<?xml version="1.0" encoding="utf-8" standalone="no"?>
<device schemaVersion="1.1" xmlns:xs="http://www.w3.org/2001/XMLSchema-instance" noNamespaceSchemaLocation="CMSIS-SVD.xsd">
  <vendor>PUYA Co.Ltd</vendor>
  <vendorID>PUYA</vendorID>
  <name>PY32F410xx</name>
  <series>ARMCM4</series>
  <version>1.2</version>
  <cpu>
    <name>CM4</name>
    <revision>r0p1</revision>
    <endian>little</endian>
    <mpuPresent>true</mpuPresent>
    <fpuPresent>true</fpuPresent>
    <nvicPrioBits>4</nvicPrioBits>
    <vendorSystickConfig>false</vendorSystickConfig>
  </cpu>
  <addressUnitBits>8</addressUnitBits>
  <width>32</width>
  <size>32</size>
  <access>read-write</access>
  <resetValue>0x0</resetValue>
  <resetMask>0xFFFFFFFF</resetMask>
  <peripherals>
    <peripheral>
      <name>ADC</name>
      <baseAddress>0x40012400</baseAddress>
      <addressBlock>
        <offset>0x0</offset>
        <size>0x310</size>
        <usage>registers</usage>
      </addressBlock>
      <registers>
        <register>
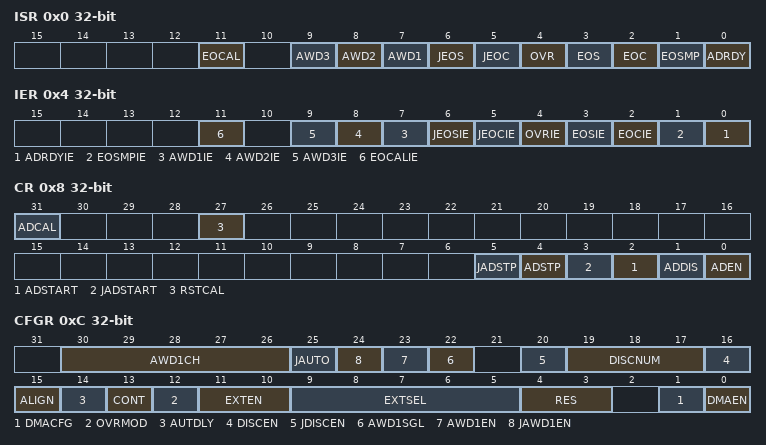
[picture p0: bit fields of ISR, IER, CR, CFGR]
          <name>ISR</name>
          <addressOffset>0x0</addressOffset>
          <fields>
            <field>
              <name>ADRDY</name>
              <bitRange>[0:0]</bitRange>
            </field>
            <field>
              <name>EOSMP</name>
              <bitRange>[1:1]</bitRange>
            </field>
            <field>
              <name>EOC</name>
              <bitRange>[2:2]</bitRange>
            </field>
            <field>
              <name>EOS</name>
              <bitRange>[3:3]</bitRange>
            </field>
            <field>
              <name>OVR</name>
              <bitRange>[4:4]</bitRange>
            </field>
            <field>
              <name>JEOC</name>
              <bitRange>[5:5]</bitRange>
            </field>
            <field>
              <name>JEOS</name>
              <bitRange>[6:6]</bitRange>
            </field>
            <field>
              <name>AWD1</name>
              <bitRange>[7:7]</bitRange>
            </field>
            <field>
              <name>AWD2</name>
              <bitRange>[8:8]</bitRange>
            </field>
            <field>
              <name>AWD3</name>
              <bitRange>[9:9]</bitRange>
            </field>
            <field>
              <name>EOCAL</name>
              <bitRange>[11:11]</bitRange>
            </field>
          </fields>
        </register>
        <register>
          <name>IER</name>
          <addressOffset>0x4</addressOffset>
          <fields>
            <field>
              <name>ADRDYIE</name>
              <bitRange>[0:0]</bitRange>
            </field>
            <field>
              <name>EOSMPIE</name>
              <bitRange>[1:1]</bitRange>
            </field>
            <field>
              <name>EOCIE</name>
              <bitRange>[2:2]</bitRange>
            </field>
            <field>
              <name>EOSIE</name>
              <bitRange>[3:3]</bitRange>
            </field>
            <field>
              <name>OVRIE</name>
              <bitRange>[4:4]</bitRange>
            </field>
            <field>
              <name>JEOCIE</name>
              <bitRange>[5:5]</bitRange>
            </field>
            <field>
              <name>JEOSIE</name>
              <bitRange>[6:6]</bitRange>
            </field>
            <field>
              <name>AWD1IE</name>
              <bitRange>[7:7]</bitRange>
            </field>
            <field>
              <name>AWD2IE</name>
              <bitRange>[8:8]</bitRange>
            </field>
            <field>
              <name>AWD3IE</name>
              <bitRange>[9:9]</bitRange>
            </field>
            <field>
              <name>EOCALIE</name>
              <bitRange>[11:11]</bitRange>
            </field>
          </fields>
        </register>
        <register>
          <name>CR</name>
          <addressOffset>0x8</addressOffset>
          <fields>
            <field>
              <name>ADEN</name>
              <bitRange>[0:0]</bitRange>
            </field>
            <field>
              <name>ADDIS</name>
              <bitRange>[1:1]</bitRange>
            </field>
            <field>
              <name>ADSTART</name>
              <bitRange>[2:2]</bitRange>
            </field>
            <field>
              <name>JADSTART</name>
              <bitRange>[3:3]</bitRange>
            </field>
            <field>
              <name>ADSTP</name>
              <bitRange>[4:4]</bitRange>
            </field>
            <field>
              <name>JADSTP</name>
              <bitRange>[5:5]</bitRange>
            </field>
            <field>
              <name>RSTCAL</name>
              <bitRange>[27:27]</bitRange>
            </field>
            <field>
              <name>ADCAL</name>
              <bitRange>[31:31]</bitRange>
            </field>
          </fields>
        </register>
        <register>
          <name>CFGR</name>
          <addressOffset>0xC</addressOffset>
          <fields>
            <field>
              <name>DMAEN</name>
              <bitRange>[0:0]</bitRange>
            </field>
            <field>
              <name>DMACFG</name>
              <bitRange>[1:1]</bitRange>
            </field>
            <field>
              <name>RES</name>
              <bitRange>[4:3]</bitRange>
            </field>
            <field>
              <name>EXTSEL</name>
              <bitRange>[9:5]</bitRange>
            </field>
            <field>
              <name>EXTEN</name>
              <bitRange>[11:10]</bitRange>
            </field>
            <field>
              <name>OVRMOD</name>
              <bitRange>[12:12]</bitRange>
            </field>
            <field>
              <name>CONT</name>
              <bitRange>[13:13]</bitRange>
            </field>
            <field>
              <name>AUTDLY</name>
              <bitRange>[14:14]</bitRange>
            </field>
            <field>
              <name>ALIGN</name>
              <bitRange>[15:15]</bitRange>
            </field>
            <field>
              <name>DISCEN</name>
              <bitRange>[16:16]</bitRange>
            </field>
            <field>
              <name>DISCNUM</name>
              <bitRange>[19:17]</bitRange>
            </field>
            <field>
              <name>JDISCEN</name>
              <bitRange>[20:20]</bitRange>
            </field>
            <field>
              <name>AWD1SGL</name>
              <bitRange>[22:22]</bitRange>
            </field>
            <field>
              <name>AWD1EN</name>
              <bitRange>[23:23]</bitRange>
            </field>
            <field>
              <name>JAWD1EN</name>
              <bitRange>[24:24]</bitRange>
            </field>
            <field>
              <name>JAUTO</name>
              <bitRange>[25:25]</bitRange>
            </field>
            <field>
              <name>AWD1CH</name>
              <bitRange>[30:26]</bitRange>
            </field>
          </fields>
        </register>
        <register>
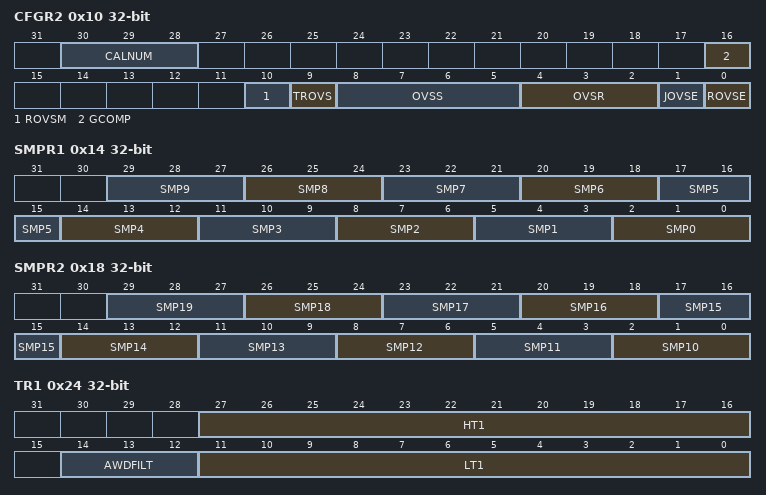
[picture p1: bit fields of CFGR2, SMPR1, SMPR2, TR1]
          <name>CFGR2</name>
          <addressOffset>0x10</addressOffset>
          <fields>
            <field>
              <name>ROVSE</name>
              <bitRange>[0:0]</bitRange>
            </field>
            <field>
              <name>JOVSE</name>
              <bitRange>[1:1]</bitRange>
            </field>
            <field>
              <name>OVSR</name>
              <bitRange>[4:2]</bitRange>
            </field>
            <field>
              <name>OVSS</name>
              <bitRange>[8:5]</bitRange>
            </field>
            <field>
              <name>TROVS</name>
              <bitRange>[9:9]</bitRange>
            </field>
            <field>
              <name>ROVSM</name>
              <bitRange>[10:10]</bitRange>
            </field>
            <field>
              <name>GCOMP</name>
              <bitRange>[16:16]</bitRange>
            </field>
            <field>
              <name>CALNUM</name>
              <bitRange>[30:28]</bitRange>
            </field>
          </fields>
        </register>
        <register>
          <name>SMPR1</name>
          <addressOffset>0x14</addressOffset>
          <fields>
            <field>
              <name>SMP0</name>
              <bitRange>[2:0]</bitRange>
            </field>
            <field>
              <name>SMP1</name>
              <bitRange>[5:3]</bitRange>
            </field>
            <field>
              <name>SMP2</name>
              <bitRange>[8:6]</bitRange>
            </field>
            <field>
              <name>SMP3</name>
              <bitRange>[11:9]</bitRange>
            </field>
            <field>
              <name>SMP4</name>
              <bitRange>[14:12]</bitRange>
            </field>
            <field>
              <name>SMP5</name>
              <bitRange>[17:15]</bitRange>
            </field>
            <field>
              <name>SMP6</name>
              <bitRange>[20:18]</bitRange>
            </field>
            <field>
              <name>SMP7</name>
              <bitRange>[23:21]</bitRange>
            </field>
            <field>
              <name>SMP8</name>
              <bitRange>[26:24]</bitRange>
            </field>
            <field>
              <name>SMP9</name>
              <bitRange>[29:27]</bitRange>
            </field>
          </fields>
        </register>
        <register>
          <name>SMPR2</name>
          <addressOffset>0x18</addressOffset>
          <fields>
            <field>
              <name>SMP10</name>
              <bitRange>[2:0]</bitRange>
            </field>
            <field>
              <name>SMP11</name>
              <bitRange>[5:3]</bitRange>
            </field>
            <field>
              <name>SMP12</name>
              <bitRange>[8:6]</bitRange>
            </field>
            <field>
              <name>SMP13</name>
              <bitRange>[11:9]</bitRange>
            </field>
            <field>
              <name>SMP14</name>
              <bitRange>[14:12]</bitRange>
            </field>
            <field>
              <name>SMP15</name>
              <bitRange>[17:15]</bitRange>
            </field>
            <field>
              <name>SMP16</name>
              <bitRange>[20:18]</bitRange>
            </field>
            <field>
              <name>SMP17</name>
              <bitRange>[23:21]</bitRange>
            </field>
            <field>
              <name>SMP18</name>
              <bitRange>[26:24]</bitRange>
            </field>
            <field>
              <name>SMP19</name>
              <bitRange>[29:27]</bitRange>
            </field>
          </fields>
        </register>
        <register>
          <name>SMPR3</name>
          <addressOffset>0x20</addressOffset>
          <fields>
            <field>
              <name>SMP20</name>
              <bitRange>[2:0]</bitRange>
            </field>
          </fields>
        </register>
        <register>
          <name>TR1</name>
          <addressOffset>0x24</addressOffset>
          <fields>
            <field>
              <name>LT1</name>
              <bitRange>[11:0]</bitRange>
            </field>
            <field>
              <name>AWDFILT</name>
              <bitRange>[14:12]</bitRange>
            </field>
            <field>
              <name>HT1</name>
              <bitRange>[27:16]</bitRange>
            </field>
          </fields>
        </register>
        <register>
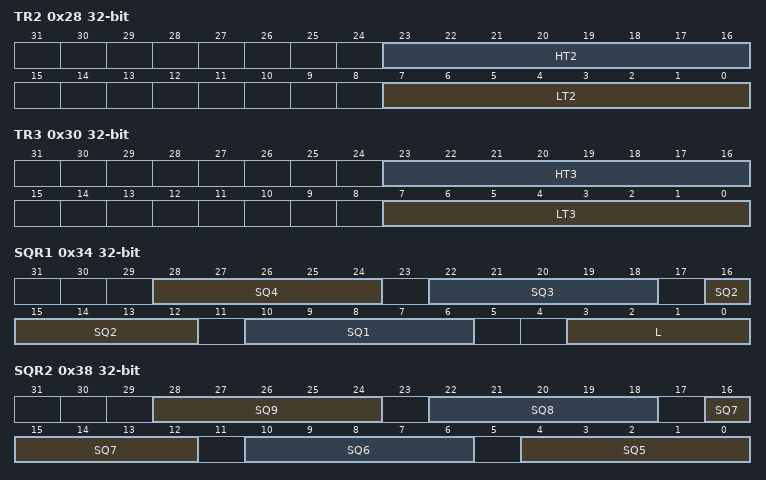
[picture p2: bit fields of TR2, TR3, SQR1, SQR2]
          <name>TR2</name>
          <addressOffset>0x28</addressOffset>
          <fields>
            <field>
              <name>LT2</name>
              <bitRange>[7:0]</bitRange>
            </field>
            <field>
              <name>HT2</name>
              <bitRange>[23:16]</bitRange>
            </field>
          </fields>
        </register>
        <register>
          <name>TR3</name>
          <addressOffset>0x30</addressOffset>
          <fields>
            <field>
              <name>LT3</name>
              <bitRange>[7:0]</bitRange>
            </field>
            <field>
              <name>HT3</name>
              <bitRange>[23:16]</bitRange>
            </field>
          </fields>
        </register>
        <register>
          <name>SQR1</name>
          <addressOffset>0x34</addressOffset>
          <fields>
            <field>
              <name>L</name>
              <bitRange>[3:0]</bitRange>
            </field>
            <field>
              <name>SQ1</name>
              <bitRange>[10:6]</bitRange>
            </field>
            <field>
              <name>SQ2</name>
              <bitRange>[16:12]</bitRange>
            </field>
            <field>
              <name>SQ3</name>
              <bitRange>[22:18]</bitRange>
            </field>
            <field>
              <name>SQ4</name>
              <bitRange>[28:24]</bitRange>
            </field>
          </fields>
        </register>
        <register>
          <name>SQR2</name>
          <addressOffset>0x38</addressOffset>
          <fields>
            <field>
              <name>SQ5</name>
              <bitRange>[4:0]</bitRange>
            </field>
            <field>
              <name>SQ6</name>
              <bitRange>[10:6]</bitRange>
            </field>
            <field>
              <name>SQ7</name>
              <bitRange>[16:12]</bitRange>
            </field>
            <field>
              <name>SQ8</name>
              <bitRange>[22:18]</bitRange>
            </field>
            <field>
              <name>SQ9</name>
              <bitRange>[28:24]</bitRange>
            </field>
          </fields>
        </register>
        <register>
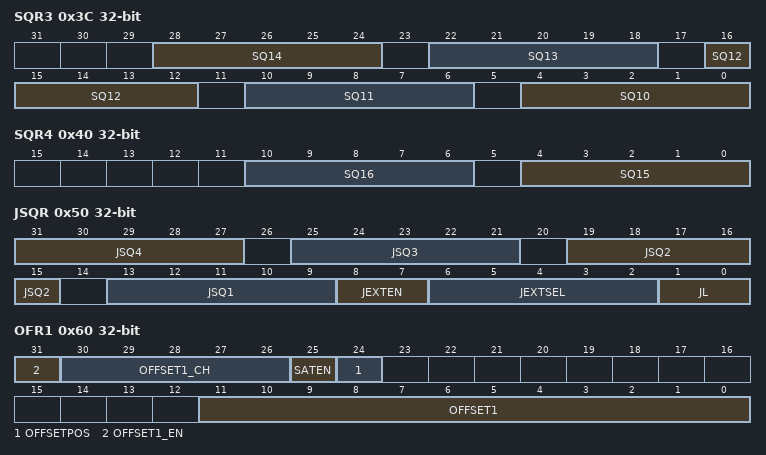
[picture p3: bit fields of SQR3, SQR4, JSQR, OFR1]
          <name>SQR3</name>
          <addressOffset>0x3C</addressOffset>
          <fields>
            <field>
              <name>SQ10</name>
              <bitRange>[4:0]</bitRange>
            </field>
            <field>
              <name>SQ11</name>
              <bitRange>[10:6]</bitRange>
            </field>
            <field>
              <name>SQ12</name>
              <bitRange>[16:12]</bitRange>
            </field>
            <field>
              <name>SQ13</name>
              <bitRange>[22:18]</bitRange>
            </field>
            <field>
              <name>SQ14</name>
              <bitRange>[28:24]</bitRange>
            </field>
          </fields>
        </register>
        <register>
          <name>SQR4</name>
          <addressOffset>0x40</addressOffset>
          <fields>
            <field>
              <name>SQ15</name>
              <bitRange>[4:0]</bitRange>
            </field>
            <field>
              <name>SQ16</name>
              <bitRange>[10:6]</bitRange>
            </field>
          </fields>
        </register>
        <register>
          <name>DR</name>
          <addressOffset>0x4C</addressOffset>
          <fields>
            <field>
              <name>RDATA</name>
              <bitRange>[15:0]</bitRange>
              <access>read-only</access>
            </field>
          </fields>
        </register>
        <register>
          <name>JSQR</name>
          <addressOffset>0x50</addressOffset>
          <fields>
            <field>
              <name>JL</name>
              <bitRange>[1:0]</bitRange>
            </field>
            <field>
              <name>JEXTSEL</name>
              <bitRange>[6:2]</bitRange>
            </field>
            <field>
              <name>JEXTEN</name>
              <bitRange>[8:7]</bitRange>
            </field>
            <field>
              <name>JSQ1</name>
              <bitRange>[13:9]</bitRange>
            </field>
            <field>
              <name>JSQ2</name>
              <bitRange>[19:15]</bitRange>
            </field>
            <field>
              <name>JSQ3</name>
              <bitRange>[25:21]</bitRange>
            </field>
            <field>
              <name>JSQ4</name>
              <bitRange>[31:27]</bitRange>
            </field>
          </fields>
        </register>
        <register>
          <name>OFR1</name>
          <addressOffset>0x60</addressOffset>
          <fields>
            <field>
              <name>OFFSET1</name>
              <bitRange>[11:0]</bitRange>
            </field>
            <field>
              <name>OFFSETPOS</name>
              <bitRange>[24:24]</bitRange>
            </field>
            <field>
              <name>SATEN</name>
              <bitRange>[25:25]</bitRange>
            </field>
            <field>
              <name>OFFSET1_CH</name>
              <bitRange>[30:26]</bitRange>
            </field>
            <field>
              <name>OFFSET1_EN</name>
              <bitRange>[31:31]</bitRange>
            </field>
          </fields>
        </register>
        <register>
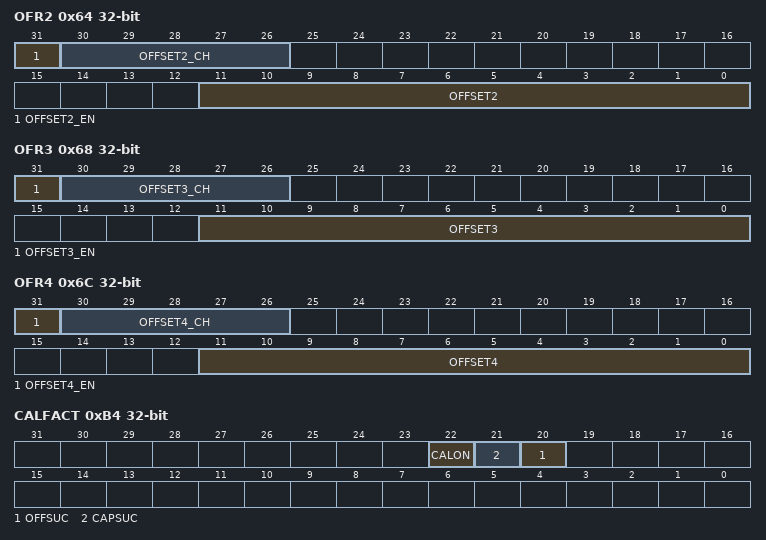
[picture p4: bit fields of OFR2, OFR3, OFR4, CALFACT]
          <name>OFR2</name>
          <addressOffset>0x64</addressOffset>
          <fields>
            <field>
              <name>OFFSET2</name>
              <bitRange>[11:0]</bitRange>
            </field>
            <field>
              <name>OFFSET2_CH</name>
              <bitRange>[30:26]</bitRange>
            </field>
            <field>
              <name>OFFSET2_EN</name>
              <bitRange>[31:31]</bitRange>
            </field>
          </fields>
        </register>
        <register>
          <name>OFR3</name>
          <addressOffset>0x68</addressOffset>
          <fields>
            <field>
              <name>OFFSET3</name>
              <bitRange>[11:0]</bitRange>
            </field>
            <field>
              <name>OFFSET3_CH</name>
              <bitRange>[30:26]</bitRange>
            </field>
            <field>
              <name>OFFSET3_EN</name>
              <bitRange>[31:31]</bitRange>
            </field>
          </fields>
        </register>
        <register>
          <name>OFR4</name>
          <addressOffset>0x6C</addressOffset>
          <fields>
            <field>
              <name>OFFSET4</name>
              <bitRange>[11:0]</bitRange>
            </field>
            <field>
              <name>OFFSET4_CH</name>
              <bitRange>[30:26]</bitRange>
            </field>
            <field>
              <name>OFFSET4_EN</name>
              <bitRange>[31:31]</bitRange>
            </field>
          </fields>
        </register>
        <register>
          <name>JDR1</name>
          <addressOffset>0x80</addressOffset>
          <fields>
            <field>
              <name>JDATA</name>
              <bitRange>[15:0]</bitRange>
              <access>read-only</access>
            </field>
          </fields>
        </register>
        <register>
          <name>JDR2</name>
          <addressOffset>0x84</addressOffset>
          <fields>
            <field>
              <name>JDATA</name>
              <bitRange>[15:0]</bitRange>
              <access>read-only</access>
            </field>
          </fields>
        </register>
        <register>
          <name>JDR3</name>
          <addressOffset>0x88</addressOffset>
          <fields>
            <field>
              <name>JDATA</name>
              <bitRange>[15:0]</bitRange>
              <access>read-only</access>
            </field>
          </fields>
        </register>
        <register>
          <name>JDR4</name>
          <addressOffset>0x8C</addressOffset>
          <fields>
            <field>
              <name>JDATA</name>
              <bitRange>[15:0]</bitRange>
              <access>read-only</access>
            </field>
          </fields>
        </register>
        <register>
          <name>AWD2CR</name>
          <addressOffset>0xA0</addressOffset>
          <fields>
            <field>
              <name>AWD2CH</name>
              <bitRange>[20:0]</bitRange>
            </field>
          </fields>
        </register>
        <register>
          <name>AWD3CR</name>
          <addressOffset>0xA4</addressOffset>
          <fields>
            <field>
              <name>AWD3CH</name>
              <bitRange>[20:0]</bitRange>
            </field>
          </fields>
        </register>
        <register>
          <name>CALFACT</name>
          <addressOffset>0xB4</addressOffset>
          <fields>
            <field>
              <name>OFFSUC</name>
              <bitRange>[20:20]</bitRange>
            </field>
            <field>
              <name>CAPSUC</name>
              <bitRange>[21:21]</bitRange>
            </field>
            <field>
              <name>CALON</name>
              <bitRange>[22:22]</bitRange>
              <access>read-only</access>
            </field>
          </fields>
        </register>
        <register>
          <name>GCOMP</name>
          <addressOffset>0xC0</addressOffset>
          <fields>
            <field>
              <name>GCOMPCOEFF</name>
              <bitRange>[13:0]</bitRange>
            </field>
          </fields>
        </register>
        <register>
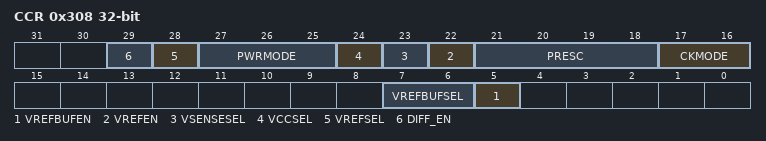
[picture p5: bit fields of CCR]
          <name>CCR</name>
          <addressOffset>0x308</addressOffset>
          <fields>
            <field>
              <name>VREFBUFEN</name>
              <bitRange>[5:5]</bitRange>
            </field>
            <field>
              <name>VREFBUFSEL</name>
              <bitRange>[7:6]</bitRange>
            </field>
            <field>
              <name>CKMODE</name>
              <bitRange>[17:16]</bitRange>
            </field>
            <field>
              <name>PRESC</name>
              <bitRange>[21:18]</bitRange>
            </field>
            <field>
              <name>VREFEN</name>
              <bitRange>[22:22]</bitRange>
            </field>
            <field>
              <name>VSENSESEL</name>
              <bitRange>[23:23]</bitRange>
            </field>
            <field>
              <name>VCCSEL</name>
              <bitRange>[24:24]</bitRange>
            </field>
            <field>
              <name>PWRMODE</name>
              <bitRange>[27:25]</bitRange>
            </field>
            <field>
              <name>VREFSEL</name>
              <bitRange>[28:28]</bitRange>
            </field>
            <field>
              <name>DIFF_EN</name>
              <bitRange>[29:29]</bitRange>
            </field>
          </fields>
        </register>
      </registers>
    </peripheral>
    <peripheral>
      <name>COMP1</name>
      <groupName>COMP</groupName>
      <baseAddress>0x40016C00</baseAddress>
      <addressBlock>
        <offset>0x0</offset>
        <size>0x10</size>
        <usage>registers</usage>
      </addressBlock>
      <registers>
        <register>
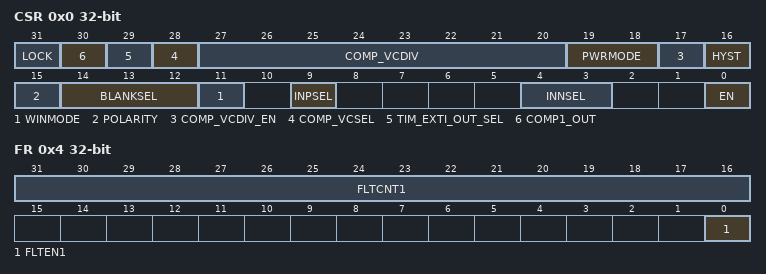
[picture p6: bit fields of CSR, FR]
          <name>CSR</name>
          <addressOffset>0x0</addressOffset>
          <fields>
            <field>
              <name>EN</name>
              <bitRange>[0:0]</bitRange>
            </field>
            <field>
              <name>INNSEL</name>
              <bitRange>[4:3]</bitRange>
            </field>
            <field>
              <name>INPSEL</name>
              <bitRange>[9:9]</bitRange>
            </field>
            <field>
              <name>WINMODE</name>
              <bitRange>[11:11]</bitRange>
            </field>
            <field>
              <name>BLANKSEL</name>
              <bitRange>[14:12]</bitRange>
            </field>
            <field>
              <name>POLARITY</name>
              <bitRange>[15:15]</bitRange>
            </field>
            <field>
              <name>HYST</name>
              <bitRange>[16:16]</bitRange>
            </field>
            <field>
              <name>COMP_VCDIV_EN</name>
              <bitRange>[17:17]</bitRange>
            </field>
            <field>
              <name>PWRMODE</name>
              <bitRange>[19:18]</bitRange>
            </field>
            <field>
              <name>COMP_VCDIV</name>
              <bitRange>[27:20]</bitRange>
            </field>
            <field>
              <name>COMP_VCSEL</name>
              <bitRange>[28:28]</bitRange>
            </field>
            <field>
              <name>TIM_EXTI_OUT_SEL</name>
              <bitRange>[29:29]</bitRange>
            </field>
            <field>
              <name>COMP1_OUT</name>
              <bitRange>[30:30]</bitRange>
              <access>read-only</access>
            </field>
            <field>
              <name>LOCK</name>
              <bitRange>[31:31]</bitRange>
            </field>
          </fields>
        </register>
        <register>
          <name>FR</name>
          <addressOffset>0x4</addressOffset>
          <fields>
            <field>
              <name>FLTEN1</name>
              <bitRange>[0:0]</bitRange>
            </field>
            <field>
              <name>FLTCNT1</name>
              <bitRange>[31:16]</bitRange>
            </field>
          </fields>
        </register>
      </registers>
    </peripheral>
    <peripheral derivedFrom="COMP1">
      <name>COMP2</name>
      <baseAddress>0x40016C10</baseAddress>
    </peripheral>
    <peripheral>
      <name>CRC</name>
      <baseAddress>0x40023000</baseAddress>
      <addressBlock>
        <offset>0x0</offset>
        <size>0x10</size>
        <usage>registers</usage>
      </addressBlock>
      <registers>
        <register>
          <name>DR</name>
          <addressOffset>0x0</addressOffset>
          <fields>
            <field>
              <name>DR</name>
              <description>CRC data</description>
              <bitRange>[31:0]</bitRange>
            </field>
          </fields>
        </register>
        <register>
          <name>IDR</name>
          <addressOffset>0x4</addressOffset>
          <fields>
            <field>
              <name>IDR</name>
              <description>CRC independent data</description>
              <bitRange>[7:0]</bitRange>
            </field>
          </fields>
        </register>
        <register>
          <name>CR</name>
          <addressOffset>0x8</addressOffset>
          <fields>
            <field>
              <name>RESET</name>
              <description>CRC software reset</description>
              <bitRange>[0:0]</bitRange>
            </field>
          </fields>
        </register>
      </registers>
    </peripheral>
    <peripheral>
      <name>DBG</name>
      <baseAddress>0xE0042000</baseAddress>
      <addressBlock>
        <offset>0x0</offset>
        <size>0x10</size>
        <usage>registers</usage>
      </addressBlock>
      <registers>
        <register>
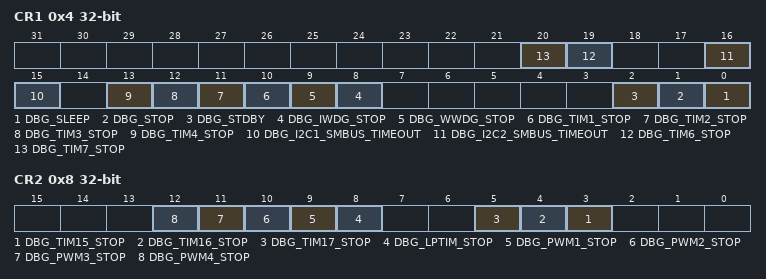
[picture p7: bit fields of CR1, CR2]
          <name>CR1</name>
          <addressOffset>0x4</addressOffset>
          <fields>
            <field>
              <name>DBG_SLEEP</name>
              <bitRange>[0:0]</bitRange>
            </field>
            <field>
              <name>DBG_STOP</name>
              <bitRange>[1:1]</bitRange>
            </field>
            <field>
              <name>DBG_STDBY</name>
              <bitRange>[2:2]</bitRange>
            </field>
            <field>
              <name>DBG_IWDG_STOP</name>
              <bitRange>[8:8]</bitRange>
            </field>
            <field>
              <name>DBG_WWDG_STOP</name>
              <bitRange>[9:9]</bitRange>
            </field>
            <field>
              <name>DBG_TIM1_STOP</name>
              <bitRange>[10:10]</bitRange>
            </field>
            <field>
              <name>DBG_TIM2_STOP</name>
              <bitRange>[11:11]</bitRange>
            </field>
            <field>
              <name>DBG_TIM3_STOP</name>
              <bitRange>[12:12]</bitRange>
            </field>
            <field>
              <name>DBG_TIM4_STOP</name>
              <bitRange>[13:13]</bitRange>
            </field>
            <field>
              <name>DBG_I2C1_SMBUS_TIMEOUT</name>
              <bitRange>[15:15]</bitRange>
            </field>
            <field>
              <name>DBG_I2C2_SMBUS_TIMEOUT</name>
              <bitRange>[16:16]</bitRange>
            </field>
            <field>
              <name>DBG_TIM6_STOP</name>
              <bitRange>[19:19]</bitRange>
            </field>
            <field>
              <name>DBG_TIM7_STOP</name>
              <bitRange>[20:20]</bitRange>
            </field>
          </fields>
        </register>
        <register>
          <name>CR2</name>
          <addressOffset>0x8</addressOffset>
          <fields>
            <field>
              <name>DBG_TIM15_STOP</name>
              <bitRange>[3:3]</bitRange>
            </field>
            <field>
              <name>DBG_TIM16_STOP</name>
              <bitRange>[4:4]</bitRange>
            </field>
            <field>
              <name>DBG_TIM17_STOP</name>
              <bitRange>[5:5]</bitRange>
            </field>
            <field>
              <name>DBG_LPTIM_STOP</name>
              <bitRange>[8:8]</bitRange>
            </field>
            <field>
              <name>DBG_PWM1_STOP</name>
              <bitRange>[9:9]</bitRange>
            </field>
            <field>
              <name>DBG_PWM2_STOP</name>
              <bitRange>[10:10]</bitRange>
            </field>
            <field>
              <name>DBG_PWM3_STOP</name>
              <bitRange>[11:11]</bitRange>
            </field>
            <field>
              <name>DBG_PWM4_STOP</name>
              <bitRange>[12:12]</bitRange>
            </field>
          </fields>
        </register>
      </registers>
    </peripheral>
    <peripheral>
      <name>DMA</name>
      <baseAddress>0x40020000</baseAddress>
      <addressBlock>
        <offset>0x0</offset>
        <size>0xB0</size>
        <usage>registers</usage>
      </addressBlock>
      <registers>
        <register>
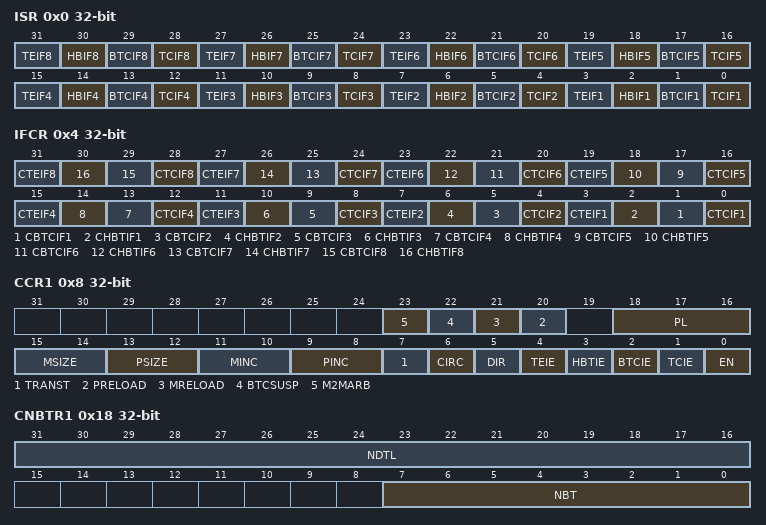
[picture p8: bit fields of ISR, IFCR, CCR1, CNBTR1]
          <name>ISR</name>
          <addressOffset>0x0</addressOffset>
          <fields>
            <field>
              <name>TCIF1</name>
              <bitRange>[0:0]</bitRange>
              <access>read-only</access>
            </field>
            <field>
              <name>BTCIF1</name>
              <bitRange>[1:1]</bitRange>
              <access>read-only</access>
            </field>
            <field>
              <name>HBIF1</name>
              <bitRange>[2:2]</bitRange>
              <access>read-only</access>
            </field>
            <field>
              <name>TEIF1</name>
              <bitRange>[3:3]</bitRange>
              <access>read-only</access>
            </field>
            <field>
              <name>TCIF2</name>
              <bitRange>[4:4]</bitRange>
              <access>read-only</access>
            </field>
            <field>
              <name>BTCIF2</name>
              <bitRange>[5:5]</bitRange>
              <access>read-only</access>
            </field>
            <field>
              <name>HBIF2</name>
              <bitRange>[6:6]</bitRange>
              <access>read-only</access>
            </field>
            <field>
              <name>TEIF2</name>
              <bitRange>[7:7]</bitRange>
              <access>read-only</access>
            </field>
            <field>
              <name>TCIF3</name>
              <bitRange>[8:8]</bitRange>
              <access>read-only</access>
            </field>
            <field>
              <name>BTCIF3</name>
              <bitRange>[9:9]</bitRange>
              <access>read-only</access>
            </field>
            <field>
              <name>HBIF3</name>
              <bitRange>[10:10]</bitRange>
              <access>read-only</access>
            </field>
            <field>
              <name>TEIF3</name>
              <bitRange>[11:11]</bitRange>
              <access>read-only</access>
            </field>
            <field>
              <name>TCIF4</name>
              <bitRange>[12:12]</bitRange>
              <access>read-only</access>
            </field>
            <field>
              <name>BTCIF4</name>
              <bitRange>[13:13]</bitRange>
              <access>read-only</access>
            </field>
            <field>
              <name>HBIF4</name>
              <bitRange>[14:14]</bitRange>
              <access>read-only</access>
            </field>
            <field>
              <name>TEIF4</name>
              <bitRange>[15:15]</bitRange>
              <access>read-only</access>
            </field>
            <field>
              <name>TCIF5</name>
              <bitRange>[16:16]</bitRange>
              <access>read-only</access>
            </field>
            <field>
              <name>BTCIF5</name>
              <bitRange>[17:17]</bitRange>
              <access>read-only</access>
            </field>
            <field>
              <name>HBIF5</name>
              <bitRange>[18:18]</bitRange>
              <access>read-only</access>
            </field>
            <field>
              <name>TEIF5</name>
              <bitRange>[19:19]</bitRange>
              <access>read-only</access>
            </field>
            <field>
              <name>TCIF6</name>
              <bitRange>[20:20]</bitRange>
              <access>read-only</access>
            </field>
            <field>
              <name>BTCIF6</name>
              <bitRange>[21:21]</bitRange>
              <access>read-only</access>
            </field>
            <field>
              <name>HBIF6</name>
              <bitRange>[22:22]</bitRange>
              <access>read-only</access>
            </field>
            <field>
              <name>TEIF6</name>
              <bitRange>[23:23]</bitRange>
              <access>read-only</access>
            </field>
            <field>
              <name>TCIF7</name>
              <bitRange>[24:24]</bitRange>
              <access>read-only</access>
            </field>
            <field>
              <name>BTCIF7</name>
              <bitRange>[25:25]</bitRange>
              <access>read-only</access>
            </field>
            <field>
              <name>HBIF7</name>
              <bitRange>[26:26]</bitRange>
              <access>read-only</access>
            </field>
            <field>
              <name>TEIF7</name>
              <bitRange>[27:27]</bitRange>
              <access>read-only</access>
            </field>
            <field>
              <name>TCIF8</name>
              <bitRange>[28:28]</bitRange>
              <access>read-only</access>
            </field>
            <field>
              <name>BTCIF8</name>
              <bitRange>[29:29]</bitRange>
              <access>read-only</access>
            </field>
            <field>
              <name>HBIF8</name>
              <bitRange>[30:30]</bitRange>
              <access>read-only</access>
            </field>
            <field>
              <name>TEIF8</name>
              <bitRange>[31:31]</bitRange>
              <access>read-only</access>
            </field>
          </fields>
        </register>
        <register>
          <name>IFCR</name>
          <addressOffset>0x4</addressOffset>
          <fields>
            <field>
              <name>CTCIF1</name>
              <bitRange>[0:0]</bitRange>
            </field>
            <field>
              <name>CBTCIF1</name>
              <bitRange>[1:1]</bitRange>
            </field>
            <field>
              <name>CHBTIF1</name>
              <bitRange>[2:2]</bitRange>
            </field>
            <field>
              <name>CTEIF1</name>
              <bitRange>[3:3]</bitRange>
            </field>
            <field>
              <name>CTCIF2</name>
              <bitRange>[4:4]</bitRange>
            </field>
            <field>
              <name>CBTCIF2</name>
              <bitRange>[5:5]</bitRange>
            </field>
            <field>
              <name>CHBTIF2</name>
              <bitRange>[6:6]</bitRange>
            </field>
            <field>
              <name>CTEIF2</name>
              <bitRange>[7:7]</bitRange>
            </field>
            <field>
              <name>CTCIF3</name>
              <bitRange>[8:8]</bitRange>
            </field>
            <field>
              <name>CBTCIF3</name>
              <bitRange>[9:9]</bitRange>
            </field>
            <field>
              <name>CHBTIF3</name>
              <bitRange>[10:10]</bitRange>
            </field>
            <field>
              <name>CTEIF3</name>
              <bitRange>[11:11]</bitRange>
            </field>
            <field>
              <name>CTCIF4</name>
              <bitRange>[12:12]</bitRange>
            </field>
            <field>
              <name>CBTCIF4</name>
              <bitRange>[13:13]</bitRange>
            </field>
            <field>
              <name>CHBTIF4</name>
              <bitRange>[14:14]</bitRange>
            </field>
            <field>
              <name>CTEIF4</name>
              <bitRange>[15:15]</bitRange>
            </field>
            <field>
              <name>CTCIF5</name>
              <bitRange>[16:16]</bitRange>
            </field>
            <field>
              <name>CBTCIF5</name>
              <bitRange>[17:17]</bitRange>
            </field>
            <field>
              <name>CHBTIF5</name>
              <bitRange>[18:18]</bitRange>
            </field>
            <field>
              <name>CTEIF5</name>
              <bitRange>[19:19]</bitRange>
            </field>
            <field>
              <name>CTCIF6</name>
              <bitRange>[20:20]</bitRange>
            </field>
            <field>
              <name>CBTCIF6</name>
              <bitRange>[21:21]</bitRange>
            </field>
            <field>
              <name>CHBTIF6</name>
              <bitRange>[22:22]</bitRange>
            </field>
            <field>
              <name>CTEIF6</name>
              <bitRange>[23:23]</bitRange>
            </field>
            <field>
              <name>CTCIF7</name>
              <bitRange>[24:24]</bitRange>
            </field>
            <field>
              <name>CBTCIF7</name>
              <bitRange>[25:25]</bitRange>
            </field>
            <field>
              <name>CHBTIF7</name>
              <bitRange>[26:26]</bitRange>
            </field>
            <field>
              <name>CTEIF7</name>
              <bitRange>[27:27]</bitRange>
            </field>
            <field>
              <name>CTCIF8</name>
              <bitRange>[28:28]</bitRange>
            </field>
            <field>
              <name>CBTCIF8</name>
              <bitRange>[29:29]</bitRange>
            </field>
            <field>
              <name>CHBTIF8</name>
              <bitRange>[30:30]</bitRange>
            </field>
            <field>
              <name>CTEIF8</name>
              <bitRange>[31:31]</bitRange>
            </field>
          </fields>
        </register>
        <register>
          <name>CCR1</name>
          <addressOffset>0x8</addressOffset>
          <fields>
            <field>
              <name>EN</name>
              <bitRange>[0:0]</bitRange>
            </field>
            <field>
              <name>TCIE</name>
              <bitRange>[1:1]</bitRange>
            </field>
            <field>
              <name>BTCIE</name>
              <bitRange>[2:2]</bitRange>
            </field>
            <field>
              <name>HBTIE</name>
              <bitRange>[3:3]</bitRange>
            </field>
            <field>
              <name>TEIE</name>
              <bitRange>[4:4]</bitRange>
            </field>
            <field>
              <name>DIR</name>
              <bitRange>[5:5]</bitRange>
            </field>
            <field>
              <name>CIRC</name>
              <bitRange>[6:6]</bitRange>
            </field>
            <field>
              <name>TRANST</name>
              <bitRange>[7:7]</bitRange>
            </field>
            <field>
              <name>PINC</name>
              <bitRange>[9:8]</bitRange>
            </field>
            <field>
              <name>MINC</name>
              <bitRange>[11:10]</bitRange>
            </field>
            <field>
              <name>PSIZE</name>
              <bitRange>[13:12]</bitRange>
            </field>
            <field>
              <name>MSIZE</name>
              <bitRange>[15:14]</bitRange>
            </field>
            <field>
              <name>PL</name>
              <bitRange>[18:16]</bitRange>
            </field>
            <field>
              <name>PRELOAD</name>
              <bitRange>[20:20]</bitRange>
            </field>
            <field>
              <name>MRELOAD</name>
              <bitRange>[21:21]</bitRange>
            </field>
            <field>
              <name>BTCSUSP</name>
              <bitRange>[22:22]</bitRange>
            </field>
            <field>
              <name>M2MARB</name>
              <bitRange>[23:23]</bitRange>
            </field>
          </fields>
        </register>
        <register>
          <name>CNDTR1</name>
          <addressOffset>0xC</addressOffset>
          <fields>
            <field>
              <name>NDT</name>
              <bitRange>[15:0]</bitRange>
            </field>
          </fields>
        </register>
        <register>
          <name>CPAR1</name>
          <addressOffset>0x10</addressOffset>
          <fields>
            <field>
              <name>PA</name>
              <bitRange>[31:0]</bitRange>
            </field>
          </fields>
        </register>
        <register>
          <name>CMAR1</name>
          <addressOffset>0x14</addressOffset>
          <fields>
            <field>
              <name>MA</name>
              <bitRange>[31:0]</bitRange>
            </field>
          </fields>
        </register>
        <register>
          <name>CNBTR1</name>
          <addressOffset>0x18</addressOffset>
          <fields>
            <field>
              <name>NBT</name>
              <bitRange>[7:0]</bitRange>
            </field>
            <field>
              <name>NDTL</name>
              <bitRange>[31:16]</bitRange>
            </field>
          </fields>
        </register>
        <register>
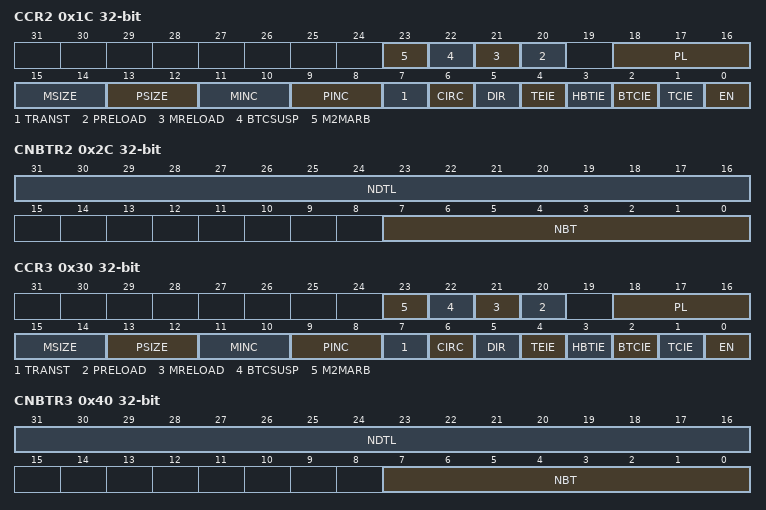
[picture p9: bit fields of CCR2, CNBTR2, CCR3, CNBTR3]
          <name>CCR2</name>
          <addressOffset>0x1C</addressOffset>
          <fields>
            <field>
              <name>EN</name>
              <bitRange>[0:0]</bitRange>
            </field>
            <field>
              <name>TCIE</name>
              <bitRange>[1:1]</bitRange>
            </field>
            <field>
              <name>BTCIE</name>
              <bitRange>[2:2]</bitRange>
            </field>
            <field>
              <name>HBTIE</name>
              <bitRange>[3:3]</bitRange>
            </field>
            <field>
              <name>TEIE</name>
              <bitRange>[4:4]</bitRange>
            </field>
            <field>
              <name>DIR</name>
              <bitRange>[5:5]</bitRange>
            </field>
            <field>
              <name>CIRC</name>
              <bitRange>[6:6]</bitRange>
            </field>
            <field>
              <name>TRANST</name>
              <bitRange>[7:7]</bitRange>
            </field>
            <field>
              <name>PINC</name>
              <bitRange>[9:8]</bitRange>
            </field>
            <field>
              <name>MINC</name>
              <bitRange>[11:10]</bitRange>
            </field>
            <field>
              <name>PSIZE</name>
              <bitRange>[13:12]</bitRange>
            </field>
            <field>
              <name>MSIZE</name>
              <bitRange>[15:14]</bitRange>
            </field>
            <field>
              <name>PL</name>
              <bitRange>[18:16]</bitRange>
            </field>
            <field>
              <name>PRELOAD</name>
              <bitRange>[20:20]</bitRange>
            </field>
            <field>
              <name>MRELOAD</name>
              <bitRange>[21:21]</bitRange>
            </field>
            <field>
              <name>BTCSUSP</name>
              <bitRange>[22:22]</bitRange>
            </field>
            <field>
              <name>M2MARB</name>
              <bitRange>[23:23]</bitRange>
            </field>
          </fields>
        </register>
        <register>
          <name>CNDTR2</name>
          <addressOffset>0x20</addressOffset>
          <fields>
            <field>
              <name>NDT</name>
              <bitRange>[15:0]</bitRange>
            </field>
          </fields>
        </register>
        <register>
          <name>CPAR2</name>
          <addressOffset>0x24</addressOffset>
          <fields>
            <field>
              <name>PA</name>
              <bitRange>[31:0]</bitRange>
            </field>
          </fields>
        </register>
        <register>
          <name>CMAR2</name>
          <addressOffset>0x28</addressOffset>
          <fields>
            <field>
              <name>MA</name>
              <bitRange>[31:0]</bitRange>
            </field>
          </fields>
        </register>
        <register>
          <name>CNBTR2</name>
          <addressOffset>0x2C</addressOffset>
          <fields>
            <field>
              <name>NBT</name>
              <bitRange>[7:0]</bitRange>
            </field>
            <field>
              <name>NDTL</name>
              <bitRange>[31:16]</bitRange>
            </field>
          </fields>
        </register>
        <register>
          <name>CCR3</name>
          <addressOffset>0x30</addressOffset>
          <fields>
            <field>
              <name>EN</name>
              <bitRange>[0:0]</bitRange>
            </field>
            <field>
              <name>TCIE</name>
              <bitRange>[1:1]</bitRange>
            </field>
            <field>
              <name>BTCIE</name>
              <bitRange>[2:2]</bitRange>
            </field>
            <field>
              <name>HBTIE</name>
              <bitRange>[3:3]</bitRange>
            </field>
            <field>
              <name>TEIE</name>
              <bitRange>[4:4]</bitRange>
            </field>
            <field>
              <name>DIR</name>
              <bitRange>[5:5]</bitRange>
            </field>
            <field>
              <name>CIRC</name>
              <bitRange>[6:6]</bitRange>
            </field>
            <field>
              <name>TRANST</name>
              <bitRange>[7:7]</bitRange>
            </field>
            <field>
              <name>PINC</name>
              <bitRange>[9:8]</bitRange>
            </field>
            <field>
              <name>MINC</name>
              <bitRange>[11:10]</bitRange>
            </field>
            <field>
              <name>PSIZE</name>
              <bitRange>[13:12]</bitRange>
            </field>
            <field>
              <name>MSIZE</name>
              <bitRange>[15:14]</bitRange>
            </field>
            <field>
              <name>PL</name>
              <bitRange>[18:16]</bitRange>
            </field>
            <field>
              <name>PRELOAD</name>
              <bitRange>[20:20]</bitRange>
            </field>
            <field>
              <name>MRELOAD</name>
              <bitRange>[21:21]</bitRange>
            </field>
            <field>
              <name>BTCSUSP</name>
              <bitRange>[22:22]</bitRange>
            </field>
            <field>
              <name>M2MARB</name>
              <bitRange>[23:23]</bitRange>
            </field>
          </fields>
        </register>
        <register>
          <name>CNDTR3</name>
          <addressOffset>0x34</addressOffset>
          <fields>
            <field>
              <name>NDT</name>
              <bitRange>[15:0]</bitRange>
            </field>
          </fields>
        </register>
        <register>
          <name>CPAR3</name>
          <addressOffset>0x38</addressOffset>
          <fields>
            <field>
              <name>PA</name>
              <bitRange>[31:0]</bitRange>
            </field>
          </fields>
        </register>
        <register>
          <name>CMAR3</name>
          <addressOffset>0x3C</addressOffset>
          <fields>
            <field>
              <name>MA</name>
              <bitRange>[31:0]</bitRange>
            </field>
          </fields>
        </register>
        <register>
          <name>CNBTR3</name>
          <addressOffset>0x40</addressOffset>
          <fields>
            <field>
              <name>NBT</name>
              <bitRange>[7:0]</bitRange>
            </field>
            <field>
              <name>NDTL</name>
              <bitRange>[31:16]</bitRange>
            </field>
          </fields>
        </register>
        <register>
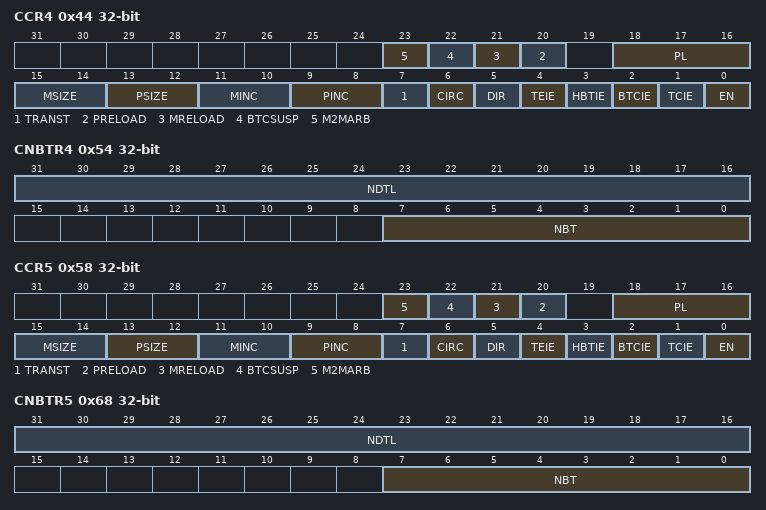
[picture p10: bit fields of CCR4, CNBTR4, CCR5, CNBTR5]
          <name>CCR4</name>
          <addressOffset>0x44</addressOffset>
          <fields>
            <field>
              <name>EN</name>
              <bitRange>[0:0]</bitRange>
            </field>
            <field>
              <name>TCIE</name>
              <bitRange>[1:1]</bitRange>
            </field>
            <field>
              <name>BTCIE</name>
              <bitRange>[2:2]</bitRange>
            </field>
            <field>
              <name>HBTIE</name>
              <bitRange>[3:3]</bitRange>
            </field>
            <field>
              <name>TEIE</name>
              <bitRange>[4:4]</bitRange>
            </field>
            <field>
              <name>DIR</name>
              <bitRange>[5:5]</bitRange>
            </field>
            <field>
              <name>CIRC</name>
              <bitRange>[6:6]</bitRange>
            </field>
            <field>
              <name>TRANST</name>
              <bitRange>[7:7]</bitRange>
            </field>
            <field>
              <name>PINC</name>
              <bitRange>[9:8]</bitRange>
            </field>
            <field>
              <name>MINC</name>
              <bitRange>[11:10]</bitRange>
            </field>
            <field>
              <name>PSIZE</name>
              <bitRange>[13:12]</bitRange>
            </field>
            <field>
              <name>MSIZE</name>
              <bitRange>[15:14]</bitRange>
            </field>
            <field>
              <name>PL</name>
              <bitRange>[18:16]</bitRange>
            </field>
            <field>
              <name>PRELOAD</name>
              <bitRange>[20:20]</bitRange>
            </field>
            <field>
              <name>MRELOAD</name>
              <bitRange>[21:21]</bitRange>
            </field>
            <field>
              <name>BTCSUSP</name>
              <bitRange>[22:22]</bitRange>
            </field>
            <field>
              <name>M2MARB</name>
              <bitRange>[23:23]</bitRange>
            </field>
          </fields>
        </register>
        <register>
          <name>CNDTR4</name>
          <addressOffset>0x48</addressOffset>
          <fields>
            <field>
              <name>NDT</name>
              <bitRange>[15:0]</bitRange>
            </field>
          </fields>
        </register>
        <register>
          <name>CPAR4</name>
          <addressOffset>0x4C</addressOffset>
          <fields>
            <field>
              <name>PA</name>
              <bitRange>[31:0]</bitRange>
            </field>
          </fields>
        </register>
        <register>
          <name>CMAR4</name>
          <addressOffset>0x50</addressOffset>
          <fields>
            <field>
              <name>MA</name>
              <bitRange>[31:0]</bitRange>
            </field>
          </fields>
        </register>
        <register>
          <name>CNBTR4</name>
          <addressOffset>0x54</addressOffset>
          <fields>
            <field>
              <name>NBT</name>
              <bitRange>[7:0]</bitRange>
            </field>
            <field>
              <name>NDTL</name>
              <bitRange>[31:16]</bitRange>
            </field>
          </fields>
        </register>
        <register>
          <name>CCR5</name>
          <addressOffset>0x58</addressOffset>
          <fields>
            <field>
              <name>EN</name>
              <bitRange>[0:0]</bitRange>
            </field>
            <field>
              <name>TCIE</name>
              <bitRange>[1:1]</bitRange>
            </field>
            <field>
              <name>BTCIE</name>
              <bitRange>[2:2]</bitRange>
            </field>
            <field>
              <name>HBTIE</name>
              <bitRange>[3:3]</bitRange>
            </field>
            <field>
              <name>TEIE</name>
              <bitRange>[4:4]</bitRange>
            </field>
            <field>
              <name>DIR</name>
              <bitRange>[5:5]</bitRange>
            </field>
            <field>
              <name>CIRC</name>
              <bitRange>[6:6]</bitRange>
            </field>
            <field>
              <name>TRANST</name>
              <bitRange>[7:7]</bitRange>
            </field>
            <field>
              <name>PINC</name>
              <bitRange>[9:8]</bitRange>
            </field>
            <field>
              <name>MINC</name>
              <bitRange>[11:10]</bitRange>
            </field>
            <field>
              <name>PSIZE</name>
              <bitRange>[13:12]</bitRange>
            </field>
            <field>
              <name>MSIZE</name>
              <bitRange>[15:14]</bitRange>
            </field>
            <field>
              <name>PL</name>
              <bitRange>[18:16]</bitRange>
            </field>
            <field>
              <name>PRELOAD</name>
              <bitRange>[20:20]</bitRange>
            </field>
            <field>
              <name>MRELOAD</name>
              <bitRange>[21:21]</bitRange>
            </field>
            <field>
              <name>BTCSUSP</name>
              <bitRange>[22:22]</bitRange>
            </field>
            <field>
              <name>M2MARB</name>
              <bitRange>[23:23]</bitRange>
            </field>
          </fields>
        </register>
        <register>
          <name>CNDTR5</name>
          <addressOffset>0x5C</addressOffset>
          <fields>
            <field>
              <name>NDT</name>
              <bitRange>[15:0]</bitRange>
            </field>
          </fields>
        </register>
        <register>
          <name>CPAR5</name>
          <addressOffset>0x60</addressOffset>
          <fields>
            <field>
              <name>PA</name>
              <bitRange>[31:0]</bitRange>
            </field>
          </fields>
        </register>
        <register>
          <name>CMAR5</name>
          <addressOffset>0x64</addressOffset>
          <fields>
            <field>
              <name>MA</name>
              <bitRange>[31:0]</bitRange>
            </field>
          </fields>
        </register>
        <register>
          <name>CNBTR5</name>
          <addressOffset>0x68</addressOffset>
          <fields>
            <field>
              <name>NBT</name>
              <bitRange>[7:0]</bitRange>
            </field>
            <field>
              <name>NDTL</name>
              <bitRange>[31:16]</bitRange>
            </field>
          </fields>
        </register>
        <register>
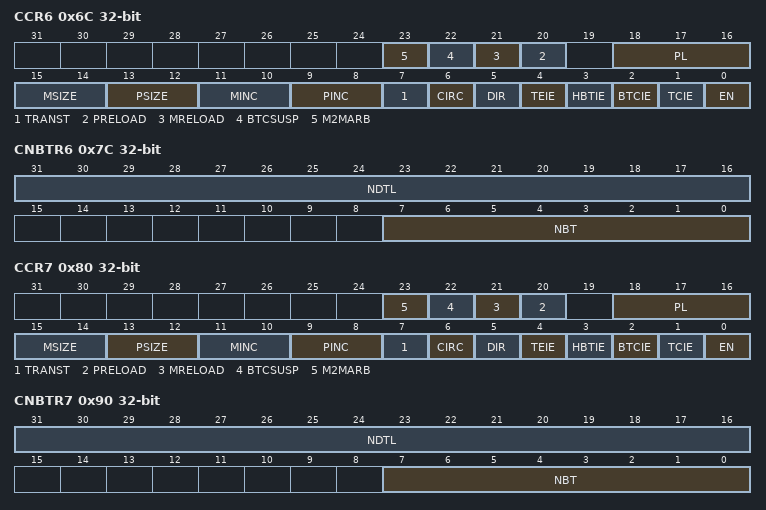
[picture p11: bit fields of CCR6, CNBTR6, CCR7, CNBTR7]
          <name>CCR6</name>
          <addressOffset>0x6C</addressOffset>
          <fields>
            <field>
              <name>EN</name>
              <bitRange>[0:0]</bitRange>
            </field>
            <field>
              <name>TCIE</name>
              <bitRange>[1:1]</bitRange>
            </field>
            <field>
              <name>BTCIE</name>
              <bitRange>[2:2]</bitRange>
            </field>
            <field>
              <name>HBTIE</name>
              <bitRange>[3:3]</bitRange>
            </field>
            <field>
              <name>TEIE</name>
              <bitRange>[4:4]</bitRange>
            </field>
            <field>
              <name>DIR</name>
              <bitRange>[5:5]</bitRange>
            </field>
            <field>
              <name>CIRC</name>
              <bitRange>[6:6]</bitRange>
            </field>
            <field>
              <name>TRANST</name>
              <bitRange>[7:7]</bitRange>
            </field>
            <field>
              <name>PINC</name>
              <bitRange>[9:8]</bitRange>
            </field>
            <field>
              <name>MINC</name>
              <bitRange>[11:10]</bitRange>
            </field>
            <field>
              <name>PSIZE</name>
              <bitRange>[13:12]</bitRange>
            </field>
            <field>
              <name>MSIZE</name>
              <bitRange>[15:14]</bitRange>
            </field>
            <field>
              <name>PL</name>
              <bitRange>[18:16]</bitRange>
            </field>
            <field>
              <name>PRELOAD</name>
              <bitRange>[20:20]</bitRange>
            </field>
            <field>
              <name>MRELOAD</name>
              <bitRange>[21:21]</bitRange>
            </field>
            <field>
              <name>BTCSUSP</name>
              <bitRange>[22:22]</bitRange>
            </field>
            <field>
              <name>M2MARB</name>
              <bitRange>[23:23]</bitRange>
            </field>
          </fields>
        </register>
        <register>
          <name>CNDTR6</name>
          <addressOffset>0x70</addressOffset>
          <fields>
            <field>
              <name>NDT</name>
              <bitRange>[15:0]</bitRange>
            </field>
          </fields>
        </register>
        <register>
          <name>CPAR6</name>
          <addressOffset>0x74</addressOffset>
          <fields>
            <field>
              <name>PA</name>
              <bitRange>[31:0]</bitRange>
            </field>
          </fields>
        </register>
        <register>
          <name>CMAR6</name>
          <addressOffset>0x78</addressOffset>
          <fields>
            <field>
              <name>MA</name>
              <bitRange>[31:0]</bitRange>
            </field>
          </fields>
        </register>
        <register>
          <name>CNBTR6</name>
          <addressOffset>0x7C</addressOffset>
          <fields>
            <field>
              <name>NBT</name>
              <bitRange>[7:0]</bitRange>
            </field>
            <field>
              <name>NDTL</name>
              <bitRange>[31:16]</bitRange>
            </field>
          </fields>
        </register>
        <register>
          <name>CCR7</name>
          <addressOffset>0x80</addressOffset>
          <fields>
            <field>
              <name>EN</name>
              <bitRange>[0:0]</bitRange>
            </field>
            <field>
              <name>TCIE</name>
              <bitRange>[1:1]</bitRange>
            </field>
            <field>
              <name>BTCIE</name>
              <bitRange>[2:2]</bitRange>
            </field>
            <field>
              <name>HBTIE</name>
              <bitRange>[3:3]</bitRange>
            </field>
            <field>
              <name>TEIE</name>
              <bitRange>[4:4]</bitRange>
            </field>
            <field>
              <name>DIR</name>
              <bitRange>[5:5]</bitRange>
            </field>
            <field>
              <name>CIRC</name>
              <bitRange>[6:6]</bitRange>
            </field>
            <field>
              <name>TRANST</name>
              <bitRange>[7:7]</bitRange>
            </field>
            <field>
              <name>PINC</name>
              <bitRange>[9:8]</bitRange>
            </field>
            <field>
              <name>MINC</name>
              <bitRange>[11:10]</bitRange>
            </field>
            <field>
              <name>PSIZE</name>
              <bitRange>[13:12]</bitRange>
            </field>
            <field>
              <name>MSIZE</name>
              <bitRange>[15:14]</bitRange>
            </field>
            <field>
              <name>PL</name>
              <bitRange>[18:16]</bitRange>
            </field>
            <field>
              <name>PRELOAD</name>
              <bitRange>[20:20]</bitRange>
            </field>
            <field>
              <name>MRELOAD</name>
              <bitRange>[21:21]</bitRange>
            </field>
            <field>
              <name>BTCSUSP</name>
              <bitRange>[22:22]</bitRange>
            </field>
            <field>
              <name>M2MARB</name>
              <bitRange>[23:23]</bitRange>
            </field>
          </fields>
        </register>
        <register>
          <name>CNDTR7</name>
          <addressOffset>0x84</addressOffset>
          <fields>
            <field>
              <name>NDT</name>
              <bitRange>[15:0]</bitRange>
            </field>
          </fields>
        </register>
        <register>
          <name>CPAR7</name>
          <addressOffset>0x88</addressOffset>
          <fields>
            <field>
              <name>PA</name>
              <bitRange>[31:0]</bitRange>
            </field>
          </fields>
        </register>
        <register>
          <name>CMAR7</name>
          <addressOffset>0x8C</addressOffset>
          <fields>
            <field>
              <name>MA</name>
              <bitRange>[31:0]</bitRange>
            </field>
          </fields>
        </register>
        <register>
          <name>CNBTR7</name>
          <addressOffset>0x90</addressOffset>
          <fields>
            <field>
              <name>NBT</name>
              <bitRange>[7:0]</bitRange>
            </field>
            <field>
              <name>NDTL</name>
              <bitRange>[31:16]</bitRange>
            </field>
          </fields>
        </register>
        <register>
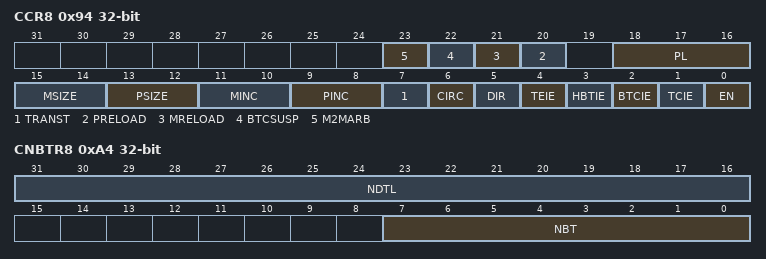
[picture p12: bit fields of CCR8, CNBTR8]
          <name>CCR8</name>
          <addressOffset>0x94</addressOffset>
          <fields>
            <field>
              <name>EN</name>
              <bitRange>[0:0]</bitRange>
            </field>
            <field>
              <name>TCIE</name>
              <bitRange>[1:1]</bitRange>
            </field>
            <field>
              <name>BTCIE</name>
              <bitRange>[2:2]</bitRange>
            </field>
            <field>
              <name>HBTIE</name>
              <bitRange>[3:3]</bitRange>
            </field>
            <field>
              <name>TEIE</name>
              <bitRange>[4:4]</bitRange>
            </field>
            <field>
              <name>DIR</name>
              <bitRange>[5:5]</bitRange>
            </field>
            <field>
              <name>CIRC</name>
              <bitRange>[6:6]</bitRange>
            </field>
            <field>
              <name>TRANST</name>
              <bitRange>[7:7]</bitRange>
            </field>
            <field>
              <name>PINC</name>
              <bitRange>[9:8]</bitRange>
            </field>
            <field>
              <name>MINC</name>
              <bitRange>[11:10]</bitRange>
            </field>
            <field>
              <name>PSIZE</name>
              <bitRange>[13:12]</bitRange>
            </field>
            <field>
              <name>MSIZE</name>
              <bitRange>[15:14]</bitRange>
            </field>
            <field>
              <name>PL</name>
              <bitRange>[18:16]</bitRange>
            </field>
            <field>
              <name>PRELOAD</name>
              <bitRange>[20:20]</bitRange>
            </field>
            <field>
              <name>MRELOAD</name>
              <bitRange>[21:21]</bitRange>
            </field>
            <field>
              <name>BTCSUSP</name>
              <bitRange>[22:22]</bitRange>
            </field>
            <field>
              <name>M2MARB</name>
              <bitRange>[23:23]</bitRange>
            </field>
          </fields>
        </register>
        <register>
          <name>CNDTR8</name>
          <addressOffset>0x98</addressOffset>
          <fields>
            <field>
              <name>NDT</name>
              <bitRange>[15:0]</bitRange>
            </field>
          </fields>
        </register>
        <register>
          <name>CPAR8</name>
          <addressOffset>0x9C</addressOffset>
          <fields>
            <field>
              <name>PA</name>
              <bitRange>[31:0]</bitRange>
            </field>
          </fields>
        </register>
        <register>
          <name>CMAR8</name>
          <addressOffset>0xA0</addressOffset>
          <fields>
            <field>
              <name>MA</name>
              <bitRange>[31:0]</bitRange>
            </field>
          </fields>
        </register>
        <register>
          <name>CNBTR8</name>
          <addressOffset>0xA4</addressOffset>
          <fields>
            <field>
              <name>NBT</name>
              <bitRange>[7:0]</bitRange>
            </field>
            <field>
              <name>NDTL</name>
              <bitRange>[31:16]</bitRange>
            </field>
          </fields>
        </register>
      </registers>
    </peripheral>
    <peripheral>
      <name>EXTI</name>
      <baseAddress>0x40010400</baseAddress>
      <addressBlock>
        <offset>0x0</offset>
        <size>0x20</size>
        <usage>registers</usage>
      </addressBlock>
      <interrupt>
        <name>PVD</name>
        <description>PVD through EXTI Line detection Interrupt</description>
        <value>1</value>
      </interrupt>
      <interrupt>
        <name>EXTI0</name>
        <description>EXTI Line0 interrupt</description>
        <value>6</value>
      </interrupt>
      <interrupt>
        <name>EXTI1</name>
        <description>EXTI Line1 interrupt</description>
        <value>7</value>
      </interrupt>
      <interrupt>
        <name>EXTI2</name>
        <description>EXTI Line2 interrupt</description>
        <value>8</value>
      </interrupt>
      <interrupt>
        <name>EXTI3</name>
        <description>EXTI Line3 interrupt</description>
        <value>9</value>
      </interrupt>
      <interrupt>
        <name>EXTI4</name>
        <description>EXTI Line4 interrupt</description>
        <value>10</value>
      </interrupt>
      <registers>
        <register>
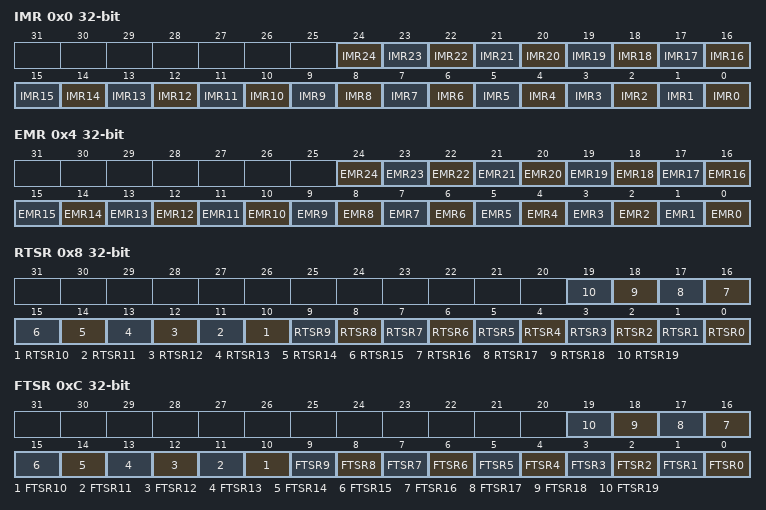
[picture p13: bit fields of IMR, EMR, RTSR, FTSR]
          <name>IMR</name>
          <addressOffset>0x0</addressOffset>
          <fields>
            <field>
              <name>IMR0</name>
              <bitRange>[0:0]</bitRange>
            </field>
            <field>
              <name>IMR1</name>
              <bitRange>[1:1]</bitRange>
            </field>
            <field>
              <name>IMR2</name>
              <bitRange>[2:2]</bitRange>
            </field>
            <field>
              <name>IMR3</name>
              <bitRange>[3:3]</bitRange>
            </field>
            <field>
              <name>IMR4</name>
              <bitRange>[4:4]</bitRange>
            </field>
            <field>
              <name>IMR5</name>
              <bitRange>[5:5]</bitRange>
            </field>
            <field>
              <name>IMR6</name>
              <bitRange>[6:6]</bitRange>
            </field>
            <field>
              <name>IMR7</name>
              <bitRange>[7:7]</bitRange>
            </field>
            <field>
              <name>IMR8</name>
              <bitRange>[8:8]</bitRange>
            </field>
            <field>
              <name>IMR9</name>
              <bitRange>[9:9]</bitRange>
            </field>
            <field>
              <name>IMR10</name>
              <bitRange>[10:10]</bitRange>
            </field>
            <field>
              <name>IMR11</name>
              <bitRange>[11:11]</bitRange>
            </field>
            <field>
              <name>IMR12</name>
              <bitRange>[12:12]</bitRange>
            </field>
            <field>
              <name>IMR13</name>
              <bitRange>[13:13]</bitRange>
            </field>
            <field>
              <name>IMR14</name>
              <bitRange>[14:14]</bitRange>
            </field>
            <field>
              <name>IMR15</name>
              <bitRange>[15:15]</bitRange>
            </field>
            <field>
              <name>IMR16</name>
              <bitRange>[16:16]</bitRange>
            </field>
            <field>
              <name>IMR17</name>
              <bitRange>[17:17]</bitRange>
            </field>
            <field>
              <name>IMR18</name>
              <bitRange>[18:18]</bitRange>
            </field>
            <field>
              <name>IMR19</name>
              <bitRange>[19:19]</bitRange>
            </field>
            <field>
              <name>IMR20</name>
              <bitRange>[20:20]</bitRange>
            </field>
            <field>
              <name>IMR21</name>
              <bitRange>[21:21]</bitRange>
            </field>
            <field>
              <name>IMR22</name>
              <bitRange>[22:22]</bitRange>
            </field>
            <field>
              <name>IMR23</name>
              <bitRange>[23:23]</bitRange>
            </field>
            <field>
              <name>IMR24</name>
              <bitRange>[24:24]</bitRange>
            </field>
          </fields>
        </register>
        <register>
          <name>EMR</name>
          <addressOffset>0x4</addressOffset>
          <fields>
            <field>
              <name>EMR0</name>
              <bitRange>[0:0]</bitRange>
            </field>
            <field>
              <name>EMR1</name>
              <bitRange>[1:1]</bitRange>
            </field>
            <field>
              <name>EMR2</name>
              <bitRange>[2:2]</bitRange>
            </field>
            <field>
              <name>EMR3</name>
              <bitRange>[3:3]</bitRange>
            </field>
            <field>
              <name>EMR4</name>
              <bitRange>[4:4]</bitRange>
            </field>
            <field>
              <name>EMR5</name>
              <bitRange>[5:5]</bitRange>
            </field>
            <field>
              <name>EMR6</name>
              <bitRange>[6:6]</bitRange>
            </field>
            <field>
              <name>EMR7</name>
              <bitRange>[7:7]</bitRange>
            </field>
            <field>
              <name>EMR8</name>
              <bitRange>[8:8]</bitRange>
            </field>
            <field>
              <name>EMR9</name>
              <bitRange>[9:9]</bitRange>
            </field>
            <field>
              <name>EMR10</name>
              <bitRange>[10:10]</bitRange>
            </field>
            <field>
              <name>EMR11</name>
              <bitRange>[11:11]</bitRange>
            </field>
            <field>
              <name>EMR12</name>
              <bitRange>[12:12]</bitRange>
            </field>
            <field>
              <name>EMR13</name>
              <bitRange>[13:13]</bitRange>
            </field>
            <field>
              <name>EMR14</name>
              <bitRange>[14:14]</bitRange>
            </field>
            <field>
              <name>EMR15</name>
              <bitRange>[15:15]</bitRange>
            </field>
            <field>
              <name>EMR16</name>
              <bitRange>[16:16]</bitRange>
            </field>
            <field>
              <name>EMR17</name>
              <bitRange>[17:17]</bitRange>
            </field>
            <field>
              <name>EMR18</name>
              <bitRange>[18:18]</bitRange>
            </field>
            <field>
              <name>EMR19</name>
              <bitRange>[19:19]</bitRange>
            </field>
            <field>
              <name>EMR20</name>
              <bitRange>[20:20]</bitRange>
            </field>
            <field>
              <name>EMR21</name>
              <bitRange>[21:21]</bitRange>
            </field>
            <field>
              <name>EMR22</name>
              <bitRange>[22:22]</bitRange>
            </field>
            <field>
              <name>EMR23</name>
              <bitRange>[23:23]</bitRange>
            </field>
            <field>
              <name>EMR24</name>
              <bitRange>[24:24]</bitRange>
            </field>
          </fields>
        </register>
        <register>
          <name>RTSR</name>
          <addressOffset>0x8</addressOffset>
          <fields>
            <field>
              <name>RTSR0</name>
              <bitRange>[0:0]</bitRange>
            </field>
            <field>
              <name>RTSR1</name>
              <bitRange>[1:1]</bitRange>
            </field>
            <field>
              <name>RTSR2</name>
              <bitRange>[2:2]</bitRange>
            </field>
            <field>
              <name>RTSR3</name>
              <bitRange>[3:3]</bitRange>
            </field>
            <field>
              <name>RTSR4</name>
              <bitRange>[4:4]</bitRange>
            </field>
            <field>
              <name>RTSR5</name>
              <bitRange>[5:5]</bitRange>
            </field>
            <field>
              <name>RTSR6</name>
              <bitRange>[6:6]</bitRange>
            </field>
            <field>
              <name>RTSR7</name>
              <bitRange>[7:7]</bitRange>
            </field>
            <field>
              <name>RTSR8</name>
              <bitRange>[8:8]</bitRange>
            </field>
            <field>
              <name>RTSR9</name>
              <bitRange>[9:9]</bitRange>
            </field>
            <field>
              <name>RTSR10</name>
              <bitRange>[10:10]</bitRange>
            </field>
            <field>
              <name>RTSR11</name>
              <bitRange>[11:11]</bitRange>
            </field>
            <field>
              <name>RTSR12</name>
              <bitRange>[12:12]</bitRange>
            </field>
            <field>
              <name>RTSR13</name>
              <bitRange>[13:13]</bitRange>
            </field>
            <field>
              <name>RTSR14</name>
              <bitRange>[14:14]</bitRange>
            </field>
            <field>
              <name>RTSR15</name>
              <bitRange>[15:15]</bitRange>
            </field>
            <field>
              <name>RTSR16</name>
              <bitRange>[16:16]</bitRange>
            </field>
            <field>
              <name>RTSR17</name>
              <bitRange>[17:17]</bitRange>
            </field>
            <field>
              <name>RTSR18</name>
              <bitRange>[18:18]</bitRange>
            </field>
            <field>
              <name>RTSR19</name>
              <bitRange>[19:19]</bitRange>
            </field>
          </fields>
        </register>
        <register>
          <name>FTSR</name>
          <addressOffset>0xC</addressOffset>
          <fields>
            <field>
              <name>FTSR0</name>
              <bitRange>[0:0]</bitRange>
            </field>
            <field>
              <name>FTSR1</name>
              <bitRange>[1:1]</bitRange>
            </field>
            <field>
              <name>FTSR2</name>
              <bitRange>[2:2]</bitRange>
            </field>
            <field>
              <name>FTSR3</name>
              <bitRange>[3:3]</bitRange>
            </field>
            <field>
              <name>FTSR4</name>
              <bitRange>[4:4]</bitRange>
            </field>
            <field>
              <name>FTSR5</name>
              <bitRange>[5:5]</bitRange>
            </field>
            <field>
              <name>FTSR6</name>
              <bitRange>[6:6]</bitRange>
            </field>
            <field>
              <name>FTSR7</name>
              <bitRange>[7:7]</bitRange>
            </field>
            <field>
              <name>FTSR8</name>
              <bitRange>[8:8]</bitRange>
            </field>
            <field>
              <name>FTSR9</name>
              <bitRange>[9:9]</bitRange>
            </field>
            <field>
              <name>FTSR10</name>
              <bitRange>[10:10]</bitRange>
            </field>
            <field>
              <name>FTSR11</name>
              <bitRange>[11:11]</bitRange>
            </field>
            <field>
              <name>FTSR12</name>
              <bitRange>[12:12]</bitRange>
            </field>
            <field>
              <name>FTSR13</name>
              <bitRange>[13:13]</bitRange>
            </field>
            <field>
              <name>FTSR14</name>
              <bitRange>[14:14]</bitRange>
            </field>
            <field>
              <name>FTSR15</name>
              <bitRange>[15:15]</bitRange>
            </field>
            <field>
              <name>FTSR16</name>
              <bitRange>[16:16]</bitRange>
            </field>
            <field>
              <name>FTSR17</name>
              <bitRange>[17:17]</bitRange>
            </field>
            <field>
              <name>FTSR18</name>
              <bitRange>[18:18]</bitRange>
            </field>
            <field>
              <name>FTSR19</name>
              <bitRange>[19:19]</bitRange>
            </field>
          </fields>
        </register>
        <register>
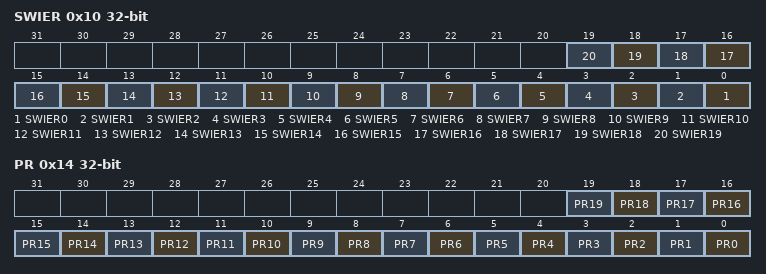
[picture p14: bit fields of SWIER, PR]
          <name>SWIER</name>
          <addressOffset>0x10</addressOffset>
          <fields>
            <field>
              <name>SWIER0</name>
              <bitRange>[0:0]</bitRange>
            </field>
            <field>
              <name>SWIER1</name>
              <bitRange>[1:1]</bitRange>
            </field>
            <field>
              <name>SWIER2</name>
              <bitRange>[2:2]</bitRange>
            </field>
            <field>
              <name>SWIER3</name>
              <bitRange>[3:3]</bitRange>
            </field>
            <field>
              <name>SWIER4</name>
              <bitRange>[4:4]</bitRange>
            </field>
            <field>
              <name>SWIER5</name>
              <bitRange>[5:5]</bitRange>
            </field>
            <field>
              <name>SWIER6</name>
              <bitRange>[6:6]</bitRange>
            </field>
            <field>
              <name>SWIER7</name>
              <bitRange>[7:7]</bitRange>
            </field>
            <field>
              <name>SWIER8</name>
              <bitRange>[8:8]</bitRange>
            </field>
            <field>
              <name>SWIER9</name>
              <bitRange>[9:9]</bitRange>
            </field>
            <field>
              <name>SWIER10</name>
              <bitRange>[10:10]</bitRange>
            </field>
            <field>
              <name>SWIER11</name>
              <bitRange>[11:11]</bitRange>
            </field>
            <field>
              <name>SWIER12</name>
              <bitRange>[12:12]</bitRange>
            </field>
            <field>
              <name>SWIER13</name>
              <bitRange>[13:13]</bitRange>
            </field>
            <field>
              <name>SWIER14</name>
              <bitRange>[14:14]</bitRange>
            </field>
            <field>
              <name>SWIER15</name>
              <bitRange>[15:15]</bitRange>
            </field>
            <field>
              <name>SWIER16</name>
              <bitRange>[16:16]</bitRange>
            </field>
            <field>
              <name>SWIER17</name>
              <bitRange>[17:17]</bitRange>
            </field>
            <field>
              <name>SWIER18</name>
              <bitRange>[18:18]</bitRange>
            </field>
            <field>
              <name>SWIER19</name>
              <bitRange>[19:19]</bitRange>
            </field>
          </fields>
        </register>
        <register>
          <name>PR</name>
          <addressOffset>0x14</addressOffset>
          <fields>
            <field>
              <name>PR0</name>
              <bitRange>[0:0]</bitRange>
            </field>
            <field>
              <name>PR1</name>
              <bitRange>[1:1]</bitRange>
            </field>
            <field>
              <name>PR2</name>
              <bitRange>[2:2]</bitRange>
            </field>
            <field>
              <name>PR3</name>
              <bitRange>[3:3]</bitRange>
            </field>
            <field>
              <name>PR4</name>
              <bitRange>[4:4]</bitRange>
            </field>
            <field>
              <name>PR5</name>
              <bitRange>[5:5]</bitRange>
            </field>
            <field>
              <name>PR6</name>
              <bitRange>[6:6]</bitRange>
            </field>
            <field>
              <name>PR7</name>
              <bitRange>[7:7]</bitRange>
            </field>
            <field>
              <name>PR8</name>
              <bitRange>[8:8]</bitRange>
            </field>
            <field>
              <name>PR9</name>
              <bitRange>[9:9]</bitRange>
            </field>
            <field>
              <name>PR10</name>
              <bitRange>[10:10]</bitRange>
            </field>
            <field>
              <name>PR11</name>
              <bitRange>[11:11]</bitRange>
            </field>
            <field>
              <name>PR12</name>
              <bitRange>[12:12]</bitRange>
            </field>
            <field>
              <name>PR13</name>
              <bitRange>[13:13]</bitRange>
            </field>
            <field>
              <name>PR14</name>
              <bitRange>[14:14]</bitRange>
            </field>
            <field>
              <name>PR15</name>
              <bitRange>[15:15]</bitRange>
            </field>
            <field>
              <name>PR16</name>
              <bitRange>[16:16]</bitRange>
            </field>
            <field>
              <name>PR17</name>
              <bitRange>[17:17]</bitRange>
            </field>
            <field>
              <name>PR18</name>
              <bitRange>[18:18]</bitRange>
            </field>
            <field>
              <name>PR19</name>
              <bitRange>[19:19]</bitRange>
            </field>
          </fields>
        </register>
      </registers>
    </peripheral>
    <peripheral>
      <name>FLASH</name>
      <baseAddress>0x40022000</baseAddress>
      <addressBlock>
        <offset>0x0</offset>
        <size>0x50</size>
        <usage>registers</usage>
      </addressBlock>
      <interrupt>
        <name>FLASH</name>
        <description>FLASH global Interrupt</description>
        <value>4</value>
      </interrupt>     
      <registers>
        <register>
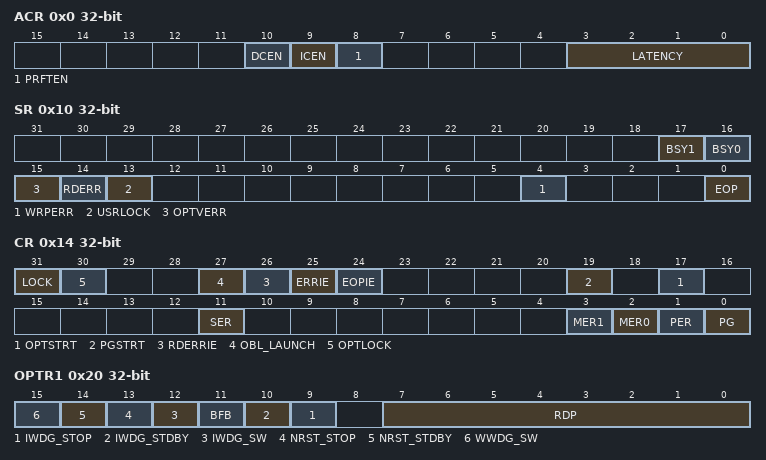
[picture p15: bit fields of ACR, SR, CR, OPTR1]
          <name>ACR</name>
          <addressOffset>0x0</addressOffset>
          <fields>
            <field>
              <name>LATENCY</name>
              <description>Latency</description>
              <bitRange>[3:0]</bitRange>
            </field>
            <field>
              <name>PRFTEN</name>
              <bitRange>[8:8]</bitRange>
            </field>
            <field>
              <name>ICEN</name>
              <bitRange>[9:9]</bitRange>
            </field>
            <field>
              <name>DCEN</name>
              <bitRange>[10:10]</bitRange>
            </field>
          </fields>
        </register>
        <register>
          <name>KEYR</name>
          <addressOffset>0x8</addressOffset>
          <fields>
            <field>
              <name>KEY</name>
              <description>Flash CR key</description>
              <bitRange>[31:0]</bitRange>
            </field>
          </fields>
        </register>
        <register>
          <name>OPTKEYR</name>
          <addressOffset>0xC</addressOffset>
          <fields>
            <field>
              <name>OPTKEY</name>
              <description>Flash Option key</description>
              <bitRange>[31:0]</bitRange>
            </field>
          </fields>
        </register>
        <register>
          <name>SR</name>
          <addressOffset>0x10</addressOffset>
          <fields>
            <field>
              <name>EOP</name>
              <description>End of operation</description>
              <bitRange>[0:0]</bitRange>
            </field>
            <field>
              <name>WRPERR</name>
              <description>Write protection error</description>
              <bitRange>[4:4]</bitRange>
            </field>
            <field>
              <name>USRLOCK</name>
              <description>Userdata Lock</description>
              <bitRange>[13:13]</bitRange>
              <access>read-only</access>
            </field>
            <field>
              <name>RDERR</name>
              <bitRange>[14:14]</bitRange>
            </field>
            <field>
              <name>OPTVERR</name>
              <description>Option and trimming bits loading validity error</description>
              <bitRange>[15:15]</bitRange>
            </field>
            <field>
              <name>BSY0</name>
              <description>Bank0 Busy</description>
              <bitRange>[16:16]</bitRange>
              <access>read-only</access>
            </field>
            <field>
              <name>BSY1</name>
              <description>Bank1 Busy</description>
              <bitRange>[17:17]</bitRange>
              <access>read-only</access>
            </field>
          </fields>
        </register>
        <register>
          <name>CR</name>
          <addressOffset>0x14</addressOffset>
          <fields>
            <field>
              <name>PG</name>
              <description>Page Program</description>
              <bitRange>[0:0]</bitRange>
            </field>
            <field>
              <name>PER</name>
              <description>Page Erase</description>
              <bitRange>[1:1]</bitRange>
            </field>
            <field>
              <name>MER0</name>
              <description>Bank 0 Mass Erase</description>
              <bitRange>[2:2]</bitRange>
            </field>
            <field>
              <name>MER1</name>
              <description>Bank 1 Mass Erase</description>
              <bitRange>[3:3]</bitRange>
            </field>
            <field>
              <name>SER</name>
              <description>Sector Erase</description>
              <bitRange>[11:11]</bitRange>
            </field>
            <field>
              <name>OPTSTRT</name>
              <description>Option bytes Programming Start</description>
              <bitRange>[17:17]</bitRange>
            </field>
            <field>
              <name>PGSTRT</name>
              <description>Programming Start</description>
              <bitRange>[19:19]</bitRange>
            </field>
            <field>
              <name>EOPIE</name>
              <description>End of operation interrupt enable</description>
              <bitRange>[24:24]</bitRange>
            </field>
            <field>
              <name>ERRIE</name>
              <description>Error interrupt enable</description>
              <bitRange>[25:25]</bitRange>
            </field>
            <field>
              <name>RDERRIE</name>
              <bitRange>[26:26]</bitRange>
            </field>
            <field>
              <name>OBL_LAUNCH</name>
              <description>Force the option bytes loading</description>
              <bitRange>[27:27]</bitRange>
            </field>
            <field>
              <name>OPTLOCK</name>
              <description>Option Lock</description>
              <bitRange>[30:30]</bitRange>
            </field>
            <field>
              <name>LOCK</name>
              <description>Lock</description>
              <bitRange>[31:31]</bitRange>
            </field>
          </fields>
        </register>
        <register>
          <name>OPTR1</name>
          <addressOffset>0x20</addressOffset>
          <fields>
            <field>
              <name>RDP</name>
              <description>Read Protection</description>
              <bitRange>[7:0]</bitRange>
            </field>
            <field>
              <name>IWDG_STOP</name>
              <bitRange>[9:9]</bitRange>
            </field>
            <field>
              <name>IWDG_STDBY</name>
              <bitRange>[10:10]</bitRange>
            </field>
            <field>
              <name>BFB</name>
              <bitRange>[11:11]</bitRange>
            </field>
            <field>
              <name>IWDG_SW</name>
              <description>IWDG Software Enable</description>
              <bitRange>[12:12]</bitRange>
            </field>
            <field>
              <name>NRST_STOP</name>
              <bitRange>[13:13]</bitRange>
            </field>
            <field>
              <name>NRST_STDBY</name>
              <bitRange>[14:14]</bitRange>
            </field>
            <field>
              <name>WWDG_SW</name>
              <bitRange>[15:15]</bitRange>
            </field>
          </fields>
        </register>
        <register>
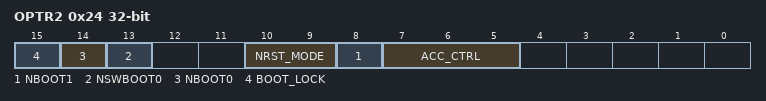
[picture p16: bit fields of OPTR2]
          <name>OPTR2</name>
          <addressOffset>0x24</addressOffset>
          <fields>
            <field>
              <name>ACC_CTRL</name>
              <bitRange>[7:5]</bitRange>
            </field>
            <field>
              <name>NBOOT1</name>
              <bitRange>[8:8]</bitRange>
            </field>
            <field>
              <name>NRST_MODE</name>
              <bitRange>[10:9]</bitRange>
            </field>
            <field>
              <name>NSWBOOT0</name>
              <bitRange>[13:13]</bitRange>
            </field>
            <field>
              <name>NBOOT0</name>
              <bitRange>[14:14]</bitRange>
            </field>
            <field>
              <name>BOOT_LOCK</name>
              <bitRange>[15:15]</bitRange>
              <access>read-only</access>
            </field>
          </fields>
        </register>
        <register>
          <name>BANK0_WRPR</name>
          <addressOffset>0x2C</addressOffset>
          <fields>
            <field>
              <name>BANK0_WRPR</name>
              <description>Write Protection Disable</description>
              <bitRange>[15:0]</bitRange>
            </field>
          </fields>
        </register>
        <register>
          <name>BANK1_WRPR</name>
          <addressOffset>0x30</addressOffset>
          <fields>
            <field>
              <name>BANK1_WRPR</name>
              <description>Write Protection Disable</description>
              <bitRange>[15:0]</bitRange>
            </field>
          </fields>
        </register>
        <register>
          <name>PCROP0SR</name>
          <addressOffset>0x34</addressOffset>
          <fields>
            <field>
              <name>PCROP0SR</name>
              <bitRange>[8:0]</bitRange>
            </field>
          </fields>
        </register>
        <register>
          <name>PCROP0ER</name>
          <addressOffset>0x38</addressOffset>
          <fields>
            <field>
              <name>PCROP0ER</name>
              <bitRange>[8:0]</bitRange>
            </field>
          </fields>
        </register>
        <register>
          <name>PCROP1SR</name>
          <addressOffset>0x3C</addressOffset>
          <fields>
            <field>
              <name>PCROP1SR</name>
              <bitRange>[8:0]</bitRange>
            </field>
          </fields>
        </register>
        <register>
          <name>PCROP1ER</name>
          <addressOffset>0x40</addressOffset>
          <fields>
            <field>
              <name>PCROP1ER</name>
              <bitRange>[8:0]</bitRange>
            </field>
          </fields>
        </register>
      </registers>
    </peripheral>
    <peripheral>
      <name>GPIOA</name>
      <baseAddress>0x40024000</baseAddress>
      <addressBlock>
        <offset>0x0</offset>
        <size>0x30</size>
        <usage>registers</usage>
      </addressBlock>
      <registers>
        <register>
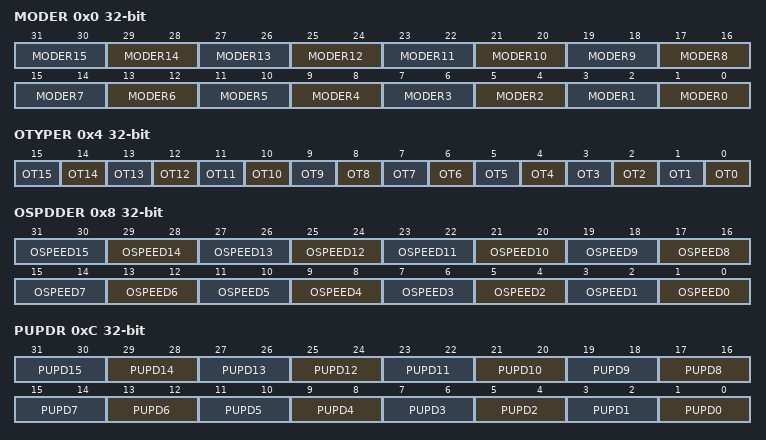
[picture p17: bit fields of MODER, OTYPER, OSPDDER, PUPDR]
          <name>MODER</name>
          <addressOffset>0x0</addressOffset>
          <fields>
            <field>
              <name>MODER0</name>
              <description>GPIOA0 MODE</description>
              <bitRange>[1:0]</bitRange>
            </field>
            <field>
              <name>MODER1</name>
              <description>GPIOA1 MODE</description>
              <bitRange>[3:2]</bitRange>
            </field>
            <field>
              <name>MODER2</name>
              <description>GPIOA2 MODE</description>
              <bitRange>[5:4]</bitRange>
            </field>
            <field>
              <name>MODER3</name>
              <description>GPIOA3 MODE</description>
              <bitRange>[7:6]</bitRange>
            </field>
            <field>
              <name>MODER4</name>
              <description>GPIOA4 MODE</description>
              <bitRange>[9:8]</bitRange>
            </field>
            <field>
              <name>MODER5</name>
              <description>GPIOA5 MODE</description>
              <bitRange>[11:10]</bitRange>
            </field>
            <field>
              <name>MODER6</name>
              <description>GPIOA6 MODE</description>
              <bitRange>[13:12]</bitRange>
            </field>
            <field>
              <name>MODER7</name>
              <description>GPIOA7 MODE</description>
              <bitRange>[15:14]</bitRange>
            </field>
            <field>
              <name>MODER8</name>
              <description>GPIOA8 MODE</description>
              <bitRange>[17:16]</bitRange>
            </field>
            <field>
              <name>MODER9</name>
              <description>GPIOA9 MODE</description>
              <bitRange>[19:18]</bitRange>
            </field>
            <field>
              <name>MODER10</name>
              <description>GPIOA10 MODE</description>
              <bitRange>[21:20]</bitRange>
            </field>
            <field>
              <name>MODER11</name>
              <description>GPIOA11 MODE</description>
              <bitRange>[23:22]</bitRange>
            </field>
            <field>
              <name>MODER12</name>
              <description>GPIOA12 MODE</description>
              <bitRange>[25:24]</bitRange>
            </field>
            <field>
              <name>MODER13</name>
              <description>GPIOA13 MODE</description>
              <bitRange>[27:26]</bitRange>
            </field>
            <field>
              <name>MODER14</name>
              <description>GPIOA14 MODE</description>
              <bitRange>[29:28]</bitRange>
            </field>
            <field>
              <name>MODER15</name>
              <description>GPIOA15 MODE</description>
              <bitRange>[31:30]</bitRange>
            </field>
          </fields>
        </register>
        <register>
          <name>OTYPER</name>
          <addressOffset>0x4</addressOffset>
          <fields>
            <field>
              <name>OT0</name>
              <description>GPIOA0 Output type</description>
              <bitRange>[0:0]</bitRange>
            </field>
            <field>
              <name>OT1</name>
              <description>GPIOA1 Output type</description>
              <bitRange>[1:1]</bitRange>
            </field>
            <field>
              <name>OT2</name>
              <description>GPIOA2 Output type</description>
              <bitRange>[2:2]</bitRange>
            </field>
            <field>
              <name>OT3</name>
              <description>GPIOA3 Output type</description>
              <bitRange>[3:3]</bitRange>
            </field>
            <field>
              <name>OT4</name>
              <description>GPIOA4 Output type</description>
              <bitRange>[4:4]</bitRange>
            </field>
            <field>
              <name>OT5</name>
              <description>GPIOA5 Output type</description>
              <bitRange>[5:5]</bitRange>
            </field>
            <field>
              <name>OT6</name>
              <description>GPIOA6 Output type</description>
              <bitRange>[6:6]</bitRange>
            </field>
            <field>
              <name>OT7</name>
              <description>GPIOA7 Output type</description>
              <bitRange>[7:7]</bitRange>
            </field>
            <field>
              <name>OT8</name>
              <description>GPIOA8 Output type</description>
              <bitRange>[8:8]</bitRange>
            </field>
            <field>
              <name>OT9</name>
              <description>GPIOA9 Output type</description>
              <bitRange>[9:9]</bitRange>
            </field>
            <field>
              <name>OT10</name>
              <description>GPIOA10 Output type</description>
              <bitRange>[10:10]</bitRange>
            </field>
            <field>
              <name>OT11</name>
              <description>GPIOA11 Output type</description>
              <bitRange>[11:11]</bitRange>
            </field>
            <field>
              <name>OT12</name>
              <description>GPIOA12 Output type</description>
              <bitRange>[12:12]</bitRange>
            </field>
            <field>
              <name>OT13</name>
              <description>GPIOA13 Output type</description>
              <bitRange>[13:13]</bitRange>
            </field>
            <field>
              <name>OT14</name>
              <description>GPIOA14 Output type</description>
              <bitRange>[14:14]</bitRange>
            </field>
            <field>
              <name>OT15</name>
              <description>GPIOA15 Output type</description>
              <bitRange>[15:15]</bitRange>
            </field>
          </fields>
        </register>
        <register>
          <name>OSPDDER</name>
          <addressOffset>0x8</addressOffset>
          <fields>
            <field>
              <name>OSPEED0</name>
              <description>GPIOA0 output speed</description>
              <bitRange>[1:0]</bitRange>
            </field>
            <field>
              <name>OSPEED1</name>
              <description>GPIOA1 output speed</description>
              <bitRange>[3:2]</bitRange>
            </field>
            <field>
              <name>OSPEED2</name>
              <description>GPIOA2 output speed</description>
              <bitRange>[5:4]</bitRange>
            </field>
            <field>
              <name>OSPEED3</name>
              <description>GPIOA3 output speed</description>
              <bitRange>[7:6]</bitRange>
            </field>
            <field>
              <name>OSPEED4</name>
              <description>GPIOA4 output speed</description>
              <bitRange>[9:8]</bitRange>
            </field>
            <field>
              <name>OSPEED5</name>
              <description>GPIOA5 output speed</description>
              <bitRange>[11:10]</bitRange>
            </field>
            <field>
              <name>OSPEED6</name>
              <description>GPIOA6 output speed</description>
              <bitRange>[13:12]</bitRange>
            </field>
            <field>
              <name>OSPEED7</name>
              <description>GPIOA7 output speed</description>
              <bitRange>[15:14]</bitRange>
            </field>
            <field>
              <name>OSPEED8</name>
              <description>GPIOA8 output speed</description>
              <bitRange>[17:16]</bitRange>
            </field>
            <field>
              <name>OSPEED9</name>
              <description>GPIOA9 output speed</description>
              <bitRange>[19:18]</bitRange>
            </field>
            <field>
              <name>OSPEED10</name>
              <description>GPIOA10 output speed</description>
              <bitRange>[21:20]</bitRange>
            </field>
            <field>
              <name>OSPEED11</name>
              <description>GPIOA11 output speed</description>
              <bitRange>[23:22]</bitRange>
            </field>
            <field>
              <name>OSPEED12</name>
              <description>GPIOA12 output speed</description>
              <bitRange>[25:24]</bitRange>
            </field>
            <field>
              <name>OSPEED13</name>
              <description>GPIOA13 output speed</description>
              <bitRange>[27:26]</bitRange>
            </field>
            <field>
              <name>OSPEED14</name>
              <description>GPIOA14 output speed</description>
              <bitRange>[29:28]</bitRange>
            </field>
            <field>
              <name>OSPEED15</name>
              <description>GPIOA15 output speed</description>
              <bitRange>[31:30]</bitRange>
            </field>
          </fields>
        </register>
        <register>
          <name>PUPDR</name>
          <addressOffset>0xC</addressOffset>
          <fields>
            <field>
              <name>PUPD0</name>
              <description>GPIOA0 pull up/pull down</description>
              <bitRange>[1:0]</bitRange>
            </field>
            <field>
              <name>PUPD1</name>
              <description>GPIOA1 pull up/pull down</description>
              <bitRange>[3:2]</bitRange>
            </field>
            <field>
              <name>PUPD2</name>
              <description>GPIOA2 pull up/pull down</description>
              <bitRange>[5:4]</bitRange>
            </field>
            <field>
              <name>PUPD3</name>
              <description>GPIOA3 pull up/pull down</description>
              <bitRange>[7:6]</bitRange>
            </field>
            <field>
              <name>PUPD4</name>
              <description>GPIOA4 pull up/pull down</description>
              <bitRange>[9:8]</bitRange>
            </field>
            <field>
              <name>PUPD5</name>
              <description>GPIOA5 pull up/pull down</description>
              <bitRange>[11:10]</bitRange>
            </field>
            <field>
              <name>PUPD6</name>
              <description>GPIOA6 pull up/pull down</description>
              <bitRange>[13:12]</bitRange>
            </field>
            <field>
              <name>PUPD7</name>
              <description>GPIOA7 pull up/pull down</description>
              <bitRange>[15:14]</bitRange>
            </field>
            <field>
              <name>PUPD8</name>
              <description>GPIOA8 pull up/pull down</description>
              <bitRange>[17:16]</bitRange>
            </field>
            <field>
              <name>PUPD9</name>
              <description>GPIOA9 pull up/pull down</description>
              <bitRange>[19:18]</bitRange>
            </field>
            <field>
              <name>PUPD10</name>
              <description>GPIOA10 pull up/pull down</description>
              <bitRange>[21:20]</bitRange>
            </field>
            <field>
              <name>PUPD11</name>
              <description>GPIOA11 pull up/pull down</description>
              <bitRange>[23:22]</bitRange>
            </field>
            <field>
              <name>PUPD12</name>
              <description>GPIOA12 pull up/pull down</description>
              <bitRange>[25:24]</bitRange>
            </field>
            <field>
              <name>PUPD13</name>
              <description>GPIOA13 pull up/pull down</description>
              <bitRange>[27:26]</bitRange>
            </field>
            <field>
              <name>PUPD14</name>
              <description>GPIOA14 pull up/pull down</description>
              <bitRange>[29:28]</bitRange>
            </field>
            <field>
              <name>PUPD15</name>
              <description>GPIOA15 pull up/pull down</description>
              <bitRange>[31:30]</bitRange>
            </field>
          </fields>
        </register>
        <register>
          <name>IDR</name>
          <addressOffset>0x10</addressOffset>
          <fields>
            <field>
              <name>ID0</name>
              <description>GPIOA0 input data</description>
              <bitRange>[0:0]</bitRange>
              <access>read-only</access>
            </field>
            <field>
              <name>ID1</name>
              <description>GPIOA1 input data</description>
              <bitRange>[1:1]</bitRange>
              <access>read-only</access>
            </field>
            <field>
              <name>ID2</name>
              <description>GPIOA2 input data</description>
              <bitRange>[2:2]</bitRange>
              <access>read-only</access>
            </field>
            <field>
              <name>ID3</name>
              <description>GPIOA3 input data</description>
              <bitRange>[3:3]</bitRange>
              <access>read-only</access>
            </field>
            <field>
              <name>ID4</name>
              <description>GPIOA4 input data</description>
              <bitRange>[4:4]</bitRange>
              <access>read-only</access>
            </field>
            <field>
              <name>ID5</name>
              <description>GPIOA5 input data</description>
              <bitRange>[5:5]</bitRange>
              <access>read-only</access>
            </field>
            <field>
              <name>ID6</name>
              <description>GPIOA6 input data</description>
              <bitRange>[6:6]</bitRange>
              <access>read-only</access>
            </field>
            <field>
              <name>ID7</name>
              <description>GPIOA7 input data</description>
              <bitRange>[7:7]</bitRange>
              <access>read-only</access>
            </field>
            <field>
              <name>ID8</name>
              <description>GPIOA8 input data</description>
              <bitRange>[8:8]</bitRange>
              <access>read-only</access>
            </field>
            <field>
              <name>ID9</name>
              <description>GPIOA9 input data</description>
              <bitRange>[9:9]</bitRange>
              <access>read-only</access>
            </field>
            <field>
              <name>ID10</name>
              <description>GPIOA10 input data</description>
              <bitRange>[10:10]</bitRange>
              <access>read-only</access>
            </field>
            <field>
              <name>ID11</name>
              <description>GPIOA11 input data</description>
              <bitRange>[11:11]</bitRange>
              <access>read-only</access>
            </field>
            <field>
              <name>ID12</name>
              <description>GPIOA12 input data</description>
              <bitRange>[12:12]</bitRange>
              <access>read-only</access>
            </field>
            <field>
              <name>ID13</name>
              <description>GPIOA13 input data</description>
              <bitRange>[13:13]</bitRange>
              <access>read-only</access>
            </field>
            <field>
              <name>ID14</name>
              <description>GPIOA14 input data</description>
              <bitRange>[14:14]</bitRange>
              <access>read-only</access>
            </field>
            <field>
              <name>ID15</name>
              <description>GPIOA15 input data</description>
              <bitRange>[15:15]</bitRange>
              <access>read-only</access>
            </field>
          </fields>
        </register>
        <register>
          <name>ODR</name>
          <addressOffset>0x14</addressOffset>
          <fields>
            <field>
              <name>OD0</name>
              <description>GPIOA0 output data</description>
              <bitRange>[0:0]</bitRange>
            </field>
            <field>
              <name>OD1</name>
              <description>GPIOA1 output data</description>
              <bitRange>[1:1]</bitRange>
            </field>
            <field>
              <name>OD2</name>
              <description>GPIOA2 output data</description>
              <bitRange>[2:2]</bitRange>
            </field>
            <field>
              <name>OD3</name>
              <description>GPIOA3 output data</description>
              <bitRange>[3:3]</bitRange>
            </field>
            <field>
              <name>OD4</name>
              <description>GPIOA4 output data</description>
              <bitRange>[4:4]</bitRange>
            </field>
            <field>
              <name>OD5</name>
              <description>GPIOA5 output data</description>
              <bitRange>[5:5]</bitRange>
            </field>
            <field>
              <name>OD6</name>
              <description>GPIOA6 output data</description>
              <bitRange>[6:6]</bitRange>
            </field>
            <field>
              <name>OD7</name>
              <description>GPIOA7 output data</description>
              <bitRange>[7:7]</bitRange>
            </field>
            <field>
              <name>OD8</name>
              <description>GPIOA8 output data</description>
              <bitRange>[8:8]</bitRange>
            </field>
            <field>
              <name>OD9</name>
              <description>GPIOA9 output data</description>
              <bitRange>[9:9]</bitRange>
            </field>
            <field>
              <name>OD10</name>
              <description>GPIOA10 output data</description>
              <bitRange>[10:10]</bitRange>
            </field>
            <field>
              <name>OD11</name>
              <description>GPIOA11 output data</description>
              <bitRange>[11:11]</bitRange>
            </field>
            <field>
              <name>OD12</name>
              <description>GPIOA12 output data</description>
              <bitRange>[12:12]</bitRange>
            </field>
            <field>
              <name>OD13</name>
              <description>GPIOA13 output data</description>
              <bitRange>[13:13]</bitRange>
            </field>
            <field>
              <name>OD14</name>
              <description>GPIOA14 output data</description>
              <bitRange>[14:14]</bitRange>
            </field>
            <field>
              <name>OD15</name>
              <description>GPIOA15 output data</description>
              <bitRange>[15:15]</bitRange>
            </field>
          </fields>
        </register>
        <register>
          <name>BSRR</name>
          <addressOffset>0x18</addressOffset>
          <fields>
            <field>
              <name>BS0</name>
              <description>GPIOA0 output set</description>
              <bitRange>[0:0]</bitRange>
            </field>
            <field>
              <name>BS1</name>
              <description>GPIOA1 output set</description>
              <bitRange>[1:1]</bitRange>
            </field>
            <field>
              <name>BS2</name>
              <description>GPIOA2 output set</description>
              <bitRange>[2:2]</bitRange>
            </field>
            <field>
              <name>BS3</name>
              <description>GPIOA3 output set</description>
              <bitRange>[3:3]</bitRange>
            </field>
            <field>
              <name>BS4</name>
              <description>GPIOA4 output set</description>
              <bitRange>[4:4]</bitRange>
            </field>
            <field>
              <name>BS5</name>
              <description>GPIOA5 output set</description>
              <bitRange>[5:5]</bitRange>
            </field>
            <field>
              <name>BS6</name>
              <description>GPIOA6 output set</description>
              <bitRange>[6:6]</bitRange>
            </field>
            <field>
              <name>BS7</name>
              <description>GPIOA7 output set</description>
              <bitRange>[7:7]</bitRange>
            </field>
            <field>
              <name>BS8</name>
              <description>GPIOA8 output set</description>
              <bitRange>[8:8]</bitRange>
            </field>
            <field>
              <name>BS9</name>
              <description>GPIOA9 output set</description>
              <bitRange>[9:9]</bitRange>
            </field>
            <field>
              <name>BS10</name>
              <description>GPIOA10 output set</description>
              <bitRange>[10:10]</bitRange>
            </field>
            <field>
              <name>BS11</name>
              <description>GPIOA11 output set</description>
              <bitRange>[11:11]</bitRange>
            </field>
            <field>
              <name>BS12</name>
              <description>GPIOA12 output set</description>
              <bitRange>[12:12]</bitRange>
            </field>
            <field>
              <name>BS13</name>
              <description>GPIOA13 output set</description>
              <bitRange>[13:13]</bitRange>
            </field>
            <field>
              <name>BS14</name>
              <description>GPIOA14 output set</description>
              <bitRange>[14:14]</bitRange>
            </field>
            <field>
              <name>BS15</name>
              <description>GPIOA15 output set</description>
              <bitRange>[15:15]</bitRange>
            </field>
            <field>
              <name>BR0</name>
              <description>GPIOA0 outut reset</description>
              <bitRange>[16:16]</bitRange>
            </field>
            <field>
              <name>BR1</name>
              <description>GPIOA1 outut reset</description>
              <bitRange>[17:17]</bitRange>
            </field>
            <field>
              <name>BR2</name>
              <description>GPIOA2 outut reset</description>
              <bitRange>[18:18]</bitRange>
            </field>
            <field>
              <name>BR3</name>
              <description>GPIOA3 outut reset</description>
              <bitRange>[19:19]</bitRange>
            </field>
            <field>
              <name>BR4</name>
              <description>GPIOA4 outut reset</description>
              <bitRange>[20:20]</bitRange>
            </field>
            <field>
              <name>BR5</name>
              <description>GPIOA5 outut reset</description>
              <bitRange>[21:21]</bitRange>
            </field>
            <field>
              <name>BR6</name>
              <description>GPIOA6 outut reset</description>
              <bitRange>[22:22]</bitRange>
            </field>
            <field>
              <name>BR7</name>
              <description>GPIOA7 outut reset</description>
              <bitRange>[23:23]</bitRange>
            </field>
            <field>
              <name>BR8</name>
              <description>GPIOA8 outut reset</description>
              <bitRange>[24:24]</bitRange>
            </field>
            <field>
              <name>BR9</name>
              <description>GPIOA9 outut reset</description>
              <bitRange>[25:25]</bitRange>
            </field>
            <field>
              <name>BR10</name>
              <description>GPIOA10 outut reset</description>
              <bitRange>[26:26]</bitRange>
            </field>
            <field>
              <name>BR11</name>
              <description>GPIOA11 outut reset</description>
              <bitRange>[27:27]</bitRange>
            </field>
            <field>
              <name>BR12</name>
              <description>GPIOA12 outut reset</description>
              <bitRange>[28:28]</bitRange>
            </field>
            <field>
              <name>BR13</name>
              <description>GPIOA13 outut reset</description>
              <bitRange>[29:29]</bitRange>
            </field>
            <field>
              <name>BR14</name>
              <description>GPIOA14 outut reset</description>
              <bitRange>[30:30]</bitRange>
            </field>
            <field>
              <name>BR15</name>
              <description>GPIOA15 outut reset</description>
              <bitRange>[31:31]</bitRange>
            </field>
          </fields>
        </register>
        <register>
          <name>LCKR</name>
          <addressOffset>0x1C</addressOffset>
          <fields>
            <field>
              <name>LCK0</name>
              <description>GPIOA lock(bit0)</description>
              <bitRange>[0:0]</bitRange>
            </field>
            <field>
              <name>LCK1</name>
              <description>GPIOA lock(bit1)</description>
              <bitRange>[1:1]</bitRange>
            </field>
            <field>
              <name>LCK2</name>
              <description>GPIOA lock(bit2)</description>
              <bitRange>[2:2]</bitRange>
            </field>
            <field>
              <name>LCK3</name>
              <description>GPIOA lock(bit3)</description>
              <bitRange>[3:3]</bitRange>
            </field>
            <field>
              <name>LCK4</name>
              <description>GPIOA lock(bit4)</description>
              <bitRange>[4:4]</bitRange>
            </field>
            <field>
              <name>LCK5</name>
              <description>GPIOA lock(bit5)</description>
              <bitRange>[5:5]</bitRange>
            </field>
            <field>
              <name>LCK6</name>
              <description>GPIOA lock(bit6)</description>
              <bitRange>[6:6]</bitRange>
            </field>
            <field>
              <name>LCK7</name>
              <description>GPIOA lock(bit7)</description>
              <bitRange>[7:7]</bitRange>
            </field>
            <field>
              <name>LCK8</name>
              <description>GPIOA lock(bit8)</description>
              <bitRange>[8:8]</bitRange>
            </field>
            <field>
              <name>LCK9</name>
              <description>GPIOA lock(bit9)</description>
              <bitRange>[9:9]</bitRange>
            </field>
            <field>
              <name>LCK10</name>
              <description>GPIOA lock(bit10)</description>
              <bitRange>[10:10]</bitRange>
            </field>
            <field>
              <name>LCK11</name>
              <description>GPIOA lock(bit11)</description>
              <bitRange>[11:11]</bitRange>
            </field>
            <field>
              <name>LCK12</name>
              <description>GPIOA lock(bit12)</description>
              <bitRange>[12:12]</bitRange>
            </field>
            <field>
              <name>LCK13</name>
              <description>GPIOA lock(bit13)</description>
              <bitRange>[13:13]</bitRange>
            </field>
            <field>
              <name>LCK14</name>
              <description>GPIOA lock(bit14)</description>
              <bitRange>[14:14]</bitRange>
            </field>
            <field>
              <name>LCK15</name>
              <description>GPIOA lock(bit15)</description>
              <bitRange>[15:15]</bitRange>
            </field>
            <field>
              <name>LCKK</name>
              <description>GPIOA lock key</description>
              <bitRange>[16:16]</bitRange>
            </field>
          </fields>
        </register>
        <register>
          <name>AFRL</name>
          <addressOffset>0x20</addressOffset>
          <fields>
            <field>
              <name>AFSEL0</name>
              <description>GPIOA0 AF select</description>
              <bitRange>[3:0]</bitRange>
            </field>
            <field>
              <name>AFSEL1</name>
              <description>GPIOA1 AF select</description>
              <bitRange>[7:4]</bitRange>
            </field>
            <field>
              <name>AFSEL2</name>
              <description>GPIOA2 AF select</description>
              <bitRange>[11:8]</bitRange>
            </field>
            <field>
              <name>AFSEL3</name>
              <description>GPIOA3 AF select</description>
              <bitRange>[15:12]</bitRange>
            </field>
            <field>
              <name>AFSEL4</name>
              <description>GPIOA4 AF select</description>
              <bitRange>[19:16]</bitRange>
            </field>
            <field>
              <name>AFSEL5</name>
              <description>GPIOA5 AF select</description>
              <bitRange>[23:20]</bitRange>
            </field>
            <field>
              <name>AFSEL6</name>
              <description>GPIOA6 AF select</description>
              <bitRange>[27:24]</bitRange>
            </field>
            <field>
              <name>AFSEL7</name>
              <description>GPIOA7 AF select</description>
              <bitRange>[31:28]</bitRange>
            </field>
          </fields>
        </register>
        <register>
          <name>AFRH</name>
          <addressOffset>0x24</addressOffset>
          <fields>
            <field>
              <name>AFSEL8</name>
              <description>GPIOA8 AF select</description>
              <bitRange>[3:0]</bitRange>
            </field>
            <field>
              <name>AFSEL9</name>
              <description>GPIOA9 AF select</description>
              <bitRange>[7:4]</bitRange>
            </field>
            <field>
              <name>AFSEL10</name>
              <description>GPIOA10 AF select</description>
              <bitRange>[11:8]</bitRange>
            </field>
            <field>
              <name>AFSEL11</name>
              <description>GPIOA11 AF select</description>
              <bitRange>[15:12]</bitRange>
            </field>
            <field>
              <name>AFSEL12</name>
              <description>GPIOA12 AF select</description>
              <bitRange>[19:16]</bitRange>
            </field>
            <field>
              <name>AFSEL13</name>
              <description>GPIOA13 AF select</description>
              <bitRange>[23:20]</bitRange>
            </field>
            <field>
              <name>AFSEL14</name>
              <description>GPIOA14 AF select</description>
              <bitRange>[27:24]</bitRange>
            </field>
            <field>
              <name>AFSEL15</name>
              <description>GPIOA15 AF select</description>
              <bitRange>[31:28]</bitRange>
            </field>
          </fields>
        </register>
        <register>
          <name>BRR</name>
          <addressOffset>0x28</addressOffset>
          <fields>
            <field>
              <name>BR0</name>
              <description>GPIOA 0 output pin reset</description>
              <bitRange>[0:0]</bitRange>
            </field>
            <field>
              <name>BR1</name>
              <description>GPIOA 1 output pin reset</description>
              <bitRange>[1:1]</bitRange>
            </field>
            <field>
              <name>BR2</name>
              <description>GPIOA 2 output pin reset</description>
              <bitRange>[2:2]</bitRange>
            </field>
            <field>
              <name>BR3</name>
              <description>GPIOA 3 output pin reset</description>
              <bitRange>[3:3]</bitRange>
            </field>
            <field>
              <name>BR4</name>
              <description>GPIOA 4 output pin reset</description>
              <bitRange>[4:4]</bitRange>
            </field>
            <field>
              <name>BR5</name>
              <description>GPIOA 5 output pin reset</description>
              <bitRange>[5:5]</bitRange>
            </field>
            <field>
              <name>BR6</name>
              <description>GPIOA 6 output pin reset</description>
              <bitRange>[6:6]</bitRange>
            </field>
            <field>
              <name>BR7</name>
              <description>GPIOA 7 output pin reset</description>
              <bitRange>[7:7]</bitRange>
            </field>
            <field>
              <name>BR8</name>
              <description>GPIOA 8 output pin reset</description>
              <bitRange>[8:8]</bitRange>
            </field>
            <field>
              <name>BR9</name>
              <description>GPIOA 9 output pin reset</description>
              <bitRange>[9:9]</bitRange>
            </field>
            <field>
              <name>BR10</name>
              <description>GPIOA 10 output pin reset</description>
              <bitRange>[10:10]</bitRange>
            </field>
            <field>
              <name>BR11</name>
              <description>GPIOA 11 output pin reset</description>
              <bitRange>[11:11]</bitRange>
            </field>
            <field>
              <name>BR12</name>
              <description>GPIOA 12 output pin reset</description>
              <bitRange>[12:12]</bitRange>
            </field>
            <field>
              <name>BR13</name>
              <description>GPIOA 13 output pin reset</description>
              <bitRange>[13:13]</bitRange>
            </field>
            <field>
              <name>BR14</name>
              <description>GPIOA 14 output pin reset</description>
              <bitRange>[14:14]</bitRange>
            </field>
            <field>
              <name>BR15</name>
              <description>GPIOA 15 output pin reset</description>
              <bitRange>[15:15]</bitRange>
            </field>
          </fields>
        </register>
      </registers>
    </peripheral>
    <peripheral>
      <name>GPIOB</name>
      <baseAddress>0x40024400</baseAddress>
      <addressBlock>
        <offset>0x0</offset>
        <size>0x30</size>
        <usage>registers</usage>
      </addressBlock>
      <registers>
        <register>
          <name>MODER</name>
          <addressOffset>0x0</addressOffset>
          <fields>
            <field>
              <name>MODER0</name>
              <description>GPIOB0 MODE</description>
              <bitRange>[1:0]</bitRange>
            </field>
            <field>
              <name>MODER1</name>
              <description>GPIOB1 MODE</description>
              <bitRange>[3:2]</bitRange>
            </field>
            <field>
              <name>MODER2</name>
              <description>GPIOB2 MODE</description>
              <bitRange>[5:4]</bitRange>
            </field>
            <field>
              <name>MODER3</name>
              <description>GPIOB3 MODE</description>
              <bitRange>[7:6]</bitRange>
            </field>
            <field>
              <name>MODER4</name>
              <description>GPIOB4 MODE</description>
              <bitRange>[9:8]</bitRange>
            </field>
            <field>
              <name>MODER5</name>
              <description>GPIOB5 MODE</description>
              <bitRange>[11:10]</bitRange>
            </field>
            <field>
              <name>MODER6</name>
              <description>GPIOB6 MODE</description>
              <bitRange>[13:12]</bitRange>
            </field>
            <field>
              <name>MODER7</name>
              <description>GPIOB7 MODE</description>
              <bitRange>[15:14]</bitRange>
            </field>
            <field>
              <name>MODER8</name>
              <description>GPIOB8 MODE</description>
              <bitRange>[17:16]</bitRange>
            </field>
            <field>
              <name>MODER9</name>
              <description>GPIOB9 MODE</description>
              <bitRange>[19:18]</bitRange>
            </field>
            <field>
              <name>MODER10</name>
              <description>GPIOB10 MODE</description>
              <bitRange>[21:20]</bitRange>
            </field>
            <field>
              <name>MODER11</name>
              <description>GPIOB11 MODE</description>
              <bitRange>[23:22]</bitRange>
            </field>
            <field>
              <name>MODER12</name>
              <description>GPIOB12 MODE</description>
              <bitRange>[25:24]</bitRange>
            </field>
            <field>
              <name>MODER13</name>
              <description>GPIOB13 MODE</description>
              <bitRange>[27:26]</bitRange>
            </field>
            <field>
              <name>MODER14</name>
              <description>GPIOB14 MODE</description>
              <bitRange>[29:28]</bitRange>
            </field>
            <field>
              <name>MODER15</name>
              <description>GPIOB15 MODE</description>
              <bitRange>[31:30]</bitRange>
            </field>
          </fields>
        </register>
        <register>
          <name>OTYPER</name>
          <addressOffset>0x4</addressOffset>
          <fields>
            <field>
              <name>OT0</name>
              <description>GPIOB0 Output type</description>
              <bitRange>[0:0]</bitRange>
            </field>
            <field>
              <name>OT1</name>
              <description>GPIOB1 Output type</description>
              <bitRange>[1:1]</bitRange>
            </field>
            <field>
              <name>OT2</name>
              <description>GPIOB2 Output type</description>
              <bitRange>[2:2]</bitRange>
            </field>
            <field>
              <name>OT3</name>
              <description>GPIOB3 Output type</description>
              <bitRange>[3:3]</bitRange>
            </field>
            <field>
              <name>OT4</name>
              <description>GPIOB4 Output type</description>
              <bitRange>[4:4]</bitRange>
            </field>
            <field>
              <name>OT5</name>
              <description>GPIOB5 Output type</description>
              <bitRange>[5:5]</bitRange>
            </field>
            <field>
              <name>OT6</name>
              <description>GPIOB6 Output type</description>
              <bitRange>[6:6]</bitRange>
            </field>
            <field>
              <name>OT7</name>
              <description>GPIOB7 Output type</description>
              <bitRange>[7:7]</bitRange>
            </field>
            <field>
              <name>OT8</name>
              <description>GPIOB8 Output type</description>
              <bitRange>[8:8]</bitRange>
            </field>
            <field>
              <name>OT9</name>
              <description>GPIOB9 Output type</description>
              <bitRange>[9:9]</bitRange>
            </field>
            <field>
              <name>OT10</name>
              <description>GPIOB10 Output type</description>
              <bitRange>[10:10]</bitRange>
            </field>
            <field>
              <name>OT11</name>
              <description>GPIOB11 Output type</description>
              <bitRange>[11:11]</bitRange>
            </field>
            <field>
              <name>OT12</name>
              <description>GPIOB12 Output type</description>
              <bitRange>[12:12]</bitRange>
            </field>
            <field>
              <name>OT13</name>
              <description>GPIOB13 Output type</description>
              <bitRange>[13:13]</bitRange>
            </field>
            <field>
              <name>OT14</name>
              <description>GPIOB14 Output type</description>
              <bitRange>[14:14]</bitRange>
            </field>
            <field>
              <name>OT15</name>
              <description>GPIOB15 Output type</description>
              <bitRange>[15:15]</bitRange>
            </field>
          </fields>
        </register>
        <register>
          <name>OSPDDER</name>
          <addressOffset>0x8</addressOffset>
          <fields>
            <field>
              <name>OSPEED0</name>
              <description>GPIOB0 output speed</description>
              <bitRange>[1:0]</bitRange>
            </field>
            <field>
              <name>OSPEED1</name>
              <description>GPIOB1 output speed</description>
              <bitRange>[3:2]</bitRange>
            </field>
            <field>
              <name>OSPEED2</name>
              <description>GPIOB2 output speed</description>
              <bitRange>[5:4]</bitRange>
            </field>
            <field>
              <name>OSPEED3</name>
              <description>GPIOB3 output speed</description>
              <bitRange>[7:6]</bitRange>
            </field>
            <field>
              <name>OSPEED4</name>
              <description>GPIOB4 output speed</description>
              <bitRange>[9:8]</bitRange>
            </field>
            <field>
              <name>OSPEED5</name>
              <description>GPIOB5 output speed</description>
              <bitRange>[11:10]</bitRange>
            </field>
            <field>
              <name>OSPEED6</name>
              <description>GPIOB6 output speed</description>
              <bitRange>[13:12]</bitRange>
            </field>
            <field>
              <name>OSPEED7</name>
              <description>GPIOB7 output speed</description>
              <bitRange>[15:14]</bitRange>
            </field>
            <field>
              <name>OSPEED8</name>
              <description>GPIOB8 output speed</description>
              <bitRange>[17:16]</bitRange>
            </field>
            <field>
              <name>OSPEED9</name>
              <description>GPIOB9 output speed</description>
              <bitRange>[19:18]</bitRange>
            </field>
            <field>
              <name>OSPEED10</name>
              <description>GPIOB10 output speed</description>
              <bitRange>[21:20]</bitRange>
            </field>
            <field>
              <name>OSPEED11</name>
              <description>GPIOB11 output speed</description>
              <bitRange>[23:22]</bitRange>
            </field>
            <field>
              <name>OSPEED12</name>
              <description>GPIOB12 output speed</description>
              <bitRange>[25:24]</bitRange>
            </field>
            <field>
              <name>OSPEED13</name>
              <description>GPIOB13 output speed</description>
              <bitRange>[27:26]</bitRange>
            </field>
            <field>
              <name>OSPEED14</name>
              <description>GPIOB14 output speed</description>
              <bitRange>[29:28]</bitRange>
            </field>
            <field>
              <name>OSPEED15</name>
              <description>GPIOB15 output speed</description>
              <bitRange>[31:30]</bitRange>
            </field>
          </fields>
        </register>
        <register>
          <name>PUPDR</name>
          <addressOffset>0xC</addressOffset>
          <fields>
            <field>
              <name>PUPD0</name>
              <description>GPIOB0 pull up/pull down</description>
              <bitRange>[1:0]</bitRange>
            </field>
            <field>
              <name>PUPD1</name>
              <description>GPIOB1 pull up/pull down</description>
              <bitRange>[3:2]</bitRange>
            </field>
            <field>
              <name>PUPD2</name>
              <description>GPIOB2 pull up/pull down</description>
              <bitRange>[5:4]</bitRange>
            </field>
            <field>
              <name>PUPD3</name>
              <description>GPIOB3 pull up/pull down</description>
              <bitRange>[7:6]</bitRange>
            </field>
            <field>
              <name>PUPD4</name>
              <description>GPIOB4 pull up/pull down</description>
              <bitRange>[9:8]</bitRange>
            </field>
            <field>
              <name>PUPD5</name>
              <description>GPIOB5 pull up/pull down</description>
              <bitRange>[11:10]</bitRange>
            </field>
            <field>
              <name>PUPD6</name>
              <description>GPIOB6 pull up/pull down</description>
              <bitRange>[13:12]</bitRange>
            </field>
            <field>
              <name>PUPD7</name>
              <description>GPIOB7 pull up/pull down</description>
              <bitRange>[15:14]</bitRange>
            </field>
            <field>
              <name>PUPD8</name>
              <description>GPIOB8 pull up/pull down</description>
              <bitRange>[17:16]</bitRange>
            </field>
            <field>
              <name>PUPD9</name>
              <description>GPIOB9 pull up/pull down</description>
              <bitRange>[19:18]</bitRange>
            </field>
            <field>
              <name>PUPD10</name>
              <description>GPIOB10 pull up/pull down</description>
              <bitRange>[21:20]</bitRange>
            </field>
            <field>
              <name>PUPD11</name>
              <description>GPIOB11 pull up/pull down</description>
              <bitRange>[23:22]</bitRange>
            </field>
            <field>
              <name>PUPD12</name>
              <description>GPIOB12 pull up/pull down</description>
              <bitRange>[25:24]</bitRange>
            </field>
            <field>
              <name>PUPD13</name>
              <description>GPIOB13 pull up/pull down</description>
              <bitRange>[27:26]</bitRange>
            </field>
            <field>
              <name>PUPD14</name>
              <description>GPIOB14 pull up/pull down</description>
              <bitRange>[29:28]</bitRange>
            </field>
            <field>
              <name>PUPD15</name>
              <description>GPIOB15 pull up/pull down</description>
              <bitRange>[31:30]</bitRange>
            </field>
          </fields>
        </register>
        <register>
          <name>IDR</name>
          <addressOffset>0x10</addressOffset>
          <fields>
            <field>
              <name>ID0</name>
              <description>GPIOB0 input data</description>
              <bitRange>[0:0]</bitRange>
              <access>read-only</access>
            </field>
            <field>
              <name>ID1</name>
              <description>GPIOB1 input data</description>
              <bitRange>[1:1]</bitRange>
              <access>read-only</access>
            </field>
            <field>
              <name>ID2</name>
              <description>GPIOB2 input data</description>
              <bitRange>[2:2]</bitRange>
              <access>read-only</access>
            </field>
            <field>
              <name>ID3</name>
              <description>GPIOB3 input data</description>
              <bitRange>[3:3]</bitRange>
              <access>read-only</access>
            </field>
            <field>
              <name>ID4</name>
              <description>GPIOB4 input data</description>
              <bitRange>[4:4]</bitRange>
              <access>read-only</access>
            </field>
            <field>
              <name>ID5</name>
              <description>GPIOB5 input data</description>
              <bitRange>[5:5]</bitRange>
              <access>read-only</access>
            </field>
            <field>
              <name>ID6</name>
              <description>GPIOB6 input data</description>
              <bitRange>[6:6]</bitRange>
              <access>read-only</access>
            </field>
            <field>
              <name>ID7</name>
              <description>GPIOB7 input data</description>
              <bitRange>[7:7]</bitRange>
              <access>read-only</access>
            </field>
            <field>
              <name>ID8</name>
              <description>GPIOB8 input data</description>
              <bitRange>[8:8]</bitRange>
              <access>read-only</access>
            </field>
            <field>
              <name>ID9</name>
              <description>GPIOB9 input data</description>
              <bitRange>[9:9]</bitRange>
              <access>read-only</access>
            </field>
            <field>
              <name>ID10</name>
              <description>GPIOB10 input data</description>
              <bitRange>[10:10]</bitRange>
              <access>read-only</access>
            </field>
            <field>
              <name>ID11</name>
              <description>GPIOB11 input data</description>
              <bitRange>[11:11]</bitRange>
              <access>read-only</access>
            </field>
            <field>
              <name>ID12</name>
              <description>GPIOB12 input data</description>
              <bitRange>[12:12]</bitRange>
              <access>read-only</access>
            </field>
            <field>
              <name>ID13</name>
              <description>GPIOB13 input data</description>
              <bitRange>[13:13]</bitRange>
              <access>read-only</access>
            </field>
            <field>
              <name>ID14</name>
              <description>GPIOB14 input data</description>
              <bitRange>[14:14]</bitRange>
              <access>read-only</access>
            </field>
            <field>
              <name>ID15</name>
              <description>GPIOB15 input data</description>
              <bitRange>[15:15]</bitRange>
              <access>read-only</access>
            </field>
          </fields>
        </register>
        <register>
          <name>ODR</name>
          <addressOffset>0x14</addressOffset>
          <fields>
            <field>
              <name>OD0</name>
              <description>GPIOB0 output data</description>
              <bitRange>[0:0]</bitRange>
            </field>
            <field>
              <name>OD1</name>
              <description>GPIOB1 output data</description>
              <bitRange>[1:1]</bitRange>
            </field>
            <field>
              <name>OD2</name>
              <description>GPIOB2 output data</description>
              <bitRange>[2:2]</bitRange>
            </field>
            <field>
              <name>OD3</name>
              <description>GPIOB3 output data</description>
              <bitRange>[3:3]</bitRange>
            </field>
            <field>
              <name>OD4</name>
              <description>GPIOB4 output data</description>
              <bitRange>[4:4]</bitRange>
            </field>
            <field>
              <name>OD5</name>
              <description>GPIOB5 output data</description>
              <bitRange>[5:5]</bitRange>
            </field>
            <field>
              <name>OD6</name>
              <description>GPIOB6 output data</description>
              <bitRange>[6:6]</bitRange>
            </field>
            <field>
              <name>OD7</name>
              <description>GPIOB7 output data</description>
              <bitRange>[7:7]</bitRange>
            </field>
            <field>
              <name>OD8</name>
              <description>GPIOB8 output data</description>
              <bitRange>[8:8]</bitRange>
            </field>
            <field>
              <name>OD9</name>
              <description>GPIOB9 output data</description>
              <bitRange>[9:9]</bitRange>
            </field>
            <field>
              <name>OD10</name>
              <description>GPIOB10 output data</description>
              <bitRange>[10:10]</bitRange>
            </field>
            <field>
              <name>OD11</name>
              <description>GPIOB11 output data</description>
              <bitRange>[11:11]</bitRange>
            </field>
            <field>
              <name>OD12</name>
              <description>GPIOB12 output data</description>
              <bitRange>[12:12]</bitRange>
            </field>
            <field>
              <name>OD13</name>
              <description>GPIOB13 output data</description>
              <bitRange>[13:13]</bitRange>
            </field>
            <field>
              <name>OD14</name>
              <description>GPIOB14 output data</description>
              <bitRange>[14:14]</bitRange>
            </field>
            <field>
              <name>OD15</name>
              <description>GPIOB15 output data</description>
              <bitRange>[15:15]</bitRange>
            </field>
          </fields>
        </register>
        <register>
          <name>BSRR</name>
          <addressOffset>0x18</addressOffset>
          <fields>
            <field>
              <name>BS0</name>
              <description>GPIOB0 output set</description>
              <bitRange>[0:0]</bitRange>
            </field>
            <field>
              <name>BS1</name>
              <description>GPIOB1 output set</description>
              <bitRange>[1:1]</bitRange>
            </field>
            <field>
              <name>BS2</name>
              <description>GPIOB2 output set</description>
              <bitRange>[2:2]</bitRange>
            </field>
            <field>
              <name>BS3</name>
              <description>GPIOB3 output set</description>
              <bitRange>[3:3]</bitRange>
            </field>
            <field>
              <name>BS4</name>
              <description>GPIOB4 output set</description>
              <bitRange>[4:4]</bitRange>
            </field>
            <field>
              <name>BS5</name>
              <description>GPIOB5 output set</description>
              <bitRange>[5:5]</bitRange>
            </field>
            <field>
              <name>BS6</name>
              <description>GPIOB6 output set</description>
              <bitRange>[6:6]</bitRange>
            </field>
            <field>
              <name>BS7</name>
              <description>GPIOB7 output set</description>
              <bitRange>[7:7]</bitRange>
            </field>
            <field>
              <name>BS8</name>
              <description>GPIOB8 output set</description>
              <bitRange>[8:8]</bitRange>
            </field>
            <field>
              <name>BS9</name>
              <description>GPIOB9 output set</description>
              <bitRange>[9:9]</bitRange>
            </field>
            <field>
              <name>BS10</name>
              <description>GPIOB10 output set</description>
              <bitRange>[10:10]</bitRange>
            </field>
            <field>
              <name>BS11</name>
              <description>GPIOB11 output set</description>
              <bitRange>[11:11]</bitRange>
            </field>
            <field>
              <name>BS12</name>
              <description>GPIOB12 output set</description>
              <bitRange>[12:12]</bitRange>
            </field>
            <field>
              <name>BS13</name>
              <description>GPIOB13 output set</description>
              <bitRange>[13:13]</bitRange>
            </field>
            <field>
              <name>BS14</name>
              <description>GPIOB14 output set</description>
              <bitRange>[14:14]</bitRange>
            </field>
            <field>
              <name>BS15</name>
              <description>GPIOB15 output set</description>
              <bitRange>[15:15]</bitRange>
            </field>
            <field>
              <name>BR0</name>
              <description>GPIOB0 outut reset</description>
              <bitRange>[16:16]</bitRange>
            </field>
            <field>
              <name>BR1</name>
              <description>GPIOB1 outut reset</description>
              <bitRange>[17:17]</bitRange>
            </field>
            <field>
              <name>BR2</name>
              <description>GPIOB2 outut reset</description>
              <bitRange>[18:18]</bitRange>
            </field>
            <field>
              <name>BR3</name>
              <description>GPIOB3 outut reset</description>
              <bitRange>[19:19]</bitRange>
            </field>
            <field>
              <name>BR4</name>
              <description>GPIOB4 outut reset</description>
              <bitRange>[20:20]</bitRange>
            </field>
            <field>
              <name>BR5</name>
              <description>GPIOB5 outut reset</description>
              <bitRange>[21:21]</bitRange>
            </field>
            <field>
              <name>BR6</name>
              <description>GPIOB6 outut reset</description>
              <bitRange>[22:22]</bitRange>
            </field>
            <field>
              <name>BR7</name>
              <description>GPIOB7 outut reset</description>
              <bitRange>[23:23]</bitRange>
            </field>
            <field>
              <name>BR8</name>
              <description>GPIOB8 outut reset</description>
              <bitRange>[24:24]</bitRange>
            </field>
            <field>
              <name>BR9</name>
              <description>GPIOB9 outut reset</description>
              <bitRange>[25:25]</bitRange>
            </field>
            <field>
              <name>BR10</name>
              <description>GPIOB10 outut reset</description>
              <bitRange>[26:26]</bitRange>
            </field>
            <field>
              <name>BR11</name>
              <description>GPIOB11 outut reset</description>
              <bitRange>[27:27]</bitRange>
            </field>
            <field>
              <name>BR12</name>
              <description>GPIOB12 outut reset</description>
              <bitRange>[28:28]</bitRange>
            </field>
            <field>
              <name>BR13</name>
              <description>GPIOB13 outut reset</description>
              <bitRange>[29:29]</bitRange>
            </field>
            <field>
              <name>BR14</name>
              <description>GPIOB14 outut reset</description>
              <bitRange>[30:30]</bitRange>
            </field>
            <field>
              <name>BR15</name>
              <description>GPIOB15 outut reset</description>
              <bitRange>[31:31]</bitRange>
            </field>
          </fields>
        </register>
        <register>
          <name>LCKR</name>
          <addressOffset>0x1C</addressOffset>
          <fields>
            <field>
              <name>LCK0</name>
              <description>GPIOB lock(bit0)</description>
              <bitRange>[0:0]</bitRange>
            </field>
            <field>
              <name>LCK1</name>
              <description>GPIOB lock(bit1)</description>
              <bitRange>[1:1]</bitRange>
            </field>
            <field>
              <name>LCK2</name>
              <description>GPIOB lock(bit2)</description>
              <bitRange>[2:2]</bitRange>
            </field>
            <field>
              <name>LCK3</name>
              <description>GPIOB lock(bit3)</description>
              <bitRange>[3:3]</bitRange>
            </field>
            <field>
              <name>LCK4</name>
              <description>GPIOB lock(bit4)</description>
              <bitRange>[4:4]</bitRange>
            </field>
            <field>
              <name>LCK5</name>
              <description>GPIOB lock(bit5)</description>
              <bitRange>[5:5]</bitRange>
            </field>
            <field>
              <name>LCK6</name>
              <description>GPIOB lock(bit6)</description>
              <bitRange>[6:6]</bitRange>
            </field>
            <field>
              <name>LCK7</name>
              <description>GPIOB lock(bit7)</description>
              <bitRange>[7:7]</bitRange>
            </field>
            <field>
              <name>LCK8</name>
              <description>GPIOB lock(bit8)</description>
              <bitRange>[8:8]</bitRange>
            </field>
            <field>
              <name>LCK9</name>
              <description>GPIOB lock(bit9)</description>
              <bitRange>[9:9]</bitRange>
            </field>
            <field>
              <name>LCK10</name>
              <description>GPIOB lock(bit10)</description>
              <bitRange>[10:10]</bitRange>
            </field>
            <field>
              <name>LCK11</name>
              <description>GPIOB lock(bit11)</description>
              <bitRange>[11:11]</bitRange>
            </field>
            <field>
              <name>LCK12</name>
              <description>GPIOB lock(bit12)</description>
              <bitRange>[12:12]</bitRange>
            </field>
            <field>
              <name>LCK13</name>
              <description>GPIOB lock(bit13)</description>
              <bitRange>[13:13]</bitRange>
            </field>
            <field>
              <name>LCK14</name>
              <description>GPIOB lock(bit14)</description>
              <bitRange>[14:14]</bitRange>
            </field>
            <field>
              <name>LCK15</name>
              <description>GPIOB lock(bit15)</description>
              <bitRange>[15:15]</bitRange>
            </field>
            <field>
              <name>LCKK</name>
              <description>GPIOB lock key</description>
              <bitRange>[16:16]</bitRange>
            </field>
          </fields>
        </register>
        <register>
          <name>AFRL</name>
          <addressOffset>0x20</addressOffset>
          <fields>
            <field>
              <name>AFSEL0</name>
              <description>GPIOB0 AF select</description>
              <bitRange>[3:0]</bitRange>
            </field>
            <field>
              <name>AFSEL1</name>
              <description>GPIOB1 AF select</description>
              <bitRange>[7:4]</bitRange>
            </field>
            <field>
              <name>AFSEL2</name>
              <description>GPIOB2 AF select</description>
              <bitRange>[11:8]</bitRange>
            </field>
            <field>
              <name>AFSEL3</name>
              <description>GPIOB3 AF select</description>
              <bitRange>[15:12]</bitRange>
            </field>
            <field>
              <name>AFSEL4</name>
              <description>GPIOB4 AF select</description>
              <bitRange>[19:16]</bitRange>
            </field>
            <field>
              <name>AFSEL5</name>
              <description>GPIOB5 AF select</description>
              <bitRange>[23:20]</bitRange>
            </field>
            <field>
              <name>AFSEL6</name>
              <description>GPIOB6 AF select</description>
              <bitRange>[27:24]</bitRange>
            </field>
            <field>
              <name>AFSEL7</name>
              <description>GPIOB7 AF select</description>
              <bitRange>[31:28]</bitRange>
            </field>
          </fields>
        </register>
        <register>
          <name>AFRH</name>
          <addressOffset>0x24</addressOffset>
          <fields>
            <field>
              <name>AFSEL8</name>
              <description>GPIOB8 AF select</description>
              <bitRange>[3:0]</bitRange>
            </field>
            <field>
              <name>AFSEL9</name>
              <description>GPIOB9 AF select</description>
              <bitRange>[7:4]</bitRange>
            </field>
            <field>
              <name>AFSEL10</name>
              <description>GPIOB10 AF select</description>
              <bitRange>[11:8]</bitRange>
            </field>
            <field>
              <name>AFSEL11</name>
              <description>GPIOB11 AF select</description>
              <bitRange>[15:12]</bitRange>
            </field>
            <field>
              <name>AFSEL12</name>
              <description>GPIOB12 AF select</description>
              <bitRange>[19:16]</bitRange>
            </field>
            <field>
              <name>AFSEL13</name>
              <description>GPIOB13 AF select</description>
              <bitRange>[23:20]</bitRange>
            </field>
            <field>
              <name>AFSEL14</name>
              <description>GPIOB14 AF select</description>
              <bitRange>[27:24]</bitRange>
            </field>
            <field>
              <name>AFSEL15</name>
              <description>GPIOB15 AF select</description>
              <bitRange>[31:28]</bitRange>
            </field>
          </fields>
        </register>
        <register>
          <name>BRR</name>
          <addressOffset>0x28</addressOffset>
          <fields>
            <field>
              <name>BR0</name>
              <description>GPIOB 0 output pin reset</description>
              <bitRange>[0:0]</bitRange>
            </field>
            <field>
              <name>BR1</name>
              <description>GPIOB 1 output pin reset</description>
              <bitRange>[1:1]</bitRange>
            </field>
            <field>
              <name>BR2</name>
              <description>GPIOB 2 output pin reset</description>
              <bitRange>[2:2]</bitRange>
            </field>
            <field>
              <name>BR3</name>
              <description>GPIOB 3 output pin reset</description>
              <bitRange>[3:3]</bitRange>
            </field>
            <field>
              <name>BR4</name>
              <description>GPIOB 4 output pin reset</description>
              <bitRange>[4:4]</bitRange>
            </field>
            <field>
              <name>BR5</name>
              <description>GPIOB 5 output pin reset</description>
              <bitRange>[5:5]</bitRange>
            </field>
            <field>
              <name>BR6</name>
              <description>GPIOB 6 output pin reset</description>
              <bitRange>[6:6]</bitRange>
            </field>
            <field>
              <name>BR7</name>
              <description>GPIOB 7 output pin reset</description>
              <bitRange>[7:7]</bitRange>
            </field>
            <field>
              <name>BR8</name>
              <description>GPIOB 8 output pin reset</description>
              <bitRange>[8:8]</bitRange>
            </field>
            <field>
              <name>BR9</name>
              <description>GPIOB 9 output pin reset</description>
              <bitRange>[9:9]</bitRange>
            </field>
            <field>
              <name>BR10</name>
              <description>GPIOB 10 output pin reset</description>
              <bitRange>[10:10]</bitRange>
            </field>
            <field>
              <name>BR11</name>
              <description>GPIOB 11 output pin reset</description>
              <bitRange>[11:11]</bitRange>
            </field>
            <field>
              <name>BR12</name>
              <description>GPIOB 12 output pin reset</description>
              <bitRange>[12:12]</bitRange>
            </field>
            <field>
              <name>BR13</name>
              <description>GPIOB 13 output pin reset</description>
              <bitRange>[13:13]</bitRange>
            </field>
            <field>
              <name>BR14</name>
              <description>GPIOB 14 output pin reset</description>
              <bitRange>[14:14]</bitRange>
            </field>
            <field>
              <name>BR15</name>
              <description>GPIOB 15 output pin reset</description>
              <bitRange>[15:15]</bitRange>
            </field>
          </fields>
        </register>
      </registers>
    </peripheral>
    <peripheral>
      <name>GPIOC</name>
      <baseAddress>0x40024800</baseAddress>
      <addressBlock>
        <offset>0x0</offset>
        <size>0x30</size>
        <usage>registers</usage>
      </addressBlock>
      <registers>
        <register>
          <name>MODER</name>
          <addressOffset>0x0</addressOffset>
          <fields>
            <field>
              <name>MODER0</name>
              <description>GPIOC0 MODE</description>
              <bitRange>[1:0]</bitRange>
            </field>
            <field>
              <name>MODER1</name>
              <description>GPIOC1 MODE</description>
              <bitRange>[3:2]</bitRange>
            </field>
            <field>
              <name>MODER2</name>
              <description>GPIOC2 MODE</description>
              <bitRange>[5:4]</bitRange>
            </field>
            <field>
              <name>MODER3</name>
              <description>GPIOC3 MODE</description>
              <bitRange>[7:6]</bitRange>
            </field>
            <field>
              <name>MODER4</name>
              <description>GPIOC4 MODE</description>
              <bitRange>[9:8]</bitRange>
            </field>
            <field>
              <name>MODER5</name>
              <description>GPIOC5 MODE</description>
              <bitRange>[11:10]</bitRange>
            </field>
            <field>
              <name>MODER6</name>
              <description>GPIOC6 MODE</description>
              <bitRange>[13:12]</bitRange>
            </field>
            <field>
              <name>MODER7</name>
              <description>GPIOC7 MODE</description>
              <bitRange>[15:14]</bitRange>
            </field>
            <field>
              <name>MODER8</name>
              <description>GPIOC8 MODE</description>
              <bitRange>[17:16]</bitRange>
            </field>
            <field>
              <name>MODER9</name>
              <description>GPIOC9 MODE</description>
              <bitRange>[19:18]</bitRange>
            </field>
            <field>
              <name>MODER10</name>
              <description>GPIOC10 MODE</description>
              <bitRange>[21:20]</bitRange>
            </field>
            <field>
              <name>MODER11</name>
              <description>GPIOC11 MODE</description>
              <bitRange>[23:22]</bitRange>
            </field>
            <field>
              <name>MODER12</name>
              <description>GPIOC12 MODE</description>
              <bitRange>[25:24]</bitRange>
            </field>
            <field>
              <name>MODER13</name>
              <description>GPIOC13 MODE</description>
              <bitRange>[27:26]</bitRange>
            </field>
            <field>
              <name>MODER14</name>
              <description>GPIOC14 MODE</description>
              <bitRange>[29:28]</bitRange>
            </field>
            <field>
              <name>MODER15</name>
              <description>GPIOC15 MODE</description>
              <bitRange>[31:30]</bitRange>
            </field>
          </fields>
        </register>
        <register>
          <name>OTYPER</name>
          <addressOffset>0x4</addressOffset>
          <fields>
            <field>
              <name>OT0</name>
              <description>GPIOC0 Output type</description>
              <bitRange>[0:0]</bitRange>
            </field>
            <field>
              <name>OT1</name>
              <description>GPIOC1 Output type</description>
              <bitRange>[1:1]</bitRange>
            </field>
            <field>
              <name>OT2</name>
              <description>GPIOC2 Output type</description>
              <bitRange>[2:2]</bitRange>
            </field>
            <field>
              <name>OT3</name>
              <description>GPIOC3 Output type</description>
              <bitRange>[3:3]</bitRange>
            </field>
            <field>
              <name>OT4</name>
              <description>GPIOC4 Output type</description>
              <bitRange>[4:4]</bitRange>
            </field>
            <field>
              <name>OT5</name>
              <description>GPIOC5 Output type</description>
              <bitRange>[5:5]</bitRange>
            </field>
            <field>
              <name>OT6</name>
              <description>GPIOC6 Output type</description>
              <bitRange>[6:6]</bitRange>
            </field>
            <field>
              <name>OT7</name>
              <description>GPIOC7 Output type</description>
              <bitRange>[7:7]</bitRange>
            </field>
            <field>
              <name>OT8</name>
              <description>GPIOC8 Output type</description>
              <bitRange>[8:8]</bitRange>
            </field>
            <field>
              <name>OT9</name>
              <description>GPIOC9 Output type</description>
              <bitRange>[9:9]</bitRange>
            </field>
            <field>
              <name>OT10</name>
              <description>GPIOC10 Output type</description>
              <bitRange>[10:10]</bitRange>
            </field>
            <field>
              <name>OT11</name>
              <description>GPIOC11 Output type</description>
              <bitRange>[11:11]</bitRange>
            </field>
            <field>
              <name>OT12</name>
              <description>GPIOC12 Output type</description>
              <bitRange>[12:12]</bitRange>
            </field>
            <field>
              <name>OT13</name>
              <description>GPIOC13 Output type</description>
              <bitRange>[13:13]</bitRange>
            </field>
            <field>
              <name>OT14</name>
              <description>GPIOC14 Output type</description>
              <bitRange>[14:14]</bitRange>
            </field>
            <field>
              <name>OT15</name>
              <description>GPIOC15 Output type</description>
              <bitRange>[15:15]</bitRange>
            </field>
          </fields>
        </register>
        <register>
          <name>OSPDDER</name>
          <addressOffset>0x8</addressOffset>
          <fields>
            <field>
              <name>OSPEED0</name>
              <description>GPIOC0 output speed</description>
              <bitRange>[1:0]</bitRange>
            </field>
            <field>
              <name>OSPEED1</name>
              <description>GPIOC1 output speed</description>
              <bitRange>[3:2]</bitRange>
            </field>
            <field>
              <name>OSPEED2</name>
              <description>GPIOC2 output speed</description>
              <bitRange>[5:4]</bitRange>
            </field>
            <field>
              <name>OSPEED3</name>
              <description>GPIOC3 output speed</description>
              <bitRange>[7:6]</bitRange>
            </field>
            <field>
              <name>OSPEED4</name>
              <description>GPIOC4 output speed</description>
              <bitRange>[9:8]</bitRange>
            </field>
            <field>
              <name>OSPEED5</name>
              <description>GPIOC5 output speed</description>
              <bitRange>[11:10]</bitRange>
            </field>
            <field>
              <name>OSPEED6</name>
              <description>GPIOC6 output speed</description>
              <bitRange>[13:12]</bitRange>
            </field>
            <field>
              <name>OSPEED7</name>
              <description>GPIOC7 output speed</description>
              <bitRange>[15:14]</bitRange>
            </field>
            <field>
              <name>OSPEED8</name>
              <description>GPIOC8 output speed</description>
              <bitRange>[17:16]</bitRange>
            </field>
            <field>
              <name>OSPEED9</name>
              <description>GPIOC9 output speed</description>
              <bitRange>[19:18]</bitRange>
            </field>
            <field>
              <name>OSPEED10</name>
              <description>GPIOC10 output speed</description>
              <bitRange>[21:20]</bitRange>
            </field>
            <field>
              <name>OSPEED11</name>
              <description>GPIOC11 output speed</description>
              <bitRange>[23:22]</bitRange>
            </field>
            <field>
              <name>OSPEED12</name>
              <description>GPIOC12 output speed</description>
              <bitRange>[25:24]</bitRange>
            </field>
            <field>
              <name>OSPEED13</name>
              <description>GPIOC13 output speed</description>
              <bitRange>[27:26]</bitRange>
            </field>
            <field>
              <name>OSPEED14</name>
              <description>GPIOC14 output speed</description>
              <bitRange>[29:28]</bitRange>
            </field>
            <field>
              <name>OSPEED15</name>
              <description>GPIOC15 output speed</description>
              <bitRange>[31:30]</bitRange>
            </field>
          </fields>
        </register>
        <register>
          <name>PUPDR</name>
          <addressOffset>0xC</addressOffset>
          <fields>
            <field>
              <name>PUPD0</name>
              <description>GPIOC0 pull up/pull down</description>
              <bitRange>[1:0]</bitRange>
            </field>
            <field>
              <name>PUPD1</name>
              <description>GPIOC1 pull up/pull down</description>
              <bitRange>[3:2]</bitRange>
            </field>
            <field>
              <name>PUPD2</name>
              <description>GPIOC2 pull up/pull down</description>
              <bitRange>[5:4]</bitRange>
            </field>
            <field>
              <name>PUPD3</name>
              <description>GPIOC3 pull up/pull down</description>
              <bitRange>[7:6]</bitRange>
            </field>
            <field>
              <name>PUPD4</name>
              <description>GPIOC4 pull up/pull down</description>
              <bitRange>[9:8]</bitRange>
            </field>
            <field>
              <name>PUPD5</name>
              <description>GPIOC5 pull up/pull down</description>
              <bitRange>[11:10]</bitRange>
            </field>
            <field>
              <name>PUPD6</name>
              <description>GPIOC6 pull up/pull down</description>
              <bitRange>[13:12]</bitRange>
            </field>
            <field>
              <name>PUPD7</name>
              <description>GPIOC7 pull up/pull down</description>
              <bitRange>[15:14]</bitRange>
            </field>
            <field>
              <name>PUPD8</name>
              <description>GPIOC8 pull up/pull down</description>
              <bitRange>[17:16]</bitRange>
            </field>
            <field>
              <name>PUPD9</name>
              <description>GPIOC9 pull up/pull down</description>
              <bitRange>[19:18]</bitRange>
            </field>
            <field>
              <name>PUPD10</name>
              <description>GPIOC10 pull up/pull down</description>
              <bitRange>[21:20]</bitRange>
            </field>
            <field>
              <name>PUPD11</name>
              <description>GPIOC11 pull up/pull down</description>
              <bitRange>[23:22]</bitRange>
            </field>
            <field>
              <name>PUPD12</name>
              <description>GPIOC12 pull up/pull down</description>
              <bitRange>[25:24]</bitRange>
            </field>
            <field>
              <name>PUPD13</name>
              <description>GPIOC13 pull up/pull down</description>
              <bitRange>[27:26]</bitRange>
            </field>
            <field>
              <name>PUPD14</name>
              <description>GPIOC14 pull up/pull down</description>
              <bitRange>[29:28]</bitRange>
            </field>
            <field>
              <name>PUPD15</name>
              <description>GPIOC15 pull up/pull down</description>
              <bitRange>[31:30]</bitRange>
            </field>
          </fields>
        </register>
        <register>
          <name>IDR</name>
          <addressOffset>0x10</addressOffset>
          <fields>
            <field>
              <name>ID0</name>
              <description>GPIOC0 input data</description>
              <bitRange>[0:0]</bitRange>
              <access>read-only</access>
            </field>
            <field>
              <name>ID1</name>
              <description>GPIOC1 input data</description>
              <bitRange>[1:1]</bitRange>
              <access>read-only</access>
            </field>
            <field>
              <name>ID2</name>
              <description>GPIOC2 input data</description>
              <bitRange>[2:2]</bitRange>
              <access>read-only</access>
            </field>
            <field>
              <name>ID3</name>
              <description>GPIOC3 input data</description>
              <bitRange>[3:3]</bitRange>
              <access>read-only</access>
            </field>
            <field>
              <name>ID4</name>
              <description>GPIOC4 input data</description>
              <bitRange>[4:4]</bitRange>
              <access>read-only</access>
            </field>
            <field>
              <name>ID5</name>
              <description>GPIOC5 input data</description>
              <bitRange>[5:5]</bitRange>
              <access>read-only</access>
            </field>
            <field>
              <name>ID6</name>
              <description>GPIOC6 input data</description>
              <bitRange>[6:6]</bitRange>
              <access>read-only</access>
            </field>
            <field>
              <name>ID7</name>
              <description>GPIOC7 input data</description>
              <bitRange>[7:7]</bitRange>
              <access>read-only</access>
            </field>
            <field>
              <name>ID8</name>
              <description>GPIOC8 input data</description>
              <bitRange>[8:8]</bitRange>
              <access>read-only</access>
            </field>
            <field>
              <name>ID9</name>
              <description>GPIOC9 input data</description>
              <bitRange>[9:9]</bitRange>
              <access>read-only</access>
            </field>
            <field>
              <name>ID10</name>
              <description>GPIOC10 input data</description>
              <bitRange>[10:10]</bitRange>
              <access>read-only</access>
            </field>
            <field>
              <name>ID11</name>
              <description>GPIOC11 input data</description>
              <bitRange>[11:11]</bitRange>
              <access>read-only</access>
            </field>
            <field>
              <name>ID12</name>
              <description>GPIOC12 input data</description>
              <bitRange>[12:12]</bitRange>
              <access>read-only</access>
            </field>
            <field>
              <name>ID13</name>
              <description>GPIOC13 input data</description>
              <bitRange>[13:13]</bitRange>
              <access>read-only</access>
            </field>
            <field>
              <name>ID14</name>
              <description>GPIOC14 input data</description>
              <bitRange>[14:14]</bitRange>
              <access>read-only</access>
            </field>
            <field>
              <name>ID15</name>
              <description>GPIOC15 input data</description>
              <bitRange>[15:15]</bitRange>
              <access>read-only</access>
            </field>
          </fields>
        </register>
        <register>
          <name>ODR</name>
          <addressOffset>0x14</addressOffset>
          <fields>
            <field>
              <name>OD0</name>
              <description>GPIOC0 output data</description>
              <bitRange>[0:0]</bitRange>
            </field>
            <field>
              <name>OD1</name>
              <description>GPIOC1 output data</description>
              <bitRange>[1:1]</bitRange>
            </field>
            <field>
              <name>OD2</name>
              <description>GPIOC2 output data</description>
              <bitRange>[2:2]</bitRange>
            </field>
            <field>
              <name>OD3</name>
              <description>GPIOC3 output data</description>
              <bitRange>[3:3]</bitRange>
            </field>
            <field>
              <name>OD4</name>
              <description>GPIOC4 output data</description>
              <bitRange>[4:4]</bitRange>
            </field>
            <field>
              <name>OD5</name>
              <description>GPIOC5 output data</description>
              <bitRange>[5:5]</bitRange>
            </field>
            <field>
              <name>OD6</name>
              <description>GPIOC6 output data</description>
              <bitRange>[6:6]</bitRange>
            </field>
            <field>
              <name>OD7</name>
              <description>GPIOC7 output data</description>
              <bitRange>[7:7]</bitRange>
            </field>
            <field>
              <name>OD8</name>
              <description>GPIOC8 output data</description>
              <bitRange>[8:8]</bitRange>
            </field>
            <field>
              <name>OD9</name>
              <description>GPIOC9 output data</description>
              <bitRange>[9:9]</bitRange>
            </field>
            <field>
              <name>OD10</name>
              <description>GPIOC10 output data</description>
              <bitRange>[10:10]</bitRange>
            </field>
            <field>
              <name>OD11</name>
              <description>GPIOC11 output data</description>
              <bitRange>[11:11]</bitRange>
            </field>
            <field>
              <name>OD12</name>
              <description>GPIOC12 output data</description>
              <bitRange>[12:12]</bitRange>
            </field>
            <field>
              <name>OD13</name>
              <description>GPIOC13 output data</description>
              <bitRange>[13:13]</bitRange>
            </field>
            <field>
              <name>OD14</name>
              <description>GPIOC14 output data</description>
              <bitRange>[14:14]</bitRange>
            </field>
            <field>
              <name>OD15</name>
              <description>GPIOC15 output data</description>
              <bitRange>[15:15]</bitRange>
            </field>
          </fields>
        </register>
        <register>
          <name>BSRR</name>
          <addressOffset>0x18</addressOffset>
          <fields>
            <field>
              <name>BS0</name>
              <description>GPIOC0 output set</description>
              <bitRange>[0:0]</bitRange>
            </field>
            <field>
              <name>BS1</name>
              <description>GPIOC1 output set</description>
              <bitRange>[1:1]</bitRange>
            </field>
            <field>
              <name>BS2</name>
              <description>GPIOC2 output set</description>
              <bitRange>[2:2]</bitRange>
            </field>
            <field>
              <name>BS3</name>
              <description>GPIOC3 output set</description>
              <bitRange>[3:3]</bitRange>
            </field>
            <field>
              <name>BS4</name>
              <description>GPIOC4 output set</description>
              <bitRange>[4:4]</bitRange>
            </field>
            <field>
              <name>BS5</name>
              <description>GPIOC5 output set</description>
              <bitRange>[5:5]</bitRange>
            </field>
            <field>
              <name>BS6</name>
              <description>GPIOC6 output set</description>
              <bitRange>[6:6]</bitRange>
            </field>
            <field>
              <name>BS7</name>
              <description>GPIOC7 output set</description>
              <bitRange>[7:7]</bitRange>
            </field>
            <field>
              <name>BS8</name>
              <description>GPIOC8 output set</description>
              <bitRange>[8:8]</bitRange>
            </field>
            <field>
              <name>BS9</name>
              <description>GPIOC9 output set</description>
              <bitRange>[9:9]</bitRange>
            </field>
            <field>
              <name>BS10</name>
              <description>GPIOC10 output set</description>
              <bitRange>[10:10]</bitRange>
            </field>
            <field>
              <name>BS11</name>
              <description>GPIOC11 output set</description>
              <bitRange>[11:11]</bitRange>
            </field>
            <field>
              <name>BS12</name>
              <description>GPIOC12 output set</description>
              <bitRange>[12:12]</bitRange>
            </field>
            <field>
              <name>BS13</name>
              <description>GPIOC13 output set</description>
              <bitRange>[13:13]</bitRange>
            </field>
            <field>
              <name>BS14</name>
              <description>GPIOC14 output set</description>
              <bitRange>[14:14]</bitRange>
            </field>
            <field>
              <name>BS15</name>
              <description>GPIOC15 output set</description>
              <bitRange>[15:15]</bitRange>
            </field>
            <field>
              <name>BR0</name>
              <description>GPIOC0 outut reset</description>
              <bitRange>[16:16]</bitRange>
            </field>
            <field>
              <name>BR1</name>
              <description>GPIOC1 outut reset</description>
              <bitRange>[17:17]</bitRange>
            </field>
            <field>
              <name>BR2</name>
              <description>GPIOC2 outut reset</description>
              <bitRange>[18:18]</bitRange>
            </field>
            <field>
              <name>BR3</name>
              <description>GPIOC3 outut reset</description>
              <bitRange>[19:19]</bitRange>
            </field>
            <field>
              <name>BR4</name>
              <description>GPIOC4 outut reset</description>
              <bitRange>[20:20]</bitRange>
            </field>
            <field>
              <name>BR5</name>
              <description>GPIOC5 outut reset</description>
              <bitRange>[21:21]</bitRange>
            </field>
            <field>
              <name>BR6</name>
              <description>GPIOC6 outut reset</description>
              <bitRange>[22:22]</bitRange>
            </field>
            <field>
              <name>BR7</name>
              <description>GPIOC7 outut reset</description>
              <bitRange>[23:23]</bitRange>
            </field>
            <field>
              <name>BR8</name>
              <description>GPIOC8 outut reset</description>
              <bitRange>[24:24]</bitRange>
            </field>
            <field>
              <name>BR9</name>
              <description>GPIOC9 outut reset</description>
              <bitRange>[25:25]</bitRange>
            </field>
            <field>
              <name>BR10</name>
              <description>GPIOC10 outut reset</description>
              <bitRange>[26:26]</bitRange>
            </field>
            <field>
              <name>BR11</name>
              <description>GPIOC11 outut reset</description>
              <bitRange>[27:27]</bitRange>
            </field>
            <field>
              <name>BR12</name>
              <description>GPIOC12 outut reset</description>
              <bitRange>[28:28]</bitRange>
            </field>
            <field>
              <name>BR13</name>
              <description>GPIOC13 outut reset</description>
              <bitRange>[29:29]</bitRange>
            </field>
            <field>
              <name>BR14</name>
              <description>GPIOC14 outut reset</description>
              <bitRange>[30:30]</bitRange>
            </field>
            <field>
              <name>BR15</name>
              <description>GPIOC15 outut reset</description>
              <bitRange>[31:31]</bitRange>
            </field>
          </fields>
        </register>
        <register>
          <name>LCKR</name>
          <addressOffset>0x1C</addressOffset>
          <fields>
            <field>
              <name>LCK0</name>
              <description>GPIOC lock(bit0)</description>
              <bitRange>[0:0]</bitRange>
            </field>
            <field>
              <name>LCK1</name>
              <description>GPIOC lock(bit1)</description>
              <bitRange>[1:1]</bitRange>
            </field>
            <field>
              <name>LCK2</name>
              <description>GPIOC lock(bit2)</description>
              <bitRange>[2:2]</bitRange>
            </field>
            <field>
              <name>LCK3</name>
              <description>GPIOC lock(bit3)</description>
              <bitRange>[3:3]</bitRange>
            </field>
            <field>
              <name>LCK4</name>
              <description>GPIOC lock(bit4)</description>
              <bitRange>[4:4]</bitRange>
            </field>
            <field>
              <name>LCK5</name>
              <description>GPIOC lock(bit5)</description>
              <bitRange>[5:5]</bitRange>
            </field>
            <field>
              <name>LCK6</name>
              <description>GPIOC lock(bit6)</description>
              <bitRange>[6:6]</bitRange>
            </field>
            <field>
              <name>LCK7</name>
              <description>GPIOC lock(bit7)</description>
              <bitRange>[7:7]</bitRange>
            </field>
            <field>
              <name>LCK8</name>
              <description>GPIOC lock(bit8)</description>
              <bitRange>[8:8]</bitRange>
            </field>
            <field>
              <name>LCK9</name>
              <description>GPIOC lock(bit9)</description>
              <bitRange>[9:9]</bitRange>
            </field>
            <field>
              <name>LCK10</name>
              <description>GPIOC lock(bit10)</description>
              <bitRange>[10:10]</bitRange>
            </field>
            <field>
              <name>LCK11</name>
              <description>GPIOC lock(bit11)</description>
              <bitRange>[11:11]</bitRange>
            </field>
            <field>
              <name>LCK12</name>
              <description>GPIOC lock(bit12)</description>
              <bitRange>[12:12]</bitRange>
            </field>
            <field>
              <name>LCK13</name>
              <description>GPIOC lock(bit13)</description>
              <bitRange>[13:13]</bitRange>
            </field>
            <field>
              <name>LCK14</name>
              <description>GPIOC lock(bit14)</description>
              <bitRange>[14:14]</bitRange>
            </field>
            <field>
              <name>LCK15</name>
              <description>GPIOC lock(bit15)</description>
              <bitRange>[15:15]</bitRange>
            </field>
            <field>
              <name>LCKK</name>
              <description>GPIOC lock key</description>
              <bitRange>[16:16]</bitRange>
            </field>
          </fields>
        </register>
        <register>
          <name>AFRL</name>
          <addressOffset>0x20</addressOffset>
          <fields>
            <field>
              <name>AFSEL0</name>
              <description>GPIOC0 AF select</description>
              <bitRange>[3:0]</bitRange>
            </field>
            <field>
              <name>AFSEL1</name>
              <description>GPIOC1 AF select</description>
              <bitRange>[7:4]</bitRange>
            </field>
            <field>
              <name>AFSEL2</name>
              <description>GPIOC2 AF select</description>
              <bitRange>[11:8]</bitRange>
            </field>
            <field>
              <name>AFSEL3</name>
              <description>GPIOC3 AF select</description>
              <bitRange>[15:12]</bitRange>
            </field>
            <field>
              <name>AFSEL4</name>
              <description>GPIOC4 AF select</description>
              <bitRange>[19:16]</bitRange>
            </field>
            <field>
              <name>AFSEL5</name>
              <description>GPIOC5 AF select</description>
              <bitRange>[23:20]</bitRange>
            </field>
            <field>
              <name>AFSEL6</name>
              <description>GPIOC6 AF select</description>
              <bitRange>[27:24]</bitRange>
            </field>
            <field>
              <name>AFSEL7</name>
              <description>GPIOC7 AF select</description>
              <bitRange>[31:28]</bitRange>
            </field>
          </fields>
        </register>
        <register>
          <name>AFRH</name>
          <addressOffset>0x24</addressOffset>
          <fields>
            <field>
              <name>AFSEL8</name>
              <description>GPIOC8 AF select</description>
              <bitRange>[3:0]</bitRange>
            </field>
            <field>
              <name>AFSEL9</name>
              <description>GPIOC9 AF select</description>
              <bitRange>[7:4]</bitRange>
            </field>
            <field>
              <name>AFSEL10</name>
              <description>GPIOC10 AF select</description>
              <bitRange>[11:8]</bitRange>
            </field>
            <field>
              <name>AFSEL11</name>
              <description>GPIOC11 AF select</description>
              <bitRange>[15:12]</bitRange>
            </field>
            <field>
              <name>AFSEL12</name>
              <description>GPIOC12 AF select</description>
              <bitRange>[19:16]</bitRange>
            </field>
            <field>
              <name>AFSEL13</name>
              <description>GPIOC13 AF select</description>
              <bitRange>[23:20]</bitRange>
            </field>
            <field>
              <name>AFSEL14</name>
              <description>GPIOC14 AF select</description>
              <bitRange>[27:24]</bitRange>
            </field>
            <field>
              <name>AFSEL15</name>
              <description>GPIOC15 AF select</description>
              <bitRange>[31:28]</bitRange>
            </field>
          </fields>
        </register>
        <register>
          <name>BRR</name>
          <addressOffset>0x28</addressOffset>
          <fields>
            <field>
              <name>BR0</name>
              <description>GPIOC 0 output pin reset</description>
              <bitRange>[0:0]</bitRange>
            </field>
            <field>
              <name>BR1</name>
              <description>GPIOC 1 output pin reset</description>
              <bitRange>[1:1]</bitRange>
            </field>
            <field>
              <name>BR2</name>
              <description>GPIOC 2 output pin reset</description>
              <bitRange>[2:2]</bitRange>
            </field>
            <field>
              <name>BR3</name>
              <description>GPIOC 3 output pin reset</description>
              <bitRange>[3:3]</bitRange>
            </field>
            <field>
              <name>BR4</name>
              <description>GPIOC 4 output pin reset</description>
              <bitRange>[4:4]</bitRange>
            </field>
            <field>
              <name>BR5</name>
              <description>GPIOC 5 output pin reset</description>
              <bitRange>[5:5]</bitRange>
            </field>
            <field>
              <name>BR6</name>
              <description>GPIOC 6 output pin reset</description>
              <bitRange>[6:6]</bitRange>
            </field>
            <field>
              <name>BR7</name>
              <description>GPIOC 7 output pin reset</description>
              <bitRange>[7:7]</bitRange>
            </field>
            <field>
              <name>BR8</name>
              <description>GPIOC 8 output pin reset</description>
              <bitRange>[8:8]</bitRange>
            </field>
            <field>
              <name>BR9</name>
              <description>GPIOC 9 output pin reset</description>
              <bitRange>[9:9]</bitRange>
            </field>
            <field>
              <name>BR10</name>
              <description>GPIOC 10 output pin reset</description>
              <bitRange>[10:10]</bitRange>
            </field>
            <field>
              <name>BR11</name>
              <description>GPIOC 11 output pin reset</description>
              <bitRange>[11:11]</bitRange>
            </field>
            <field>
              <name>BR12</name>
              <description>GPIOC 12 output pin reset</description>
              <bitRange>[12:12]</bitRange>
            </field>
            <field>
              <name>BR13</name>
              <description>GPIOC 13 output pin reset</description>
              <bitRange>[13:13]</bitRange>
            </field>
            <field>
              <name>BR14</name>
              <description>GPIOC 14 output pin reset</description>
              <bitRange>[14:14]</bitRange>
            </field>
            <field>
              <name>BR15</name>
              <description>GPIOC 15 output pin reset</description>
              <bitRange>[15:15]</bitRange>
            </field>
          </fields>
        </register>
      </registers>
    </peripheral>
    <peripheral>
      <name>GPIOD</name>
      <baseAddress>0x40024C00</baseAddress>
      <addressBlock>
        <offset>0x0</offset>
        <size>0x30</size>
        <usage>registers</usage>
      </addressBlock>
      <registers>
        <register>
          <name>MODER</name>
          <addressOffset>0x0</addressOffset>
          <fields>
            <field>
              <name>MODER0</name>
              <description>GPIOD0 MODE</description>
              <bitRange>[1:0]</bitRange>
            </field>
            <field>
              <name>MODER1</name>
              <description>GPIOD1 MODE</description>
              <bitRange>[3:2]</bitRange>
            </field>
            <field>
              <name>MODER2</name>
              <description>GPIOD2 MODE</description>
              <bitRange>[5:4]</bitRange>
            </field>
            <field>
              <name>MODER3</name>
              <description>GPIOD3 MODE</description>
              <bitRange>[7:6]</bitRange>
            </field>
            <field>
              <name>MODER4</name>
              <description>GPIOD4 MODE</description>
              <bitRange>[9:8]</bitRange>
            </field>
            <field>
              <name>MODER5</name>
              <description>GPIOD5 MODE</description>
              <bitRange>[11:10]</bitRange>
            </field>
            <field>
              <name>MODER6</name>
              <description>GPIOD6 MODE</description>
              <bitRange>[13:12]</bitRange>
            </field>
            <field>
              <name>MODER7</name>
              <description>GPIOD7 MODE</description>
              <bitRange>[15:14]</bitRange>
            </field>
            <field>
              <name>MODER8</name>
              <description>GPIOD8 MODE</description>
              <bitRange>[17:16]</bitRange>
            </field>
            <field>
              <name>MODER9</name>
              <description>GPIOD9 MODE</description>
              <bitRange>[19:18]</bitRange>
            </field>
            <field>
              <name>MODER10</name>
              <description>GPIOD10 MODE</description>
              <bitRange>[21:20]</bitRange>
            </field>
            <field>
              <name>MODER11</name>
              <description>GPIOD11 MODE</description>
              <bitRange>[23:22]</bitRange>
            </field>
          </fields>
        </register>
        <register>
          <name>OTYPER</name>
          <addressOffset>0x4</addressOffset>
          <fields>
            <field>
              <name>OT0</name>
              <description>GPIOD0 Output type</description>
              <bitRange>[0:0]</bitRange>
            </field>
            <field>
              <name>OT1</name>
              <description>GPIOD1 Output type</description>
              <bitRange>[1:1]</bitRange>
            </field>
            <field>
              <name>OT2</name>
              <description>GPIOD2 Output type</description>
              <bitRange>[2:2]</bitRange>
            </field>
            <field>
              <name>OT3</name>
              <description>GPIOD3 Output type</description>
              <bitRange>[3:3]</bitRange>
            </field>
            <field>
              <name>OT4</name>
              <description>GPIOD4 Output type</description>
              <bitRange>[4:4]</bitRange>
            </field>
            <field>
              <name>OT5</name>
              <description>GPIOD5 Output type</description>
              <bitRange>[5:5]</bitRange>
            </field>
            <field>
              <name>OT6</name>
              <description>GPIOD6 Output type</description>
              <bitRange>[6:6]</bitRange>
            </field>
            <field>
              <name>OT7</name>
              <description>GPIOD7 Output type</description>
              <bitRange>[7:7]</bitRange>
            </field>
            <field>
              <name>OT8</name>
              <description>GPIOD8 Output type</description>
              <bitRange>[8:8]</bitRange>
            </field>
            <field>
              <name>OT9</name>
              <description>GPIOD9 Output type</description>
              <bitRange>[9:9]</bitRange>
            </field>
            <field>
              <name>OT10</name>
              <description>GPIOD10 Output type</description>
              <bitRange>[10:10]</bitRange>
            </field>
            <field>
              <name>OT11</name>
              <description>GPIOD11 Output type</description>
              <bitRange>[11:11]</bitRange>
            </field>
          </fields>
        </register>
        <register>
          <name>OSPDDER</name>
          <addressOffset>0x8</addressOffset>
          <fields>
            <field>
              <name>OSPEED0</name>
              <description>GPIOD0 output speed</description>
              <bitRange>[1:0]</bitRange>
            </field>
            <field>
              <name>OSPEED1</name>
              <description>GPIOD1 output speed</description>
              <bitRange>[3:2]</bitRange>
            </field>
            <field>
              <name>OSPEED2</name>
              <description>GPIOD2 output speed</description>
              <bitRange>[5:4]</bitRange>
            </field>
            <field>
              <name>OSPEED3</name>
              <description>GPIOD3 output speed</description>
              <bitRange>[7:6]</bitRange>
            </field>
            <field>
              <name>OSPEED4</name>
              <description>GPIOD4 output speed</description>
              <bitRange>[9:8]</bitRange>
            </field>
            <field>
              <name>OSPEED5</name>
              <description>GPIOD5 output speed</description>
              <bitRange>[11:10]</bitRange>
            </field>
            <field>
              <name>OSPEED6</name>
              <description>GPIOD6 output speed</description>
              <bitRange>[13:12]</bitRange>
            </field>
            <field>
              <name>OSPEED7</name>
              <description>GPIOD7 output speed</description>
              <bitRange>[15:14]</bitRange>
            </field>
            <field>
              <name>OSPEED8</name>
              <description>GPIOD8 output speed</description>
              <bitRange>[17:16]</bitRange>
            </field>
            <field>
              <name>OSPEED9</name>
              <description>GPIOD9 output speed</description>
              <bitRange>[19:18]</bitRange>
            </field>
            <field>
              <name>OSPEED10</name>
              <description>GPIOD10 output speed</description>
              <bitRange>[21:20]</bitRange>
            </field>
            <field>
              <name>OSPEED11</name>
              <description>GPIOD11 output speed</description>
              <bitRange>[23:22]</bitRange>
            </field>
          </fields>
        </register>
        <register>
          <name>PUPDR</name>
          <addressOffset>0xC</addressOffset>
          <fields>
            <field>
              <name>PUPD0</name>
              <description>GPIOD0 pull up/pull down</description>
              <bitRange>[1:0]</bitRange>
            </field>
            <field>
              <name>PUPD1</name>
              <description>GPIOD1 pull up/pull down</description>
              <bitRange>[3:2]</bitRange>
            </field>
            <field>
              <name>PUPD2</name>
              <description>GPIOD2 pull up/pull down</description>
              <bitRange>[5:4]</bitRange>
            </field>
            <field>
              <name>PUPD3</name>
              <description>GPIOD3 pull up/pull down</description>
              <bitRange>[7:6]</bitRange>
            </field>
            <field>
              <name>PUPD4</name>
              <description>GPIOD4 pull up/pull down</description>
              <bitRange>[9:8]</bitRange>
            </field>
            <field>
              <name>PUPD5</name>
              <description>GPIOD5 pull up/pull down</description>
              <bitRange>[11:10]</bitRange>
            </field>
            <field>
              <name>PUPD6</name>
              <description>GPIOD6 pull up/pull down</description>
              <bitRange>[13:12]</bitRange>
            </field>
            <field>
              <name>PUPD7</name>
              <description>GPIOD7 pull up/pull down</description>
              <bitRange>[15:14]</bitRange>
            </field>
            <field>
              <name>PUPD8</name>
              <description>GPIOD8 pull up/pull down</description>
              <bitRange>[17:16]</bitRange>
            </field>
            <field>
              <name>PUPD9</name>
              <description>GPIOD9 pull up/pull down</description>
              <bitRange>[19:18]</bitRange>
            </field>
            <field>
              <name>PUPD10</name>
              <description>GPIOD10 pull up/pull down</description>
              <bitRange>[21:20]</bitRange>
            </field>
            <field>
              <name>PUPD11</name>
              <description>GPIOD11 pull up/pull down</description>
              <bitRange>[23:22]</bitRange>
            </field>
          </fields>
        </register>
        <register>
          <name>IDR</name>
          <addressOffset>0x10</addressOffset>
          <fields>
            <field>
              <name>ID0</name>
              <description>GPIOD0 input data</description>
              <bitRange>[0:0]</bitRange>
              <access>read-only</access>
            </field>
            <field>
              <name>ID1</name>
              <description>GPIOD1 input data</description>
              <bitRange>[1:1]</bitRange>
              <access>read-only</access>
            </field>
            <field>
              <name>ID2</name>
              <description>GPIOD2 input data</description>
              <bitRange>[2:2]</bitRange>
              <access>read-only</access>
            </field>
            <field>
              <name>ID3</name>
              <description>GPIOD3 input data</description>
              <bitRange>[3:3]</bitRange>
              <access>read-only</access>
            </field>
            <field>
              <name>ID4</name>
              <description>GPIOD4 input data</description>
              <bitRange>[4:4]</bitRange>
              <access>read-only</access>
            </field>
            <field>
              <name>ID5</name>
              <description>GPIOD5 input data</description>
              <bitRange>[5:5]</bitRange>
              <access>read-only</access>
            </field>
            <field>
              <name>ID6</name>
              <description>GPIOD6 input data</description>
              <bitRange>[6:6]</bitRange>
              <access>read-only</access>
            </field>
            <field>
              <name>ID7</name>
              <description>GPIOD7 input data</description>
              <bitRange>[7:7]</bitRange>
              <access>read-only</access>
            </field>
            <field>
              <name>ID8</name>
              <description>GPIOD8 input data</description>
              <bitRange>[8:8]</bitRange>
              <access>read-only</access>
            </field>
            <field>
              <name>ID9</name>
              <description>GPIOD9 input data</description>
              <bitRange>[9:9]</bitRange>
              <access>read-only</access>
            </field>
            <field>
              <name>ID10</name>
              <description>GPIOD10 input data</description>
              <bitRange>[10:10]</bitRange>
              <access>read-only</access>
            </field>
            <field>
              <name>ID11</name>
              <description>GPIOD11 input data</description>
              <bitRange>[11:11]</bitRange>
              <access>read-only</access>
            </field>
          </fields>
        </register>
        <register>
          <name>ODR</name>
          <addressOffset>0x14</addressOffset>
          <fields>
            <field>
              <name>OD0</name>
              <description>GPIOD0 output data</description>
              <bitRange>[0:0]</bitRange>
            </field>
            <field>
              <name>OD1</name>
              <description>GPIOD1 output data</description>
              <bitRange>[1:1]</bitRange>
            </field>
            <field>
              <name>OD2</name>
              <description>GPIOD2 output data</description>
              <bitRange>[2:2]</bitRange>
            </field>
            <field>
              <name>OD3</name>
              <description>GPIOD3 output data</description>
              <bitRange>[3:3]</bitRange>
            </field>
            <field>
              <name>OD4</name>
              <description>GPIOD4 output data</description>
              <bitRange>[4:4]</bitRange>
            </field>
            <field>
              <name>OD5</name>
              <description>GPIOD5 output data</description>
              <bitRange>[5:5]</bitRange>
            </field>
            <field>
              <name>OD6</name>
              <description>GPIOD6 output data</description>
              <bitRange>[6:6]</bitRange>
            </field>
            <field>
              <name>OD7</name>
              <description>GPIOD7 output data</description>
              <bitRange>[7:7]</bitRange>
            </field>
            <field>
              <name>OD8</name>
              <description>GPIOD8 output data</description>
              <bitRange>[8:8]</bitRange>
            </field>
            <field>
              <name>OD9</name>
              <description>GPIOD9 output data</description>
              <bitRange>[9:9]</bitRange>
            </field>
            <field>
              <name>OD10</name>
              <description>GPIOD10 output data</description>
              <bitRange>[10:10]</bitRange>
            </field>
            <field>
              <name>OD11</name>
              <description>GPIOD11 output data</description>
              <bitRange>[11:11]</bitRange>
            </field>
          </fields>
        </register>
        <register>
          <name>BSRR</name>
          <addressOffset>0x18</addressOffset>
          <fields>
            <field>
              <name>BS0</name>
              <description>GPIOD0 output set</description>
              <bitRange>[0:0]</bitRange>
            </field>
            <field>
              <name>BS1</name>
              <description>GPIOD1 output set</description>
              <bitRange>[1:1]</bitRange>
            </field>
            <field>
              <name>BS2</name>
              <description>GPIOD2 output set</description>
              <bitRange>[2:2]</bitRange>
            </field>
            <field>
              <name>BS3</name>
              <description>GPIOD3 output set</description>
              <bitRange>[3:3]</bitRange>
            </field>
            <field>
              <name>BS4</name>
              <description>GPIOD4 output set</description>
              <bitRange>[4:4]</bitRange>
            </field>
            <field>
              <name>BS5</name>
              <description>GPIOD5 output set</description>
              <bitRange>[5:5]</bitRange>
            </field>
            <field>
              <name>BS6</name>
              <description>GPIOD6 output set</description>
              <bitRange>[6:6]</bitRange>
            </field>
            <field>
              <name>BS7</name>
              <description>GPIOD7 output set</description>
              <bitRange>[7:7]</bitRange>
            </field>
            <field>
              <name>BS8</name>
              <description>GPIOD8 output set</description>
              <bitRange>[8:8]</bitRange>
            </field>
            <field>
              <name>BS9</name>
              <description>GPIOD9 output set</description>
              <bitRange>[9:9]</bitRange>
            </field>
            <field>
              <name>BS10</name>
              <description>GPIOD10 output set</description>
              <bitRange>[10:10]</bitRange>
            </field>
            <field>
              <name>BS11</name>
              <description>GPIOD11 output set</description>
              <bitRange>[11:11]</bitRange>
            </field>
            <field>
              <name>BR0</name>
              <description>GPIOD0 outut reset</description>
              <bitRange>[16:16]</bitRange>
            </field>
            <field>
              <name>BR1</name>
              <description>GPIOD1 outut reset</description>
              <bitRange>[17:17]</bitRange>
            </field>
            <field>
              <name>BR2</name>
              <description>GPIOD2 outut reset</description>
              <bitRange>[18:18]</bitRange>
            </field>
            <field>
              <name>BR3</name>
              <description>GPIOD3 outut reset</description>
              <bitRange>[19:19]</bitRange>
            </field>
            <field>
              <name>BR4</name>
              <description>GPIOD4 outut reset</description>
              <bitRange>[20:20]</bitRange>
            </field>
            <field>
              <name>BR5</name>
              <description>GPIOD5 outut reset</description>
              <bitRange>[21:21]</bitRange>
            </field>
            <field>
              <name>BR6</name>
              <description>GPIOD6 outut reset</description>
              <bitRange>[22:22]</bitRange>
            </field>
            <field>
              <name>BR7</name>
              <description>GPIOD7 outut reset</description>
              <bitRange>[23:23]</bitRange>
            </field>
            <field>
              <name>BR8</name>
              <description>GPIOD8 outut reset</description>
              <bitRange>[24:24]</bitRange>
            </field>
            <field>
              <name>BR9</name>
              <description>GPIOD9 outut reset</description>
              <bitRange>[25:25]</bitRange>
            </field>
            <field>
              <name>BR10</name>
              <description>GPIOD10 outut reset</description>
              <bitRange>[26:26]</bitRange>
            </field>
            <field>
              <name>BR11</name>
              <description>GPIOD11 outut reset</description>
              <bitRange>[27:27]</bitRange>
            </field>
          </fields>
        </register>
        <register>
          <name>LCKR</name>
          <addressOffset>0x1C</addressOffset>
          <fields>
            <field>
              <name>LCK0</name>
              <description>GPIOD lock(bit0)</description>
              <bitRange>[0:0]</bitRange>
            </field>
            <field>
              <name>LCK1</name>
              <description>GPIOD lock(bit1)</description>
              <bitRange>[1:1]</bitRange>
            </field>
            <field>
              <name>LCK2</name>
              <description>GPIOD lock(bit2)</description>
              <bitRange>[2:2]</bitRange>
            </field>
            <field>
              <name>LCK3</name>
              <description>GPIOD lock(bit3)</description>
              <bitRange>[3:3]</bitRange>
            </field>
            <field>
              <name>LCK4</name>
              <description>GPIOD lock(bit4)</description>
              <bitRange>[4:4]</bitRange>
            </field>
            <field>
              <name>LCK5</name>
              <description>GPIOD lock(bit5)</description>
              <bitRange>[5:5]</bitRange>
            </field>
            <field>
              <name>LCK6</name>
              <description>GPIOD lock(bit6)</description>
              <bitRange>[6:6]</bitRange>
            </field>
            <field>
              <name>LCK7</name>
              <description>GPIOD lock(bit7)</description>
              <bitRange>[7:7]</bitRange>
            </field>
            <field>
              <name>LCK8</name>
              <description>GPIOD lock(bit8)</description>
              <bitRange>[8:8]</bitRange>
            </field>
            <field>
              <name>LCK9</name>
              <description>GPIOD lock(bit9)</description>
              <bitRange>[9:9]</bitRange>
            </field>
            <field>
              <name>LCK10</name>
              <description>GPIOD lock(bit10)</description>
              <bitRange>[10:10]</bitRange>
            </field>
            <field>
              <name>LCK11</name>
              <description>GPIOD lock(bit11)</description>
              <bitRange>[11:11]</bitRange>
            </field>
            <field>
              <name>LCKK</name>
              <description>GPIOD lock key</description>
              <bitRange>[16:16]</bitRange>
            </field>
          </fields>
        </register>
        <register>
          <name>AFRL</name>
          <addressOffset>0x20</addressOffset>
          <fields>
            <field>
              <name>AFSEL0</name>
              <description>GPIOD0 AF select</description>
              <bitRange>[3:0]</bitRange>
            </field>
            <field>
              <name>AFSEL1</name>
              <description>GPIOD1 AF select</description>
              <bitRange>[7:4]</bitRange>
            </field>
            <field>
              <name>AFSEL2</name>
              <description>GPIOD2 AF select</description>
              <bitRange>[11:8]</bitRange>
            </field>
            <field>
              <name>AFSEL3</name>
              <description>GPIOD3 AF select</description>
              <bitRange>[15:12]</bitRange>
            </field>
            <field>
              <name>AFSEL4</name>
              <description>GPIOD4 AF select</description>
              <bitRange>[19:16]</bitRange>
            </field>
            <field>
              <name>AFSEL5</name>
              <description>GPIOD5 AF select</description>
              <bitRange>[23:20]</bitRange>
            </field>
            <field>
              <name>AFSEL6</name>
              <description>GPIOD6 AF select</description>
              <bitRange>[27:24]</bitRange>
            </field>
            <field>
              <name>AFSEL7</name>
              <description>GPIOD7 AF select</description>
              <bitRange>[31:28]</bitRange>
            </field>
          </fields>
        </register>
        <register>
          <name>AFRH</name>
          <addressOffset>0x24</addressOffset>
          <fields>
            <field>
              <name>AFSEL8</name>
              <description>GPIOD8 AF select</description>
              <bitRange>[3:0]</bitRange>
            </field>
            <field>
              <name>AFSEL9</name>
              <description>GPIOD9 AF select</description>
              <bitRange>[7:4]</bitRange>
            </field>
            <field>
              <name>AFSEL10</name>
              <description>GPIOD10 AF select</description>
              <bitRange>[11:8]</bitRange>
            </field>
            <field>
              <name>AFSEL11</name>
              <description>GPIOD11 AF select</description>
              <bitRange>[15:12]</bitRange>
            </field>
          </fields>
        </register>
        <register>
          <name>BRR</name>
          <addressOffset>0x28</addressOffset>
          <fields>
            <field>
              <name>BR0</name>
              <description>GPIOD 0 output pin reset</description>
              <bitRange>[0:0]</bitRange>
            </field>
            <field>
              <name>BR1</name>
              <description>GPIOD 1 output pin reset</description>
              <bitRange>[1:1]</bitRange>
            </field>
            <field>
              <name>BR2</name>
              <description>GPIOD 2 output pin reset</description>
              <bitRange>[2:2]</bitRange>
            </field>
            <field>
              <name>BR3</name>
              <description>GPIOD 3 output pin reset</description>
              <bitRange>[3:3]</bitRange>
            </field>
            <field>
              <name>BR4</name>
              <description>GPIOD 4 output pin reset</description>
              <bitRange>[4:4]</bitRange>
            </field>
            <field>
              <name>BR5</name>
              <description>GPIOD 5 output pin reset</description>
              <bitRange>[5:5]</bitRange>
            </field>
            <field>
              <name>BR6</name>
              <description>GPIOD 6 output pin reset</description>
              <bitRange>[6:6]</bitRange>
            </field>
            <field>
              <name>BR7</name>
              <description>GPIOD 7 output pin reset</description>
              <bitRange>[7:7]</bitRange>
            </field>
            <field>
              <name>BR8</name>
              <description>GPIOD 8 output pin reset</description>
              <bitRange>[8:8]</bitRange>
            </field>
            <field>
              <name>BR9</name>
              <description>GPIOD 9 output pin reset</description>
              <bitRange>[9:9]</bitRange>
            </field>
            <field>
              <name>BR10</name>
              <description>GPIOD 10 output pin reset</description>
              <bitRange>[10:10]</bitRange>
            </field>
            <field>
              <name>BR11</name>
              <description>GPIOD 11 output pin reset</description>
              <bitRange>[11:11]</bitRange>
            </field>
          </fields>
        </register>
      </registers>
    </peripheral>
    <peripheral>
      <name>I2C1</name>
      <groupName>I2C</groupName>
      <baseAddress>0x40005400</baseAddress>
      <addressBlock>
        <offset>0x0</offset>
        <size>0x30</size>
        <usage>registers</usage>
      </addressBlock>
      <registers>
        <register>
          <name>CR1</name>
          <addressOffset>0x0</addressOffset>
          <fields>
            <field>
              <name>PE</name>
              <description>Peripheral enable</description>
              <bitRange>[0:0]</bitRange>
            </field>
            <field>
              <name>SMBUS</name>
              <description>SMBus mode</description>
              <bitRange>[1:1]</bitRange>
            </field>
            <field>
              <name>WUPEN</name>
              <description>Wakeup from Stop mode enable</description>
              <bitRange>[2:2]</bitRange>
            </field>
            <field>
              <name>SMBTYPE</name>
              <description>SMBus type</description>
              <bitRange>[3:3]</bitRange>
            </field>
            <field>
              <name>ENARP</name>
              <description>ARP enable</description>
              <bitRange>[4:4]</bitRange>
            </field>
            <field>
              <name>ENPEC</name>
              <description>PEC enable</description>
              <bitRange>[5:5]</bitRange>
            </field>
            <field>
              <name>ENGC</name>
              <description>General call enable</description>
              <bitRange>[6:6]</bitRange>
            </field>
            <field>
              <name>NOSTRETCH</name>
              <description>Clock stretching disable (Slave mode)</description>
              <bitRange>[7:7]</bitRange>
            </field>
            <field>
              <name>START</name>
              <description>Start generation</description>
              <bitRange>[8:8]</bitRange>
            </field>
            <field>
              <name>STOP</name>
              <description>Stop generation</description>
              <bitRange>[9:9]</bitRange>
            </field>
            <field>
              <name>ACK</name>
              <description>Acknowledge enable</description>
              <bitRange>[10:10]</bitRange>
            </field>
            <field>
              <name>POS</name>
              <description>Acknowledge(for data reception)</description>
              <bitRange>[11:11]</bitRange>
            </field>
            <field>
              <name>PEC</name>
              <description>Packet error checking</description>
              <bitRange>[12:12]</bitRange>
            </field>
            <field>
              <name>ALERT</name>
              <description>SMBus alert</description>
              <bitRange>[13:13]</bitRange>
            </field>
            <field>
              <name>SWRST</name>
              <description>Software reset</description>
              <bitRange>[15:15]</bitRange>
            </field>
            <field>
              <name>WKUP_DIV</name>
              <description>PCLK division</description>
              <bitRange>[17:16]</bitRange>
            </field>
            <field>
              <name>WKUP_CNT</name>
              <description>Timeout count number</description>
              <bitRange>[19:18]</bitRange>
            </field>
          </fields>
        </register>
        <register>
          <name>CR2</name>
          <addressOffset>0x4</addressOffset>
          <fields>
            <field>
              <name>FREQ</name>
              <description>Peripheral clock frequency</description>
              <bitRange>[6:0]</bitRange>
            </field>
            <field>
              <name>ITERREN</name>
              <description>Error interrupt enable</description>
              <bitRange>[8:8]</bitRange>
            </field>
            <field>
              <name>ITEVTEN</name>
              <description>Event interrupt enable</description>
              <bitRange>[9:9]</bitRange>
            </field>
            <field>
              <name>ITBUFEN</name>
              <description>Buffer interrupt enable</description>
              <bitRange>[10:10]</bitRange>
            </field>
            <field>
              <name>DMAEN</name>
              <description>DMA requests enable</description>
              <bitRange>[11:11]</bitRange>
            </field>
            <field>
              <name>LAST</name>
              <description>DMA last transfer</description>
              <bitRange>[12:12]</bitRange>
            </field>
          </fields>
        </register>
        <register>
          <name>OAR1</name>
          <addressOffset>0x8</addressOffset>
          <fields>
            <field>
              <name>ADD</name>
              <description>Interface address</description>
              <bitRange>[9:0]</bitRange>
            </field>
            <field>
              <name>ADDMODE</name>
              <description>Addressing mode (slave mode)</description>
              <bitRange>[15:15]</bitRange>
            </field>
          </fields>
        </register>
        <register>
          <name>OAR2</name>
          <addressOffset>0xC</addressOffset>
          <fields>
            <field>
              <name>ENDUAL</name>
              <description>Dual addressing mode enable</description>
              <bitRange>[0:0]</bitRange>
            </field>
            <field>
              <name>ADD2</name>
              <description>Interface address</description>
              <bitRange>[7:1]</bitRange>
            </field>
            <field>
              <name>OA2MSK</name>
              <description>Own Address 2 masks</description>
              <bitRange>[10:8]</bitRange>
            </field>
          </fields>
        </register>
        <register>
          <name>DR</name>
          <addressOffset>0x10</addressOffset>
          <fields>
            <field>
              <name>DR</name>
              <description>8-bit data register</description>
              <bitRange>[7:0]</bitRange>
            </field>
          </fields>
        </register>
        <register>
          <name>SR1</name>
          <addressOffset>0x14</addressOffset>
          <fields>
            <field>
              <name>SB</name>
              <description>Start bit (Master mode)</description>
              <bitRange>[0:0]</bitRange>
              <access>read-only</access>
            </field>
            <field>
              <name>ADDR</name>
              <description>Address sent (master mode)/matched (slave mode)</description>
              <bitRange>[1:1]</bitRange>
              <access>read-only</access>
            </field>
            <field>
              <name>BTF</name>
              <description>Byte transfer finished</description>
              <bitRange>[2:2]</bitRange>
              <access>read-only</access>
            </field>
            <field>
              <name>ADD10</name>
              <description>10-bit header sent (Master mode)</description>
              <bitRange>[3:3]</bitRange>
              <access>read-only</access>
            </field>
            <field>
              <name>STOPF</name>
              <description>Stop detection (slave mode)</description>
              <bitRange>[4:4]</bitRange>
              <access>read-only</access>
            </field>
            <field>
              <name>RXNE</name>
              <description>Data register not empty (receivers)</description>
              <bitRange>[6:6]</bitRange>
              <access>read-only</access>
            </field>
            <field>
              <name>TXE</name>
              <description>Data register empty (transmitters)</description>
              <bitRange>[7:7]</bitRange>
              <access>read-only</access>
            </field>
            <field>
              <name>BERR</name>
              <description>Bus error</description>
              <bitRange>[8:8]</bitRange>
            </field>
            <field>
              <name>ARLO</name>
              <description>Arbitration lost (master mode)</description>
              <bitRange>[9:9]</bitRange>
            </field>
            <field>
              <name>AF</name>
              <description>Acknowledge failure</description>
              <bitRange>[10:10]</bitRange>
            </field>
            <field>
              <name>OVR</name>
              <description>Overrun/Underrun</description>
              <bitRange>[11:11]</bitRange>
            </field>
            <field>
              <name>PECERR</name>
              <description>PEC Error in reception</description>
              <bitRange>[12:12]</bitRange>
            </field>
            <field>
              <name>TIMEOUT</name>
              <description>Timeout or Tlow error</description>
              <bitRange>[14:14]</bitRange>
            </field>
            <field>
              <name>SMBALERT</name>
              <description>SMBus alert</description>
              <bitRange>[15:15]</bitRange>
            </field>
          </fields>
        </register>
        <register>
          <name>SR2</name>
          <addressOffset>0x18</addressOffset>
          <fields>
            <field>
              <name>MSL</name>
              <description>Master/slave</description>
              <bitRange>[0:0]</bitRange>
              <access>read-only</access>
            </field>
            <field>
              <name>BUSY</name>
              <description>Bus busy</description>
              <bitRange>[1:1]</bitRange>
              <access>read-only</access>
            </field>
            <field>
              <name>TRA</name>
              <description>Transmitter/receiver</description>
              <bitRange>[2:2]</bitRange>
              <access>read-only</access>
            </field>
            <field>
              <name>GENCALL</name>
              <description>General call address (Slave mode)</description>
              <bitRange>[4:4]</bitRange>
              <access>read-only</access>
            </field>
            <field>
              <name>SMBDEFAULT</name>
              <description>SMBus device default address (Slave mode)</description>
              <bitRange>[5:5]</bitRange>
            </field>
            <field>
              <name>SMBHOST</name>
              <description>SMBus host header (Slave mode)</description>
              <bitRange>[6:6]</bitRange>
            </field>
            <field>
              <name>DUALF</name>
              <description>Dual flag (Slave mode)</description>
              <bitRange>[7:7]</bitRange>
            </field>
            <field>
              <name>PEC</name>
              <description>Packet error checking register</description>
              <bitRange>[15:8]</bitRange>
            </field>
          </fields>
        </register>
        <register>
          <name>CCR</name>
          <addressOffset>0x1C</addressOffset>
          <fields>
            <field>
              <name>CCR</name>
              <description>Clock control register in Fm/Sm mode (Master mode)</description>
              <bitRange>[11:0]</bitRange>
            </field>
            <field>
              <name>FP</name>
              <description>I2C master mode selection</description>
              <bitRange>[13:13]</bitRange>
            </field>
            <field>
              <name>DUTY</name>
              <description>Fm mode duty cycle</description>
              <bitRange>[14:14]</bitRange>
            </field>
            <field>
              <name>FS</name>
              <description>I2C master mode selection</description>
              <bitRange>[15:15]</bitRange>
            </field>
          </fields>
        </register>
        <register>
          <name>TRISE</name>
          <addressOffset>0x20</addressOffset>
          <fields>
            <field>
              <name>TRISE</name>
              <description>Maximum rise time in Fm+/Fm/Sm mode (Master mode)</description>
              <bitRange>[6:0]</bitRange>
            </field>
            <field>
              <name>TDATAHOLD</name>
              <description>Data hold time</description>
              <bitRange>[11:7]</bitRange>
            </field>
            <field>
              <name>TDATAHOLD_SEL</name>
              <description>Data hold time select</description>
              <bitRange>[12:12]</bitRange>
            </field>
          </fields>
        </register>
        <register>
          <name>TIMEOUTR</name>
          <addressOffset>0x24</addressOffset>
          <fields>
            <field>
              <name>TIMEOUTA</name>
              <description>Bus Timeout A</description>
              <bitRange>[11:0]</bitRange>
            </field>
            <field>
              <name>TIDLE</name>
              <description>Idle clock timeout detection</description>
              <bitRange>[12:12]</bitRange>
            </field>
            <field>
              <name>TIMEOUTEN</name>
              <description>Clock timeout enable</description>
              <bitRange>[15:15]</bitRange>
            </field>
            <field>
              <name>TIMEOUTB</name>
              <description>Bus timeout B</description>
              <bitRange>[27:16]</bitRange>
            </field>
            <field>
              <name>TEXTEN</name>
              <description>Extended clock timeout enable</description>
              <bitRange>[31:31]</bitRange>
            </field>
          </fields>
        </register>
      </registers>
    </peripheral>
    <peripheral derivedFrom="I2C1">
      <name>I2C2</name>
      <baseAddress>0x40005800</baseAddress>
    </peripheral>
    <peripheral>
      <name>IWDG</name>
      <baseAddress>0x40003000</baseAddress>
      <addressBlock>
        <offset>0x0</offset>
        <size>0x10</size>
        <usage>registers</usage>
      </addressBlock>
      <registers>
        <register>
          <name>KR</name>
          <addressOffset>0x0</addressOffset>
          <fields>
            <field>
              <name>KEY</name>
              <description>IWDG KEY</description>
              <bitRange>[15:0]</bitRange>
            </field>
          </fields>
        </register>
        <register>
          <name>PR</name>
          <addressOffset>0x4</addressOffset>
          <fields>
            <field>
              <name>PR</name>
              <description>IWDG preload</description>
              <bitRange>[2:0]</bitRange>
            </field>
          </fields>
        </register>
        <register>
          <name>RLR</name>
          <addressOffset>0x8</addressOffset>
          <fields>
            <field>
              <name>RL</name>
              <description>IWDG reload</description>
              <bitRange>[11:0]</bitRange>
            </field>
          </fields>
        </register>
        <register>
          <name>SR</name>
          <addressOffset>0xC</addressOffset>
          <fields>
            <field>
              <name>PVU</name>
              <description>Watchdog prescaler value update</description>
              <bitRange>[0:0]</bitRange>
              <access>read-only</access>
            </field>
            <field>
              <name>RVU</name>
              <description>Watchdog counter reload value update</description>
              <bitRange>[1:1]</bitRange>
              <access>read-only</access>
            </field>
          </fields>
        </register>
      </registers>
    </peripheral>
    <peripheral>
      <name>LPTIM</name>
      <baseAddress>0x40007C00</baseAddress>
      <addressBlock>
        <offset>0x0</offset>
        <size>0x30</size>
        <usage>registers</usage>
      </addressBlock>
      <registers>
        <register>
          <name>ISR</name>
          <addressOffset>0x0</addressOffset>
          <fields>
            <field>
              <name>CMPM</name>
              <description>Compare match</description>
              <bitRange>[0:0]</bitRange>
              <access>read-only</access>
            </field>
            <field>
              <name>ARRM</name>
              <description>Autoreload match</description>
              <bitRange>[1:1]</bitRange>
              <access>read-only</access>
            </field>
            <field>
              <name>EXTTRIG</name>
              <description>External trigger edge event</description>
              <bitRange>[2:2]</bitRange>
              <access>read-only</access>
            </field>
            <field>
              <name>CMPOK</name>
              <description>Compare register update OK</description>
              <bitRange>[3:3]</bitRange>
              <access>read-only</access>
            </field>
            <field>
              <name>ARROK</name>
              <description>Autoreload register update OK</description>
              <bitRange>[4:4]</bitRange>
              <access>read-only</access>
            </field>
            <field>
              <name>UP</name>
              <description>Counter direction change down to up</description>
              <bitRange>[5:5]</bitRange>
              <access>read-only</access>
            </field>
            <field>
              <name>DOWN</name>
              <description>Counter direction change up to down</description>
              <bitRange>[6:6]</bitRange>
              <access>read-only</access>
            </field>
          </fields>
        </register>
        <register>
          <name>ICR</name>
          <addressOffset>0x4</addressOffset>
          <fields>
            <field>
              <name>CMPMCF</name>
              <description>Compare match clear flag</description>
              <bitRange>[0:0]</bitRange>
            </field>
            <field>
              <name>ARRMCF</name>
              <description>Autoreload match clear flag</description>
              <bitRange>[1:1]</bitRange>
            </field>
            <field>
              <name>EXTTRIGCF</name>
              <description>External trigger valid edge clear flag</description>
              <bitRange>[2:2]</bitRange>
            </field>
            <field>
              <name>CMPOKCF</name>
              <description>Compare register update OK clear flag</description>
              <bitRange>[3:3]</bitRange>
            </field>
            <field>
              <name>ARROKCF</name>
              <description>Autoreload register update OK clear flag</description>
              <bitRange>[4:4]</bitRange>
            </field>
            <field>
              <name>UPCF</name>
              <description>Direction change to UP clear flag</description>
              <bitRange>[5:5]</bitRange>
            </field>
            <field>
              <name>DOWNCF</name>
              <description>Direction change to down clear flag</description>
              <bitRange>[6:6]</bitRange>
            </field>
          </fields>
        </register>
        <register>
          <name>IER</name>
          <addressOffset>0x8</addressOffset>
          <fields>
            <field>
              <name>CMPMIE</name>
              <description>Compare match Interrupt Enable</description>
              <bitRange>[0:0]</bitRange>
            </field>
            <field>
              <name>ARRMIE</name>
              <description>Autoreload match Interrupt Enable</description>
              <bitRange>[1:1]</bitRange>
            </field>
            <field>
              <name>EXTTRIGIE</name>
              <description>External trigger valid edge Interrupt Enable</description>
              <bitRange>[2:2]</bitRange>
            </field>
            <field>
              <name>CMPOKIE</name>
              <description>Compare register update OK Interrupt Enable</description>
              <bitRange>[3:3]</bitRange>
            </field>
            <field>
              <name>ARROKIE</name>
              <description>Autoreload register update OK Interrupt Enable</description>
              <bitRange>[4:4]</bitRange>
            </field>
            <field>
              <name>UPIE</name>
              <description>Direction change to UP Interrupt Enable</description>
              <bitRange>[5:5]</bitRange>
            </field>
            <field>
              <name>DOWNIE</name>
              <description>Direction change to down Interrupt Enable</description>
              <bitRange>[6:6]</bitRange>
            </field>
          </fields>
        </register>
        <register>
          <name>CFGR</name>
          <addressOffset>0xC</addressOffset>
          <fields>
            <field>
              <name>CKSEL</name>
              <description>Clock selector</description>
              <bitRange>[0:0]</bitRange>
            </field>
            <field>
              <name>CKPOL</name>
              <description>Clock Polarity</description>
              <bitRange>[2:1]</bitRange>
            </field>
            <field>
              <name>CKFLT</name>
              <description>Configurable digital filter for external clock</description>
              <bitRange>[4:3]</bitRange>
            </field>
            <field>
              <name>TRGFLT</name>
              <description>Configurable digital filter for trigger</description>
              <bitRange>[7:6]</bitRange>
            </field>
            <field>
              <name>PRESC</name>
              <description>Clock prescaler</description>
              <bitRange>[11:9]</bitRange>
            </field>
            <field>
              <name>TRIGSEL</name>
              <description>Trigger selector</description>
              <bitRange>[15:13]</bitRange>
            </field>
            <field>
              <name>TRIGEN</name>
              <description>Trigger enable and polarity</description>
              <bitRange>[18:17]</bitRange>
            </field>
            <field>
              <name>TIMOUT</name>
              <description>Timeout enable</description>
              <bitRange>[19:19]</bitRange>
            </field>
            <field>
              <name>WAVE</name>
              <description>Waveform shape</description>
              <bitRange>[20:20]</bitRange>
            </field>
            <field>
              <name>WAVPOL</name>
              <description>Waveform shape polarity</description>
              <bitRange>[21:21]</bitRange>
            </field>
            <field>
              <name>PRELOAD</name>
              <description>Registers update mode</description>
              <bitRange>[22:22]</bitRange>
            </field>
            <field>
              <name>ENC</name>
              <description>Encoder mode enable</description>
              <bitRange>[24:24]</bitRange>
            </field>
          </fields>
        </register>
        <register>
          <name>CR</name>
          <addressOffset>0x10</addressOffset>
          <fields>
            <field>
              <name>ENABLE</name>
              <description>LPTIM enable</description>
              <bitRange>[0:0]</bitRange>
            </field>
            <field>
              <name>SNGSTRT</name>
              <description>LPTIM start in Single mode</description>
              <bitRange>[1:1]</bitRange>
            </field>
            <field>
              <name>CNTSTRT</name>
              <description>Timer start in Continuous mode</description>
              <bitRange>[2:2]</bitRange>
            </field>
          </fields>
        </register>
        <register>
          <name>CMP</name>
          <addressOffset>0x14</addressOffset>
          <fields>
            <field>
              <name>CMP</name>
              <description>Compare value</description>
              <bitRange>[15:0]</bitRange>
            </field>
          </fields>
        </register>
        <register>
          <name>ARR</name>
          <addressOffset>0x18</addressOffset>
          <fields>
            <field>
              <name>ARR</name>
              <description>Auto reload value</description>
              <bitRange>[15:0]</bitRange>
            </field>
          </fields>
        </register>
        <register>
          <name>CNT</name>
          <addressOffset>0x1C</addressOffset>
          <fields>
            <field>
              <name>CNT</name>
              <description>Counter value</description>
              <bitRange>[15:0]</bitRange>
              <access>read-only</access>
            </field>
          </fields>
        </register>
        <register>
          <name>OR</name>
          <addressOffset>0x20</addressOffset>
          <fields>
            <field>
              <name>IN1_L</name>
              <description>LPTimer input 1 remap extension</description>
              <bitRange>[0:0]</bitRange>
            </field>
            <field>
              <name>IN2_L</name>
              <description>LPTimer input 1 remap extension</description>
              <bitRange>[1:1]</bitRange>
            </field>
            <field>
              <name>IN1_H</name>
              <description>LPTimer input 3 remap extension</description>
              <bitRange>[3:2]</bitRange>
            </field>
            <field>
              <name>IN2_H</name>
              <description>LPTimer input 2 remap extension</description>
              <bitRange>[5:4]</bitRange>
            </field>
          </fields>
        </register>
      </registers>
    </peripheral>
    <peripheral>
      <name>LPUART</name>
      <baseAddress>0x40008000</baseAddress>
      <addressBlock>
        <offset>0x0</offset>
        <size>0x30</size>
        <usage>registers</usage>
      </addressBlock>
      <registers>
        <register>
          <name>CR1</name>
          <addressOffset>0x0</addressOffset>
          <fields>
            <field>
              <name>UE</name>
              <description>LPUART enabled</description>
              <bitRange>[0:0]</bitRange>
            </field>
            <field>
              <name>UESM</name>
              <description>LPUART enabled in Stop mode</description>
              <bitRange>[1:1]</bitRange>
            </field>
            <field>
              <name>RE</name>
              <description>Receive enable</description>
              <bitRange>[2:2]</bitRange>
            </field>
            <field>
              <name>TE</name>
              <description>Transfer enable</description>
              <bitRange>[3:3]</bitRange>
            </field>
            <field>
              <name>IDLEIE</name>
              <description>IDLE interrupt enable</description>
              <bitRange>[4:4]</bitRange>
            </field>
            <field>
              <name>RXFNEIE</name>
              <description>RXFIFO non-null interrupt enable</description>
              <bitRange>[5:5]</bitRange>
            </field>
            <field>
              <name>TCIE</name>
              <description>End of Transfer interrupt enabled</description>
              <bitRange>[6:6]</bitRange>
            </field>
            <field>
              <name>TXFNFIE</name>
              <description>TXFIFO is not full interrupt enabled</description>
              <bitRange>[7:7]</bitRange>
            </field>
            <field>
              <name>PEIE</name>
              <description>PE interrupt enable</description>
              <bitRange>[8:8]</bitRange>
            </field>
            <field>
              <name>PS</name>
              <description>Parity selection</description>
              <bitRange>[9:9]</bitRange>
            </field>
            <field>
              <name>PCE</name>
              <description>Parity control</description>
              <bitRange>[10:10]</bitRange>
            </field>
            <field>
              <name>WAKE</name>
              <description>Receive wake-up mode</description>
              <bitRange>[11:11]</bitRange>
            </field>
            <field>
              <name>M0</name>
              <description>Configure the word length in combination with M1</description>
              <bitRange>[12:12]</bitRange>
            </field>
            <field>
              <name>MME</name>
              <description>Silent mode enabled</description>
              <bitRange>[13:13]</bitRange>
            </field>
            <field>
              <name>CMIE</name>
              <description>Character match interrupt enabled</description>
              <bitRange>[14:14]</bitRange>
            </field>
            <field>
              <name>DEDT</name>
              <description>The time between the transmit frame stop bit and the invalid DE (driver enable) signal</description>
              <bitRange>[20:16]</bitRange>
            </field>
            <field>
              <name>DEAT</name>
              <description>The time between the DE (driver enable) signal validity and the start bit</description>
              <bitRange>[25:21]</bitRange>
            </field>
            <field>
              <name>M1</name>
              <description>The value of {M1,M0} the configurate length</description>
              <bitRange>[28:28]</bitRange>
            </field>
            <field>
              <name>FIFOEN</name>
              <description>FIFO mode enabled</description>
              <bitRange>[29:29]</bitRange>
            </field>
            <field>
              <name>TXFEIE</name>
              <description>TXFIFO null interrupt enabled</description>
              <bitRange>[30:30]</bitRange>
            </field>
            <field>
              <name>RXFFIE</name>
              <description>RXFIFO full interrupt enabled</description>
              <bitRange>[31:31]</bitRange>
            </field>
          </fields>
        </register>
        <register>
          <name>CR2</name>
          <addressOffset>0x4</addressOffset>
          <fields>
            <field>
              <name>ADDM7</name>
              <description>7bit/4bit address detection configuration</description>
              <bitRange>[4:4]</bitRange>
            </field>
            <field>
              <name>STOP</name>
              <description>Stop bit configuration</description>
              <bitRange>[13:12]</bitRange>
            </field>
            <field>
              <name>SWAP</name>
              <description>TX/RX pin interchangeable</description>
              <bitRange>[15:15]</bitRange>
            </field>
            <field>
              <name>RXINV</name>
              <description>The RX pin is active level inverting</description>
              <bitRange>[16:16]</bitRange>
            </field>
            <field>
              <name>TXINV</name>
              <description>TX pin active level inverted</description>
              <bitRange>[17:17]</bitRange>
            </field>
            <field>
              <name>DATAINV</name>
              <description>Inverse binary data processing</description>
              <bitRange>[18:18]</bitRange>
            </field>
            <field>
              <name>MSBFIRST</name>
              <description>MSB first</description>
              <bitRange>[19:19]</bitRange>
            </field>
            <field>
              <name>TXOE_ALWAYS_ON</name>
              <bitRange>[20:20]</bitRange>
            </field>
            <field>
              <name>ADD</name>
              <description>LPUART address</description>
              <bitRange>[31:24]</bitRange>
            </field>
          </fields>
        </register>
        <register>
          <name>CR3</name>
          <addressOffset>0x8</addressOffset>
          <fields>
            <field>
              <name>EIE</name>
              <description>Error interrupts are enabled</description>
              <bitRange>[0:0]</bitRange>
            </field>
            <field>
              <name>HDSEL</name>
              <description>Half-duplex selection</description>
              <bitRange>[3:3]</bitRange>
            </field>
            <field>
              <name>DMAR</name>
              <description>Enable DMA on reception</description>
              <bitRange>[6:6]</bitRange>
            </field>
            <field>
              <name>DMAT</name>
              <description>Enable DMA while transmitting</description>
              <bitRange>[7:7]</bitRange>
            </field>
            <field>
              <name>RTSE</name>
              <description>RTS enabled</description>
              <bitRange>[8:8]</bitRange>
            </field>
            <field>
              <name>CTSE</name>
              <description>CTS enabled</description>
              <bitRange>[9:9]</bitRange>
            </field>
            <field>
              <name>CTSIE</name>
              <description>CTS interrupt enable</description>
              <bitRange>[10:10]</bitRange>
            </field>
            <field>
              <name>OVRDIS</name>
              <description>Overrun is prohibited</description>
              <bitRange>[12:12]</bitRange>
            </field>
            <field>
              <name>DDRE</name>
              <description>Whether DMA is disabled when receiving an error</description>
              <bitRange>[13:13]</bitRange>
            </field>
            <field>
              <name>DEM</name>
              <description>DE mode enabled</description>
              <bitRange>[14:14]</bitRange>
            </field>
            <field>
              <name>DEP</name>
              <description>DE polarity selection</description>
              <bitRange>[15:15]</bitRange>
            </field>
            <field>
              <name>WUS</name>
              <description>Low-power wake-up options</description>
              <bitRange>[21:20]</bitRange>
            </field>
            <field>
              <name>WUFIE</name>
              <description>Low-power wake-up interrupt enable</description>
              <bitRange>[22:22]</bitRange>
            </field>
            <field>
              <name>TXFTIE</name>
              <description>TXFIFO threshold interrupt enabled</description>
              <bitRange>[23:23]</bitRange>
            </field>
            <field>
              <name>RXFTCFG</name>
              <description>RXFIFO full threshold configuration</description>
              <bitRange>[27:25]</bitRange>
            </field>
            <field>
              <name>RXFTIE</name>
              <description>RXFIFO threshold interrupt enabled</description>
              <bitRange>[28:28]</bitRange>
            </field>
            <field>
              <name>TXFTCFG</name>
              <description>TXFIFO threshold configuration</description>
              <bitRange>[31:29]</bitRange>
            </field>
          </fields>
        </register>
        <register>
          <name>BRR</name>
          <addressOffset>0xC</addressOffset>
          <fields>
            <field>
              <name>BBR</name>
              <description>LPUART baud rate</description>
              <bitRange>[19:0]</bitRange>
            </field>
          </fields>
        </register>
        <register>
          <name>RQR</name>
          <addressOffset>0x18</addressOffset>
          <fields>
            <field>
              <name>SBKRQ</name>
              <description>Send an abort request</description>
              <bitRange>[1:1]</bitRange>
            </field>
            <field>
              <name>MMRQ</name>
              <description>Silent mode request</description>
              <bitRange>[2:2]</bitRange>
            </field>
            <field>
              <name>RXFRQ</name>
              <description>Receive a data refresh request</description>
              <bitRange>[3:3]</bitRange>
            </field>
            <field>
              <name>TXFRQ</name>
              <description>Route a data refresh request</description>
              <bitRange>[4:4]</bitRange>
            </field>
          </fields>
        </register>
        <register>
          <name>ISR</name>
          <addressOffset>0x1C</addressOffset>
          <fields>
            <field>
              <name>PE</name>
              <description>Parity error</description>
              <bitRange>[0:0]</bitRange>
              <access>read-only</access>
            </field>
            <field>
              <name>FE</name>
              <description>Frame error flag</description>
              <bitRange>[1:1]</bitRange>
              <access>read-only</access>
            </field>
            <field>
              <name>NE</name>
              <description>START bit noise flag</description>
              <bitRange>[2:2]</bitRange>
              <access>read-only</access>
            </field>
            <field>
              <name>ORE</name>
              <description>Overrun error flag</description>
              <bitRange>[3:3]</bitRange>
              <access>read-only</access>
            </field>
            <field>
              <name>IDLE</name>
              <description>idle flag</description>
              <bitRange>[4:4]</bitRange>
              <access>read-only</access>
            </field>
            <field>
              <name>RXFNE</name>
              <description>RX register not empty</description>
              <bitRange>[5:5]</bitRange>
              <access>read-only</access>
            </field>
            <field>
              <name>TC</name>
              <description>Transmission completion flag</description>
              <bitRange>[6:6]</bitRange>
              <access>read-only</access>
            </field>
            <field>
              <name>TXFNF</name>
              <description>TX register not full</description>
              <bitRange>[7:7]</bitRange>
              <access>read-only</access>
            </field>
            <field>
              <name>CTSIF</name>
              <description>CTS interrupt flag</description>
              <bitRange>[9:9]</bitRange>
              <access>read-only</access>
            </field>
            <field>
              <name>CTS</name>
              <description>CTS flag</description>
              <bitRange>[10:10]</bitRange>
              <access>read-only</access>
            </field>
            <field>
              <name>BUSY</name>
              <description>Busy flag</description>
              <bitRange>[16:16]</bitRange>
              <access>read-only</access>
            </field>
            <field>
              <name>CMF</name>
              <description>Address match flag</description>
              <bitRange>[17:17]</bitRange>
              <access>read-only</access>
            </field>
            <field>
              <name>SBKF</name>
              <description>Send abort flag</description>
              <bitRange>[18:18]</bitRange>
              <access>read-only</access>
            </field>
            <field>
              <name>RWU</name>
              <description>Receive Mute mode wake-up flag</description>
              <bitRange>[19:19]</bitRange>
              <access>read-only</access>
            </field>
            <field>
              <name>WUF</name>
              <description>Wake flag from low-power mode</description>
              <bitRange>[20:20]</bitRange>
              <access>read-only</access>
            </field>
            <field>
              <name>TEACK</name>
              <description>Transport enable acknowledgement flag</description>
              <bitRange>[21:21]</bitRange>
              <access>read-only</access>
            </field>
            <field>
              <name>REACK</name>
              <description>Receive the enable acknowledgment flag</description>
              <bitRange>[22:22]</bitRange>
              <access>read-only</access>
            </field>
            <field>
              <name>TXFE</name>
              <description>TXFIFO empty</description>
              <bitRange>[23:23]</bitRange>
              <access>read-only</access>
            </field>
            <field>
              <name>RXFF</name>
              <description>RXFIFO full logo</description>
              <bitRange>[24:24]</bitRange>
              <access>read-only</access>
            </field>
            <field>
              <name>RXFT</name>
              <description>RCFIFO threshold flag</description>
              <bitRange>[26:26]</bitRange>
              <access>read-only</access>
            </field>
            <field>
              <name>TXFT</name>
              <description>TXFIFO threshold flag</description>
              <bitRange>[27:27]</bitRange>
              <access>read-only</access>
            </field>
          </fields>
        </register>
        <register>
          <name>ICR</name>
          <addressOffset>0x20</addressOffset>
          <fields>
            <field>
              <name>PECF</name>
              <description>Check value error flag reset</description>
              <bitRange>[0:0]</bitRange>
            </field>
            <field>
              <name>FECF</name>
              <description>Frame error flag reset</description>
              <bitRange>[1:1]</bitRange>
            </field>
            <field>
              <name>NECF</name>
              <description>Clear the START bit noise flag</description>
              <bitRange>[2:2]</bitRange>
            </field>
            <field>
              <name>ORECF</name>
              <description>Overrun error flag reset</description>
              <bitRange>[3:3]</bitRange>
            </field>
            <field>
              <name>IDLECF</name>
              <description>Clear idle flag</description>
              <bitRange>[4:4]</bitRange>
            </field>
            <field>
              <name>TCCF</name>
              <description>Transfer completion flag reset</description>
              <bitRange>[6:6]</bitRange>
            </field>
            <field>
              <name>CTSCF</name>
              <description>CTS flag reset</description>
              <bitRange>[9:9]</bitRange>
            </field>
            <field>
              <name>CMCF</name>
              <description>Address matching flag reset</description>
              <bitRange>[17:17]</bitRange>
            </field>
            <field>
              <name>WUCF</name>
              <description>Low power wake-up flag reset</description>
              <bitRange>[20:20]</bitRange>
            </field>
          </fields>
        </register>
        <register>
          <name>RDR</name>
          <addressOffset>0x24</addressOffset>
          <fields>
            <field>
              <name>RDR</name>
              <description>Receive Data Register</description>
              <bitRange>[8:0]</bitRange>
              <access>read-only</access>
            </field>
          </fields>
        </register>
        <register>
          <name>TDR</name>
          <addressOffset>0x28</addressOffset>
          <fields>
            <field>
              <name>TDR</name>
              <description>Transmit Data Register</description>
              <bitRange>[8:0]</bitRange>
            </field>
          </fields>
        </register>
        <register>
          <name>PRESC</name>
          <addressOffset>0x2C</addressOffset>
          <fields>
            <field>
              <name>PRESCALER</name>
              <description>Input clock prescaler register</description>
              <bitRange>[3:0]</bitRange>
            </field>
          </fields>
        </register>
      </registers>
    </peripheral>
    <peripheral>
      <name>OPA</name>
      <baseAddress>0x40017000</baseAddress>
      <addressBlock>
        <offset>0x0</offset>
        <size>0x30</size>
        <usage>registers</usage>
      </addressBlock>
      <registers>
        <register>
          <name>OPA1_CSR</name>
          <addressOffset>0x0</addressOffset>
          <fields>
            <field>
              <name>OPAEN</name>
              <bitRange>[0:0]</bitRange>
            </field>
            <field>
              <name>OPAINTOEN</name>
              <bitRange>[8:8]</bitRange>
            </field>
            <field>
              <name>OPALOCK</name>
              <bitRange>[31:31]</bitRange>
            </field>
          </fields>
        </register>
        <register>
          <name>OPA2_CSR</name>
          <addressOffset>0x4</addressOffset>
          <fields>
            <field>
              <name>OPAEN</name>
              <bitRange>[0:0]</bitRange>
            </field>
            <field>
              <name>OPA_CMP_CR</name>
              <bitRange>[1:1]</bitRange>
            </field>
            <field>
              <name>OPAINTOEN</name>
              <bitRange>[8:8]</bitRange>
            </field>
            <field>
              <name>OPA_CMP_OUT</name>
              <bitRange>[30:30]</bitRange>
              <access>read-only</access>
            </field>
            <field>
              <name>OPALOCK</name>
              <bitRange>[31:31]</bitRange>
            </field>
          </fields>
        </register>
        <register>
          <name>OPA2_FR</name>
          <addressOffset>0x20</addressOffset>
          <fields>
            <field>
              <name>FLTEN</name>
              <bitRange>[0:0]</bitRange>
            </field>
            <field>
              <name>FLTCNT</name>
              <bitRange>[31:16]</bitRange>
            </field>
          </fields>
        </register>
        <register>
          <name>OPA2_INTR</name>
          <addressOffset>0x24</addressOffset>
          <fields>
            <field>
              <name>INTEN</name>
              <bitRange>[0:0]</bitRange>
            </field>
            <field>
              <name>INTIF</name>
              <bitRange>[1:1]</bitRange>
              <access>read-only</access>
            </field>
            <field>
              <name>CINTIF</name>
              <bitRange>[2:2]</bitRange>
            </field>
          </fields>
        </register>
      </registers>
    </peripheral>
    <peripheral>
      <name>PWM1</name>
      <groupName>PWM</groupName>
      <baseAddress>0x40003400</baseAddress>
      <addressBlock>
        <offset>0x0</offset>
        <size>0x50</size>
        <usage>registers</usage>
      </addressBlock>
      <registers>
        <register>
          <name>CR1</name>
          <addressOffset>0x0</addressOffset>
          <fields>
            <field>
              <name>CEN</name>
              <bitRange>[0:0]</bitRange>
            </field>
            <field>
              <name>UDIS</name>
              <bitRange>[1:1]</bitRange>
            </field>
            <field>
              <name>URS</name>
              <bitRange>[2:2]</bitRange>
            </field>
            <field>
              <name>DIR</name>
              <bitRange>[4:4]</bitRange>
            </field>
            <field>
              <name>CMS</name>
              <bitRange>[6:5]</bitRange>
            </field>
            <field>
              <name>ARPE</name>
              <bitRange>[7:7]</bitRange>
            </field>
            <field>
              <name>CKD</name>
              <bitRange>[9:8]</bitRange>
            </field>
            <field>
              <name>INTR_SEL</name>
              <bitRange>[13:12]</bitRange>
            </field>
            <field>
              <name>PWM_PHS_EN</name>
              <bitRange>[14:14]</bitRange>
            </field>
          </fields>
        </register>
        <register>
          <name>CR2</name>
          <addressOffset>0x4</addressOffset>
          <fields>
            <field>
              <name>BKINE</name>
              <bitRange>[0:0]</bitRange>
            </field>
            <field>
              <name>BKCMP1E</name>
              <bitRange>[1:1]</bitRange>
            </field>
            <field>
              <name>BKCMP2E</name>
              <bitRange>[2:2]</bitRange>
            </field>
            <field>
              <name>BKINP</name>
              <bitRange>[9:9]</bitRange>
            </field>
            <field>
              <name>BKCMP1P</name>
              <bitRange>[10:10]</bitRange>
            </field>
            <field>
              <name>BKCMP2P</name>
              <bitRange>[11:11]</bitRange>
            </field>
            <field>
              <name>ETRSEL</name>
              <bitRange>[15:13]</bitRange>
            </field>
          </fields>
        </register>
        <register>
          <name>SMCR</name>
          <addressOffset>0x8</addressOffset>
          <fields>
            <field>
              <name>ETF</name>
              <bitRange>[11:8]</bitRange>
            </field>
            <field>
              <name>ETPS</name>
              <bitRange>[13:12]</bitRange>
            </field>
            <field>
              <name>ECE</name>
              <bitRange>[14:14]</bitRange>
            </field>
            <field>
              <name>ETP</name>
              <bitRange>[15:15]</bitRange>
            </field>
          </fields>
        </register>
        <register>
          <name>DIER</name>
          <addressOffset>0xC</addressOffset>
          <fields>
            <field>
              <name>UIE</name>
              <bitRange>[0:0]</bitRange>
            </field>
            <field>
              <name>OC1IE</name>
              <bitRange>[1:1]</bitRange>
            </field>
            <field>
              <name>OC2IE</name>
              <bitRange>[2:2]</bitRange>
            </field>
            <field>
              <name>OC3IE</name>
              <bitRange>[3:3]</bitRange>
            </field>
            <field>
              <name>OC4IE</name>
              <bitRange>[4:4]</bitRange>
            </field>
            <field>
              <name>BIE</name>
              <bitRange>[7:7]</bitRange>
            </field>
            <field>
              <name>UDE</name>
              <bitRange>[8:8]</bitRange>
            </field>
            <field>
              <name>OC1DE</name>
              <bitRange>[9:9]</bitRange>
            </field>
            <field>
              <name>OC2DE</name>
              <bitRange>[10:10]</bitRange>
            </field>
            <field>
              <name>OC3DE</name>
              <bitRange>[11:11]</bitRange>
            </field>
            <field>
              <name>OC4DE</name>
              <bitRange>[12:12]</bitRange>
            </field>
          </fields>
        </register>
        <register>
          <name>SR</name>
          <addressOffset>0x10</addressOffset>
          <fields>
            <field>
              <name>UIF</name>
              <bitRange>[0:0]</bitRange>
            </field>
            <field>
              <name>OC1IF</name>
              <bitRange>[1:1]</bitRange>
            </field>
            <field>
              <name>OC2IF</name>
              <bitRange>[2:2]</bitRange>
            </field>
            <field>
              <name>OC3IF</name>
              <bitRange>[3:3]</bitRange>
            </field>
            <field>
              <name>OC4IF</name>
              <bitRange>[4:4]</bitRange>
            </field>
            <field>
              <name>BIF</name>
              <bitRange>[7:7]</bitRange>
            </field>
            <field>
              <name>CCR1OK</name>
              <bitRange>[9:9]</bitRange>
            </field>
            <field>
              <name>CCR2OK</name>
              <bitRange>[10:10]</bitRange>
            </field>
            <field>
              <name>CCR3OK</name>
              <bitRange>[11:11]</bitRange>
            </field>
            <field>
              <name>CCR4OK</name>
              <bitRange>[12:12]</bitRange>
            </field>
            <field>
              <name>CNTOK</name>
              <bitRange>[13:13]</bitRange>
            </field>
            <field>
              <name>PSCOK</name>
              <bitRange>[14:14]</bitRange>
            </field>
            <field>
              <name>ARROK</name>
              <bitRange>[15:15]</bitRange>
            </field>
          </fields>
        </register>
        <register>
          <name>EGR</name>
          <addressOffset>0x14</addressOffset>
          <fields>
            <field>
              <name>UG</name>
              <bitRange>[0:0]</bitRange>
            </field>
          </fields>
        </register>
        <register>
          <name>CMR</name>
          <addressOffset>0x18</addressOffset>
          <fields>
            <field>
              <name>OC1M</name>
              <bitRange>[1:0]</bitRange>
            </field>
            <field>
              <name>OC2M</name>
              <bitRange>[3:2]</bitRange>
            </field>
            <field>
              <name>OC3M</name>
              <bitRange>[5:4]</bitRange>
            </field>
            <field>
              <name>OC4M</name>
              <bitRange>[7:6]</bitRange>
            </field>
            <field>
              <name>OC1PE</name>
              <bitRange>[8:8]</bitRange>
            </field>
            <field>
              <name>OC2PE</name>
              <bitRange>[9:9]</bitRange>
            </field>
            <field>
              <name>OC3PE</name>
              <bitRange>[10:10]</bitRange>
            </field>
            <field>
              <name>OC4PE</name>
              <bitRange>[11:11]</bitRange>
            </field>
          </fields>
        </register>
        <register>
          <name>CER</name>
          <addressOffset>0x20</addressOffset>
          <fields>
            <field>
              <name>C1E</name>
              <bitRange>[0:0]</bitRange>
            </field>
            <field>
              <name>C1P</name>
              <bitRange>[1:1]</bitRange>
            </field>
            <field>
              <name>C1NE</name>
              <bitRange>[2:2]</bitRange>
            </field>
            <field>
              <name>C1NP</name>
              <bitRange>[3:3]</bitRange>
            </field>
            <field>
              <name>C2E</name>
              <bitRange>[4:4]</bitRange>
            </field>
            <field>
              <name>C2P</name>
              <bitRange>[5:5]</bitRange>
            </field>
            <field>
              <name>C2NE</name>
              <bitRange>[6:6]</bitRange>
            </field>
            <field>
              <name>C2NP</name>
              <bitRange>[7:7]</bitRange>
            </field>
            <field>
              <name>C3E</name>
              <bitRange>[8:8]</bitRange>
            </field>
            <field>
              <name>C3P</name>
              <bitRange>[9:9]</bitRange>
            </field>
            <field>
              <name>C4E</name>
              <bitRange>[12:12]</bitRange>
            </field>
            <field>
              <name>C4P</name>
              <bitRange>[13:13]</bitRange>
            </field>
          </fields>
        </register>
        <register>
          <name>CNT</name>
          <addressOffset>0x24</addressOffset>
          <fields>
            <field>
              <name>CNT</name>
              <bitRange>[15:0]</bitRange>
            </field>
          </fields>
        </register>
        <register>
          <name>PSC</name>
          <addressOffset>0x28</addressOffset>
          <fields>
            <field>
              <name>PSC</name>
              <bitRange>[15:0]</bitRange>
            </field>
          </fields>
        </register>
        <register>
          <name>ARR</name>
          <addressOffset>0x2C</addressOffset>
          <fields>
            <field>
              <name>ARR</name>
              <bitRange>[15:0]</bitRange>
            </field>
          </fields>
        </register>
        <register>
          <name>CCR1</name>
          <addressOffset>0x34</addressOffset>
          <fields>
            <field>
              <name>CCR1</name>
              <bitRange>[15:0]</bitRange>
            </field>
            <field>
              <name>CCR1_H</name>
              <bitRange>[31:16]</bitRange>
            </field>
          </fields>
        </register>
        <register>
          <name>CCR2</name>
          <addressOffset>0x38</addressOffset>
          <fields>
            <field>
              <name>CCR2</name>
              <bitRange>[15:0]</bitRange>
            </field>
            <field>
              <name>CCR2_H</name>
              <bitRange>[31:16]</bitRange>
            </field>
          </fields>
        </register>
        <register>
          <name>CCR3</name>
          <addressOffset>0x3C</addressOffset>
          <fields>
            <field>
              <name>CCR3</name>
              <bitRange>[15:0]</bitRange>
            </field>
          </fields>
        </register>
        <register>
          <name>CCR4</name>
          <addressOffset>0x40</addressOffset>
          <fields>
            <field>
              <name>CCR4</name>
              <bitRange>[15:0]</bitRange>
            </field>
          </fields>
        </register>
        <register>
          <name>BDTR</name>
          <addressOffset>0x44</addressOffset>
          <fields>
            <field>
              <name>DTG</name>
              <bitRange>[7:0]</bitRange>
            </field>
            <field>
              <name>LOCK</name>
              <bitRange>[9:8]</bitRange>
            </field>
            <field>
              <name>BKE</name>
              <bitRange>[12:12]</bitRange>
            </field>
            <field>
              <name>BKP</name>
              <bitRange>[13:13]</bitRange>
            </field>
            <field>
              <name>AOE</name>
              <bitRange>[14:14]</bitRange>
            </field>
            <field>
              <name>MOE</name>
              <bitRange>[15:15]</bitRange>
            </field>
          </fields>
        </register>
        <register>
          <name>DCR</name>
          <addressOffset>0x48</addressOffset>
          <fields>
            <field>
              <name>DBA</name>
              <bitRange>[4:0]</bitRange>
            </field>
            <field>
              <name>DBL</name>
              <bitRange>[12:8]</bitRange>
            </field>
          </fields>
        </register>
        <register>
          <name>DMAR</name>
          <addressOffset>0x4C</addressOffset>
          <fields>
            <field>
              <name>DMAB</name>
              <bitRange>[31:0]</bitRange>
            </field>
          </fields>
        </register>
      </registers>
    </peripheral>
    <peripheral derivedFrom="PWM1">
      <name>PWM2</name>
      <baseAddress>0x40004000</baseAddress>
    </peripheral>
    <peripheral derivedFrom="PWM1">
      <name>PWM3</name>
      <baseAddress>0x40014000</baseAddress>
    </peripheral>
    <peripheral>
      <name>PWM4</name>
      <groupName>PWM</groupName>
      <baseAddress>0x40017800</baseAddress>
      <addressBlock>
        <offset>0x0</offset>
        <size>0x50</size>
        <usage>registers</usage>
      </addressBlock>
      <registers>
        <register>
          <name>CR1</name>
          <addressOffset>0x0</addressOffset>
          <fields>
            <field>
              <name>CEN</name>
              <bitRange>[0:0]</bitRange>
            </field>
            <field>
              <name>UDIS</name>
              <bitRange>[1:1]</bitRange>
            </field>
            <field>
              <name>URS</name>
              <bitRange>[2:2]</bitRange>
            </field>
            <field>
              <name>DIR</name>
              <bitRange>[4:4]</bitRange>
            </field>
            <field>
              <name>CMS</name>
              <bitRange>[6:5]</bitRange>
            </field>
            <field>
              <name>ARPE</name>
              <bitRange>[7:7]</bitRange>
            </field>
          </fields>
        </register>
        <register>
          <name>DIER</name>
          <addressOffset>0xC</addressOffset>
          <fields>
            <field>
              <name>UIE</name>
              <bitRange>[0:0]</bitRange>
            </field>
            <field>
              <name>OC1IE</name>
              <bitRange>[1:1]</bitRange>
            </field>
            <field>
              <name>OC2IE</name>
              <bitRange>[2:2]</bitRange>
            </field>
            <field>
              <name>OC3IE</name>
              <bitRange>[3:3]</bitRange>
            </field>
            <field>
              <name>OC4IE</name>
              <bitRange>[4:4]</bitRange>
            </field>
            <field>
              <name>UDE</name>
              <bitRange>[8:8]</bitRange>
            </field>
            <field>
              <name>OC1DE</name>
              <bitRange>[9:9]</bitRange>
            </field>
            <field>
              <name>OC2DE</name>
              <bitRange>[10:10]</bitRange>
            </field>
            <field>
              <name>OC3DE</name>
              <bitRange>[11:11]</bitRange>
            </field>
            <field>
              <name>OC4DE</name>
              <bitRange>[12:12]</bitRange>
            </field>
          </fields>
        </register>
        <register>
          <name>SR</name>
          <addressOffset>0x10</addressOffset>
          <fields>
            <field>
              <name>UIF</name>
              <bitRange>[0:0]</bitRange>
            </field>
            <field>
              <name>OC1IF</name>
              <bitRange>[1:1]</bitRange>
            </field>
            <field>
              <name>OC2IF</name>
              <bitRange>[2:2]</bitRange>
            </field>
            <field>
              <name>OC3IF</name>
              <bitRange>[3:3]</bitRange>
            </field>
            <field>
              <name>OC4IF</name>
              <bitRange>[4:4]</bitRange>
            </field>
          </fields>
        </register>
        <register>
          <name>EGR</name>
          <addressOffset>0x14</addressOffset>
          <fields>
            <field>
              <name>UG</name>
              <bitRange>[0:0]</bitRange>
            </field>
          </fields>
        </register>
        <register>
          <name>CMR</name>
          <addressOffset>0x18</addressOffset>
          <fields>
            <field>
              <name>OC1M</name>
              <bitRange>[1:0]</bitRange>
            </field>
            <field>
              <name>OC2M</name>
              <bitRange>[3:2]</bitRange>
            </field>
            <field>
              <name>OC3M</name>
              <bitRange>[5:4]</bitRange>
            </field>
            <field>
              <name>OC4M</name>
              <bitRange>[7:6]</bitRange>
            </field>
            <field>
              <name>OC1PE</name>
              <bitRange>[8:8]</bitRange>
            </field>
            <field>
              <name>OC2PE</name>
              <bitRange>[9:9]</bitRange>
            </field>
            <field>
              <name>OC3PE</name>
              <bitRange>[10:10]</bitRange>
            </field>
            <field>
              <name>OC4PE</name>
              <bitRange>[11:11]</bitRange>
            </field>
          </fields>
        </register>
        <register>
          <name>CER</name>
          <addressOffset>0x20</addressOffset>
          <fields>
            <field>
              <name>C1E</name>
              <bitRange>[0:0]</bitRange>
            </field>
            <field>
              <name>C1P</name>
              <bitRange>[1:1]</bitRange>
            </field>
            <field>
              <name>C2E</name>
              <bitRange>[4:4]</bitRange>
            </field>
            <field>
              <name>C2P</name>
              <bitRange>[5:5]</bitRange>
            </field>
            <field>
              <name>C3E</name>
              <bitRange>[8:8]</bitRange>
            </field>
            <field>
              <name>C3P</name>
              <bitRange>[9:9]</bitRange>
            </field>
            <field>
              <name>C4E</name>
              <bitRange>[12:12]</bitRange>
            </field>
            <field>
              <name>C4P</name>
              <bitRange>[13:13]</bitRange>
            </field>
          </fields>
        </register>
        <register>
          <name>CNT</name>
          <addressOffset>0x24</addressOffset>
          <fields>
            <field>
              <name>CNT</name>
              <bitRange>[15:0]</bitRange>
            </field>
          </fields>
        </register>
        <register>
          <name>PSC</name>
          <addressOffset>0x28</addressOffset>
          <fields>
            <field>
              <name>PSC</name>
              <bitRange>[15:0]</bitRange>
            </field>
          </fields>
        </register>
        <register>
          <name>ARR</name>
          <addressOffset>0x2C</addressOffset>
          <fields>
            <field>
              <name>ARR</name>
              <bitRange>[15:0]</bitRange>
            </field>
          </fields>
        </register>
        <register>
          <name>CCR1</name>
          <addressOffset>0x34</addressOffset>
          <fields>
            <field>
              <name>CCR1</name>
              <bitRange>[15:0]</bitRange>
            </field>
          </fields>
        </register>
        <register>
          <name>CCR2</name>
          <addressOffset>0x38</addressOffset>
          <fields>
            <field>
              <name>CCR2</name>
              <bitRange>[15:0]</bitRange>
            </field>
          </fields>
        </register>
        <register>
          <name>CCR3</name>
          <addressOffset>0x3C</addressOffset>
          <fields>
            <field>
              <name>CCR3</name>
              <bitRange>[15:0]</bitRange>
            </field>
          </fields>
        </register>
        <register>
          <name>CCR4</name>
          <addressOffset>0x40</addressOffset>
          <fields>
            <field>
              <name>CCR4</name>
              <bitRange>[15:0]</bitRange>
            </field>
          </fields>
        </register>
        <register>
          <name>DCR</name>
          <addressOffset>0x48</addressOffset>
          <fields>
            <field>
              <name>DBA</name>
              <bitRange>[4:0]</bitRange>
            </field>
            <field>
              <name>DBL</name>
              <bitRange>[12:8]</bitRange>
            </field>
          </fields>
        </register>
        <register>
          <name>DMAR</name>
          <addressOffset>0x4C</addressOffset>
          <fields>
            <field>
              <name>DMAB</name>
              <bitRange>[31:0]</bitRange>
            </field>
          </fields>
        </register>
      </registers>
    </peripheral>
    <peripheral>
      <name>PWR</name>
      <baseAddress>0x40007000</baseAddress>
      <addressBlock>
        <offset>0x0</offset>
        <size>0x20</size>
        <usage>registers</usage>
      </addressBlock>
      <registers>
        <register>
          <name>CR1</name>
          <addressOffset>0x0</addressOffset>
          <fields>
            <field>
              <name>LPMS</name>
              <bitRange>[1:0]</bitRange>
            </field>
            <field>
              <name>DBP</name>
              <bitRange>[8:8]</bitRange>
            </field>
            <field>
              <name>MR_VSEL</name>
              <bitRange>[13:12]</bitRange>
            </field>
            <field>
              <name>LPR</name>
              <bitRange>[14:14]</bitRange>
            </field>
            <field>
              <name>HSION_CTRL</name>
              <bitRange>[16:16]</bitRange>
            </field>
            <field>
              <name>FLS_WUPT</name>
              <bitRange>[18:17]</bitRange>
            </field>
            <field>
              <name>STDBY_MRRDY_WAIT</name>
              <bitRange>[20:19]</bitRange>
            </field>
          </fields>
        </register>
        <register>
          <name>CR2</name>
          <addressOffset>0x4</addressOffset>
          <fields>
            <field>
              <name>PVDE</name>
              <bitRange>[0:0]</bitRange>
            </field>
            <field>
              <name>PLS</name>
              <bitRange>[3:1]</bitRange>
            </field>
            <field>
              <name>FLTEN</name>
              <bitRange>[8:8]</bitRange>
            </field>
            <field>
              <name>FLT_CTRL</name>
              <bitRange>[11:9]</bitRange>
            </field>
          </fields>
        </register>
        <register>
          <name>CR3</name>
          <addressOffset>0x8</addressOffset>
          <fields>
            <field>
              <name>EWUP1</name>
              <bitRange>[0:0]</bitRange>
            </field>
            <field>
              <name>EWUP2</name>
              <bitRange>[1:1]</bitRange>
            </field>
            <field>
              <name>EWUP3</name>
              <bitRange>[2:2]</bitRange>
            </field>
            <field>
              <name>EWUP4</name>
              <bitRange>[3:3]</bitRange>
            </field>
            <field>
              <name>EWUP5</name>
              <bitRange>[4:4]</bitRange>
            </field>
            <field>
              <name>RRS</name>
              <bitRange>[8:8]</bitRange>
            </field>
          </fields>
        </register>
        <register>
          <name>CR4</name>
          <addressOffset>0xC</addressOffset>
          <fields>
            <field>
              <name>WP1</name>
              <bitRange>[0:0]</bitRange>
            </field>
            <field>
              <name>WP2</name>
              <bitRange>[1:1]</bitRange>
            </field>
            <field>
              <name>WP3</name>
              <bitRange>[2:2]</bitRange>
            </field>
            <field>
              <name>WP4</name>
              <bitRange>[3:3]</bitRange>
            </field>
            <field>
              <name>WP5</name>
              <bitRange>[4:4]</bitRange>
            </field>
          </fields>
        </register>
        <register>
          <name>SR</name>
          <addressOffset>0x10</addressOffset>
          <fields>
            <field>
              <name>WUF1</name>
              <bitRange>[0:0]</bitRange>
              <access>read-only</access>
            </field>
            <field>
              <name>WUF2</name>
              <bitRange>[1:1]</bitRange>
              <access>read-only</access>
            </field>
            <field>
              <name>WUF3</name>
              <bitRange>[2:2]</bitRange>
              <access>read-only</access>
            </field>
            <field>
              <name>WUF4</name>
              <bitRange>[3:3]</bitRange>
              <access>read-only</access>
            </field>
            <field>
              <name>WUF5</name>
              <bitRange>[4:4]</bitRange>
              <access>read-only</access>
            </field>
            <field>
              <name>SBF</name>
              <bitRange>[8:8]</bitRange>
              <access>read-only</access>
            </field>
            <field>
              <name>MR_RDY</name>
              <bitRange>[9:9]</bitRange>
              <access>read-only</access>
            </field>
            <field>
              <name>PVDO</name>
              <bitRange>[16:16]</bitRange>
              <access>read-only</access>
            </field>
          </fields>
        </register>
        <register>
          <name>SCR</name>
          <addressOffset>0x14</addressOffset>
          <fields>
            <field>
              <name>CWUF1</name>
              <bitRange>[0:0]</bitRange>
            </field>
            <field>
              <name>CWUF2</name>
              <bitRange>[1:1]</bitRange>
            </field>
            <field>
              <name>CWUF3</name>
              <bitRange>[2:2]</bitRange>
            </field>
            <field>
              <name>CWUF4</name>
              <bitRange>[3:3]</bitRange>
            </field>
            <field>
              <name>CWUF5</name>
              <bitRange>[4:4]</bitRange>
            </field>
            <field>
              <name>CSBF</name>
              <bitRange>[8:8]</bitRange>
            </field>
          </fields>
        </register>
      </registers>
    </peripheral>
    <peripheral>
      <name>RCC</name>
      <description>desc RCC</description>
      <baseAddress>0x40021000</baseAddress>
      <addressBlock>
        <offset>0x0</offset>
        <size>0x400</size>
        <usage>registers</usage>
      </addressBlock>
      <interrupt>
        <name>RCC_CTC</name>
        <description>RCC global Interrupt</description>
        <value>5</value>
      </interrupt>
      <registers>
        <register>
          <name>CR</name>
          <description>clock control register</description>
          <addressOffset>0x0</addressOffset>
          <fields>
            <field>
              <name>HSION</name>
              <bitRange>[0:0]</bitRange>
            </field>
            <field>
              <name>HSIRDY</name>
              <bitRange>[1:1]</bitRange>
              <access>read-only</access>
            </field>
            <field>
              <name>HSIKERON</name>
              <bitRange>[3:3]</bitRange>
            </field>
            <field>
              <name>HSITRIM</name>
              <bitRange>[14:4]</bitRange>
            </field>
            <field>
              <name>HSEON</name>
              <bitRange>[16:16]</bitRange>
            </field>
            <field>
              <name>HSERDY</name>
              <bitRange>[17:17]</bitRange>
              <access>read-only</access>
            </field>
            <field>
              <name>HSEBYP</name>
              <bitRange>[18:18]</bitRange>
            </field>
            <field>
              <name>CSSON</name>
              <bitRange>[19:19]</bitRange>
            </field>
            <field>
              <name>PLLON</name>
              <bitRange>[24:24]</bitRange>
            </field>
            <field>
              <name>PLLRDY</name>
              <bitRange>[25:25]</bitRange>
              <access>read-only</access>
            </field>
            <field>
              <name>HSIFS</name>
              <bitRange>[27:26]</bitRange>
            </field>
          </fields>
        </register>
        <register>
          <name>CFGR</name>
          <description>clock configuration register</description>
          <addressOffset>0x4</addressOffset>
          <fields>
            <field>
              <name>SW</name>
              <bitRange>[1:0]</bitRange>
            </field>
            <field>
              <name>SWS</name>
              <bitRange>[3:2]</bitRange>
            </field>
            <field>
              <name>HPRE</name>
              <bitRange>[7:4]</bitRange>
            </field>
            <field>
              <name>PPRE1</name>
              <bitRange>[10:8]</bitRange>
            </field>
            <field>
              <name>PPRE2</name>
              <bitRange>[13:11]</bitRange>
            </field>
            <field>
              <name>MCO</name>
              <bitRange>[27:24]</bitRange>
            </field>
          </fields>
        </register>
        <register>
          <name>CIR</name>
          <description>clock interrupt register</description>
          <addressOffset>0x8</addressOffset>
          <fields>
            <field>
              <name>LSIRDYF</name>
              <bitRange>[0:0]</bitRange>
              <access>read-only</access>
            </field>
            <field>
              <name>LSERDYF</name>
              <bitRange>[1:1]</bitRange>
              <access>read-only</access>
            </field>
            <field>
              <name>HSIRDYF</name>
              <bitRange>[2:2]</bitRange>
              <access>read-only</access>
            </field>
            <field>
              <name>HSERDYF</name>
              <bitRange>[3:3]</bitRange>
              <access>read-only</access>
            </field>
            <field>
              <name>PLLRDYF</name>
              <bitRange>[4:4]</bitRange>
              <access>read-only</access>
            </field>
            <field>
              <name>CSSF</name>
              <bitRange>[7:7]</bitRange>
              <access>read-only</access>
            </field>
            <field>
              <name>LSIRDYIE</name>
              <bitRange>[8:8]</bitRange>
            </field>
            <field>
              <name>LSERDYIE</name>
              <bitRange>[9:9]</bitRange>
            </field>
            <field>
              <name>HSIRDYIE</name>
              <bitRange>[10:10]</bitRange>
            </field>
            <field>
              <name>HSERDYIE</name>
              <bitRange>[11:11]</bitRange>
            </field>
            <field>
              <name>PLLRDYIE</name>
              <bitRange>[12:12]</bitRange>
            </field>
            <field>
              <name>LSIRDYC</name>
              <bitRange>[16:16]</bitRange>
            </field>
            <field>
              <name>LSERDYC</name>
              <bitRange>[17:17]</bitRange>
            </field>
            <field>
              <name>HSIRDYC</name>
              <bitRange>[18:18]</bitRange>
            </field>
            <field>
              <name>HSERDYC</name>
              <bitRange>[19:19]</bitRange>
            </field>
            <field>
              <name>PLLRDYC</name>
              <bitRange>[20:20]</bitRange>
            </field>
            <field>
              <name>CSSC</name>
              <bitRange>[23:23]</bitRange>
            </field>
          </fields>
        </register>
        <register>
          <name>AHBRSTR</name>
          <addressOffset>0x28</addressOffset>
          <fields>
            <field>
              <name>DMA1RST</name>
              <bitRange>[0:0]</bitRange>
            </field>
            <field>
              <name>CRCRST</name>
              <bitRange>[6:6]</bitRange>
            </field>
            <field>
              <name>IOPARST</name>
              <bitRange>[8:8]</bitRange>
            </field>
            <field>
              <name>IOPBRST</name>
              <bitRange>[9:9]</bitRange>
            </field>
            <field>
              <name>IOPCRST</name>
              <bitRange>[10:10]</bitRange>
            </field>
            <field>
              <name>IOPDRST</name>
              <bitRange>[11:11]</bitRange>
            </field>
          </fields>
        </register>
        <register>
          <name>APB1RSTR1</name>
          <addressOffset>0x38</addressOffset>
          <fields>
            <field>
              <name>TIM2RST</name>
              <bitRange>[0:0]</bitRange>
            </field>
            <field>
              <name>TIM3RST</name>
              <bitRange>[1:1]</bitRange>
            </field>
            <field>
              <name>TIM4RST</name>
              <bitRange>[2:2]</bitRange>
            </field>
            <field>
              <name>TIM6RST</name>
              <bitRange>[4:4]</bitRange>
            </field>
            <field>
              <name>TIM7RST</name>
              <bitRange>[5:5]</bitRange>
            </field>
            <field>
              <name>WWDGRST</name>
              <bitRange>[11:11]</bitRange>
            </field>
            <field>
              <name>PWM1RST</name>
              <bitRange>[12:12]</bitRange>
            </field>
            <field>
              <name>PWM2RST</name>
              <bitRange>[13:13]</bitRange>
            </field>
            <field>
              <name>SPI2RST</name>
              <bitRange>[14:14]</bitRange>
            </field>
            <field>
              <name>UART1RST</name>
              <bitRange>[19:19]</bitRange>
            </field>
            <field>
              <name>UART2RST</name>
              <bitRange>[20:20]</bitRange>
            </field>
            <field>
              <name>I2C1RST</name>
              <bitRange>[21:21]</bitRange>
            </field>
            <field>
              <name>I2C2RST</name>
              <bitRange>[22:22]</bitRange>
            </field>
            <field>
              <name>PWRRST</name>
              <bitRange>[28:28]</bitRange>
            </field>
          </fields>
        </register>
        <register>
          <name>APB1RSTR2</name>
          <addressOffset>0x3C</addressOffset>
          <fields>
            <field>
              <name>LPTIM1RST</name>
              <bitRange>[0:0]</bitRange>
            </field>
            <field>
              <name>LPUART1RST</name>
              <bitRange>[1:1]</bitRange>
            </field>
          </fields>
        </register>
        <register>
          <name>APB2RSTR</name>
          <description>APB2 peripheral reset register</description>
          <addressOffset>0x40</addressOffset>
          <fields>
            <field>
              <name>SYSCFGRST</name>
              <bitRange>[0:0]</bitRange>
            </field>
            <field>
              <name>ADC1RST</name>
              <bitRange>[9:9]</bitRange>
            </field>
            <field>
              <name>TIM1RST</name>
              <bitRange>[11:11]</bitRange>
            </field>
            <field>
              <name>SPI1RST</name>
              <bitRange>[12:12]</bitRange>
            </field>
            <field>
              <name>USART1RST</name>
              <bitRange>[14:14]</bitRange>
            </field>
            <field>
              <name>PWM3RST</name>
              <bitRange>[16:16]</bitRange>
            </field>
            <field>
              <name>PWM4RST</name>
              <bitRange>[17:17]</bitRange>
            </field>
            <field>
              <name>TIM15RST</name>
              <bitRange>[22:22]</bitRange>
            </field>
            <field>
              <name>TIM16RST</name>
              <bitRange>[23:23]</bitRange>
            </field>
            <field>
              <name>TIM17RST</name>
              <bitRange>[24:24]</bitRange>
            </field>
            <field>
              <name>COMPRST</name>
              <bitRange>[27:27]</bitRange>
            </field>
            <field>
              <name>OPAMPRST</name>
              <bitRange>[28:28]</bitRange>
            </field>
          </fields>
        </register>
        <register>
          <name>AHBENR</name>
          <addressOffset>0x48</addressOffset>
          <fields>
            <field>
              <name>DMA1EN</name>
              <bitRange>[0:0]</bitRange>
            </field>
            <field>
              <name>SRAMEN</name>
              <bitRange>[2:2]</bitRange>
            </field>
            <field>
              <name>FMCEN</name>
              <bitRange>[4:4]</bitRange>
            </field>
            <field>
              <name>CRCEN</name>
              <bitRange>[6:6]</bitRange>
            </field>
            <field>
              <name>IOPAEN</name>
              <bitRange>[8:8]</bitRange>
            </field>
            <field>
              <name>IOPBEN</name>
              <bitRange>[9:9]</bitRange>
            </field>
            <field>
              <name>IOPCEN</name>
              <bitRange>[10:10]</bitRange>
            </field>
            <field>
              <name>IOPDEN</name>
              <bitRange>[11:11]</bitRange>
            </field>
          </fields>
        </register>
        <register>
          <name>APB1ENR1</name>
          <addressOffset>0x58</addressOffset>
          <fields>
            <field>
              <name>TIM2EN</name>
              <bitRange>[0:0]</bitRange>
            </field>
            <field>
              <name>TIM3EN</name>
              <bitRange>[1:1]</bitRange>
            </field>
            <field>
              <name>TIM4EN</name>
              <bitRange>[2:2]</bitRange>
            </field>
            <field>
              <name>TIM6EN</name>
              <bitRange>[4:4]</bitRange>
            </field>
            <field>
              <name>TIM7EN</name>
              <bitRange>[5:5]</bitRange>
            </field>
            <field>
              <name>WWDGEN</name>
              <bitRange>[11:11]</bitRange>
            </field>
            <field>
              <name>PWM1EN</name>
              <bitRange>[12:12]</bitRange>
            </field>
            <field>
              <name>PWM2EN</name>
              <bitRange>[13:13]</bitRange>
            </field>
            <field>
              <name>SPI2EN</name>
              <bitRange>[14:14]</bitRange>
            </field>
            <field>
              <name>UART1EN</name>
              <bitRange>[19:19]</bitRange>
            </field>
            <field>
              <name>UART2EN</name>
              <bitRange>[20:20]</bitRange>
            </field>
            <field>
              <name>I2C1EN</name>
              <bitRange>[21:21]</bitRange>
            </field>
            <field>
              <name>I2C2EN</name>
              <bitRange>[22:22]</bitRange>
            </field>
            <field>
              <name>PWREN</name>
              <bitRange>[28:28]</bitRange>
            </field>
          </fields>
        </register>
        <register>
          <name>APB1ENR2</name>
          <addressOffset>0x5C</addressOffset>
          <fields>
            <field>
              <name>LPTIM1EN</name>
              <bitRange>[0:0]</bitRange>
            </field>
            <field>
              <name>LPUART1EN</name>
              <bitRange>[1:1]</bitRange>
            </field>
          </fields>
        </register>
        <register>
          <name>APB2ENR</name>
          <description>APB2 peripheral clock enable register</description>
          <addressOffset>0x60</addressOffset>
          <fields>
            <field>
              <name>SYSCFGEN</name>
              <bitRange>[0:0]</bitRange>
            </field>
            <field>
              <name>ADC1EN</name>
              <bitRange>[9:9]</bitRange>
            </field>
            <field>
              <name>TIM1EN</name>
              <bitRange>[11:11]</bitRange>
            </field>
            <field>
              <name>SPI1EN</name>
              <bitRange>[12:12]</bitRange>
            </field>
            <field>
              <name>USART1EN</name>
              <bitRange>[14:14]</bitRange>
            </field>
            <field>
              <name>PWM3EN</name>
              <bitRange>[16:16]</bitRange>
            </field>
            <field>
              <name>PWM4EN</name>
              <bitRange>[17:17]</bitRange>
            </field>
            <field>
              <name>TIM15EN</name>
              <bitRange>[22:22]</bitRange>
            </field>
            <field>
              <name>TIM16EN</name>
              <bitRange>[23:23]</bitRange>
            </field>
            <field>
              <name>TIM17EN</name>
              <bitRange>[24:24]</bitRange>
            </field>
            <field>
              <name>COMPEN</name>
              <bitRange>[27:27]</bitRange>
            </field>
            <field>
              <name>OPAMPEN</name>
              <bitRange>[28:28]</bitRange>
            </field>
          </fields>
        </register>
        <register>
          <name>CCIPR</name>
          <addressOffset>0x68</addressOffset>
          <fields>
            <field>
              <name>USART1SEL</name>
              <bitRange>[1:0]</bitRange>
            </field>
            <field>
              <name>LPUART1SEL</name>
              <bitRange>[13:12]</bitRange>
            </field>
            <field>
              <name>LPTIM1SEL</name>
              <bitRange>[15:14]</bitRange>
            </field>
            <field>
              <name>COMP1SEL</name>
              <bitRange>[17:16]</bitRange>
            </field>
            <field>
              <name>COMP2SEL</name>
              <bitRange>[19:18]</bitRange>
            </field>
            <field>
              <name>ADC1SEL</name>
              <bitRange>[25:24]</bitRange>
            </field>
            <field>
              <name>OPAMP2SEL</name>
              <bitRange>[31:30]</bitRange>
            </field>
          </fields>
        </register>
        <register>
          <name>BDCR</name>
          <description>Backup domain control register</description>
          <addressOffset>0x70</addressOffset>
          <fields>
            <field>
              <name>LSEON</name>
              <bitRange>[0:0]</bitRange>
            </field>
            <field>
              <name>LSERDY</name>
              <bitRange>[1:1]</bitRange>
              <access>read-only</access>
            </field>
            <field>
              <name>LSEBYP</name>
              <bitRange>[2:2]</bitRange>
            </field>
            <field>
              <name>LSEDRV</name>
              <bitRange>[4:3]</bitRange>
            </field>
            <field>
              <name>RTCSEL</name>
              <bitRange>[9:8]</bitRange>
            </field>
            <field>
              <name>RTCEN</name>
              <bitRange>[15:15]</bitRange>
            </field>
            <field>
              <name>BDRST</name>
              <bitRange>[16:16]</bitRange>
            </field>
          </fields>
        </register>
        <register>
          <name>CSR</name>
          <description>clock control &amp; status register</description>
          <addressOffset>0x74</addressOffset>
          <fields>
            <field>
              <name>LSION</name>
              <bitRange>[0:0]</bitRange>
            </field>
            <field>
              <name>LSIRDY</name>
              <bitRange>[1:1]</bitRange>
              <access>read-only</access>
            </field>
            <field>
              <name>RMVF</name>
              <bitRange>[24:24]</bitRange>
            </field>
            <field>
              <name>OBLRSTF</name>
              <bitRange>[25:25]</bitRange>
              <access>read-only</access>
            </field>
            <field>
              <name>PINRSTF</name>
              <bitRange>[26:26]</bitRange>
              <access>read-only</access>
            </field>
            <field>
              <name>PWRRSTF</name>
              <bitRange>[27:27]</bitRange>
              <access>read-only</access>
            </field>
            <field>
              <name>SFTRSTF</name>
              <bitRange>[28:28]</bitRange>
              <access>read-only</access>
            </field>
            <field>
              <name>IWDGRSTF</name>
              <bitRange>[29:29]</bitRange>
              <access>read-only</access>
            </field>
            <field>
              <name>WWDGRSTF</name>
              <bitRange>[30:30]</bitRange>
              <access>read-only</access>
            </field>
            <field>
              <name>LPWRRSTF</name>
              <bitRange>[31:31]</bitRange>
              <access>read-only</access>
            </field>
          </fields>
        </register>
        <register>
          <name>CFGR1</name>
          <description>clock configuration register 1</description>
          <addressOffset>0x78</addressOffset>
          <fields>
            <field>
              <name>MCOPRE</name>
              <bitRange>[3:0]</bitRange>
            </field>
            <field>
              <name>PVDSEL</name>
              <bitRange>[30:29]</bitRange>
            </field>
          </fields>
        </register>
        <register>
          <name>CFGR2</name>
          <description>desc CFGR2</description>
          <addressOffset>0x7C</addressOffset>
          <fields>
            <field>
              <name>HSEDRV</name>
              <bitRange>[9:8]</bitRange>
            </field>
          </fields>
        </register>
        <register>
          <name>CFGR3</name>
          <addressOffset>0x80</addressOffset>
          <fields>
            <field>
              <name>PLLSRC</name>
              <bitRange>[0:0]</bitRange>
            </field>
            <field>
              <name>PLLMUL</name>
              <bitRange>[10:8]</bitRange>
            </field>
          </fields>
        </register>
      </registers>
    </peripheral>
    <peripheral>
      <name>RTC</name>
      <baseAddress>0x40002800</baseAddress>
      <addressBlock>
        <offset>0x0</offset>
        <size>0x60</size>
        <usage>registers</usage>
      </addressBlock>
      <interrupt>
        <name>TAMPER</name>
        <description>Intrusion detection global interrupt</description>
        <value>2</value>
      </interrupt>
      <interrupt>
        <name>RTC</name>
        <description>RTC global interrupt</description>
        <value>3</value>
      </interrupt>
      <registers>
        <register>
          <name>CRH</name>
          <addressOffset>0x0</addressOffset>
          <fields>
            <field>
              <name>SECIE</name>
              <description>Second interrupt enable</description>
              <bitRange>[0:0]</bitRange>
            </field>
            <field>
              <name>ALRIE</name>
              <description>Alarm interrupt enable</description>
              <bitRange>[1:1]</bitRange>
            </field>
            <field>
              <name>OWIE</name>
              <description>Overflow interrupt enable</description>
              <bitRange>[2:2]</bitRange>
            </field>
          </fields>
        </register>
        <register>
          <name>CRL</name>
          <addressOffset>0x4</addressOffset>
          <fields>
            <field>
              <name>SECF</name>
              <description>Second flag</description>
              <bitRange>[0:0]</bitRange>
            </field>
            <field>
              <name>ALRF</name>
              <description>Alarm flag</description>
              <bitRange>[1:1]</bitRange>
            </field>
            <field>
              <name>OWF</name>
              <description>Overflow flag</description>
              <bitRange>[2:2]</bitRange>
            </field>
            <field>
              <name>RSF</name>
              <description>Registers synchronized flag</description>
              <bitRange>[3:3]</bitRange>
            </field>
            <field>
              <name>CNF</name>
              <description>Configuration flag</description>
              <bitRange>[4:4]</bitRange>
            </field>
            <field>
              <name>RTOFF</name>
              <description>RTC operation OFF</description>
              <bitRange>[5:5]</bitRange>
              <access>read-only</access>
            </field>
          </fields>
        </register>
        <register>
          <name>PRLH</name>
          <addressOffset>0x8</addressOffset>
          <fields>
            <field>
              <name>PRL</name>
              <description>RTC pre-scaler reload value high part</description>
              <bitRange>[3:0]</bitRange>
            </field>
          </fields>
        </register>
        <register>
          <name>PRLL</name>
          <addressOffset>0xC</addressOffset>
          <fields>
            <field>
              <name>PRL</name>
              <description>RTC pre-scaler reload value low part</description>
              <bitRange>[15:0]</bitRange>
            </field>
          </fields>
        </register>
        <register>
          <name>DIVH</name>
          <addressOffset>0x10</addressOffset>
          <fields>
            <field>
              <name>RTC_DIV</name>
              <description>RTC clock divider high part</description>
              <bitRange>[3:0]</bitRange>
              <access>read-only</access>
            </field>
          </fields>
        </register>
        <register>
          <name>DIVL</name>
          <addressOffset>0x14</addressOffset>
          <fields>
            <field>
              <name>RTC_DIV</name>
              <description>RTC clock divider low part</description>
              <bitRange>[15:0]</bitRange>
              <access>read-only</access>
            </field>
          </fields>
        </register>
        <register>
          <name>CNTH</name>
          <addressOffset>0x18</addressOffset>
          <fields>
            <field>
              <name>RTC_CNT</name>
              <description>RTC counter high part</description>
              <bitRange>[15:0]</bitRange>
            </field>
          </fields>
        </register>
        <register>
          <name>CNTL</name>
          <addressOffset>0x1C</addressOffset>
          <fields>
            <field>
              <name>RTC_CNT</name>
              <description>RTC counter high part</description>
              <bitRange>[15:0]</bitRange>
            </field>
          </fields>
        </register>
        <register>
          <name>ALRH</name>
          <addressOffset>0x20</addressOffset>
          <fields>
            <field>
              <name>RTC_ALR</name>
              <description>RTC alarm high part</description>
              <bitRange>[15:0]</bitRange>
            </field>
          </fields>
        </register>
        <register>
          <name>ALRL</name>
          <addressOffset>0x24</addressOffset>
          <fields>
            <field>
              <name>RTC_ALR</name>
              <description>RTC alarm low part</description>
              <bitRange>[15:0]</bitRange>
            </field>
          </fields>
        </register>
        <register>
          <name>TMPCFGR</name>
          <addressOffset>0x30</addressOffset>
          <fields>
            <field>
              <name>TPE</name>
              <description>TAMP enable</description>
              <bitRange>[0:0]</bitRange>
            </field>
            <field>
              <name>TPAL</name>
              <description>TAMPER pin interrupt enable</description>
              <bitRange>[1:1]</bitRange>
            </field>
          </fields>
        </register>
        <register>
          <name>TMPCSR</name>
          <addressOffset>0x34</addressOffset>
          <fields>
            <field>
              <name>CTE</name>
              <description>clear TAMP event</description>
              <bitRange>[0:0]</bitRange>
            </field>
            <field>
              <name>CTI</name>
              <description>clear TAMP interrupt</description>
              <bitRange>[1:1]</bitRange>
            </field>
            <field>
              <name>TPIE</name>
              <description>TAMP interrupt enable</description>
              <bitRange>[2:2]</bitRange>
            </field>
            <field>
              <name>TEF</name>
              <description>TAMP event flag</description>
              <bitRange>[8:8]</bitRange>
              <access>read-only</access>
            </field>
            <field>
              <name>TIF</name>
              <description>TAMP interrupt flag</description>
              <bitRange>[9:9]</bitRange>
              <access>read-only</access>
            </field>
          </fields>
        </register>
        <register>
          <name>CALIBR</name>
          <addressOffset>0x38</addressOffset>
          <fields>
            <field>
              <name>CAL</name>
              <description>RTC calibration value</description>
              <bitRange>[6:0]</bitRange>
            </field>
            <field>
              <name>CCO</name>
              <description>Calibration clock output</description>
              <bitRange>[7:7]</bitRange>
            </field>
            <field>
              <name>ASOE</name>
              <description>Alarm or second output enable</description>
              <bitRange>[8:8]</bitRange>
            </field>
            <field>
              <name>ASOS</name>
              <description>Alarm or second output selection</description>
              <bitRange>[9:9]</bitRange>
            </field>
          </fields>
        </register>
        <register>
          <name>BKP_DR0</name>
          <addressOffset>0x40</addressOffset>
          <fields>
            <field>
              <name>D</name>
              <description>bakeup data word0</description>
              <bitRange>[31:0]</bitRange>
            </field>
          </fields>
        </register>
        <register>
          <name>BKP_DR1</name>
          <addressOffset>0x44</addressOffset>
          <fields>
            <field>
              <name>D</name>
              <description>bakeup data word1</description>
              <bitRange>[31:0]</bitRange>
            </field>
          </fields>
        </register>
        <register>
          <name>BKP_DR2</name>
          <addressOffset>0x48</addressOffset>
          <fields>
            <field>
              <name>D</name>
              <description>bakeup data word2</description>
              <bitRange>[31:0]</bitRange>
            </field>
          </fields>
        </register>
        <register>
          <name>BKP_DR3</name>
          <addressOffset>0x4C</addressOffset>
          <fields>
            <field>
              <name>D</name>
              <description>bakeup data word3</description>
              <bitRange>[31:0]</bitRange>
            </field>
          </fields>
        </register>
        <register>
          <name>BKP_DR4</name>
          <addressOffset>0x50</addressOffset>
          <fields>
            <field>
              <name>D</name>
              <description>bakeup data word4</description>
              <bitRange>[31:0]</bitRange>
            </field>
          </fields>
        </register>
      </registers>
    </peripheral>
    <peripheral>
      <name>SPI1</name>
      <groupName>SPI</groupName>
      <baseAddress>0x40013000</baseAddress>
      <addressBlock>
        <offset>0x0</offset>
        <size>0x30</size>
        <usage>registers</usage>
      </addressBlock>
      <registers>
        <register>
          <name>CR1</name>
          <addressOffset>0x0</addressOffset>
          <fields>
            <field>
              <name>CPHA</name>
              <description>Clock Phase</description>
              <bitRange>[0:0]</bitRange>
            </field>
            <field>
              <name>CPOL</name>
              <description>Clock Polarity</description>
              <bitRange>[1:1]</bitRange>
            </field>
            <field>
              <name>MSTR</name>
              <description>Master Selection</description>
              <bitRange>[2:2]</bitRange>
            </field>
            <field>
              <name>BR</name>
              <description>Baud Rate Control</description>
              <bitRange>[5:3]</bitRange>
            </field>
            <field>
              <name>SPE</name>
              <description>SPI Enable</description>
              <bitRange>[6:6]</bitRange>
            </field>
            <field>
              <name>LSBFIRST</name>
              <description>Frame Format</description>
              <bitRange>[7:7]</bitRange>
            </field>
            <field>
              <name>SSI</name>
              <description>Internal slave select</description>
              <bitRange>[8:8]</bitRange>
            </field>
            <field>
              <name>SSM</name>
              <description>Software slave management</description>
              <bitRange>[9:9]</bitRange>
            </field>
            <field>
              <name>RXONLY</name>
              <description>Receive only</description>
              <bitRange>[10:10]</bitRange>
            </field>
            <field>
              <name>DFF</name>
              <description>Data frame format</description>
              <bitRange>[11:11]</bitRange>
            </field>
            <field>
              <name>CRCNEXT</name>
              <description>Transmit CRC next</description>
              <bitRange>[12:12]</bitRange>
            </field>
            <field>
              <name>CRCEN</name>
              <description>Hardware CRC calculation enable</description>
              <bitRange>[13:13]</bitRange>
            </field>
            <field>
              <name>BIDIOE</name>
              <description>Output enable in bidirectional mode</description>
              <bitRange>[14:14]</bitRange>
            </field>
            <field>
              <name>BIDIMODE</name>
              <description>Bidirectional data mode enable</description>
              <bitRange>[15:15]</bitRange>
            </field>
          </fields>
        </register>
        <register>
          <name>CR2</name>
          <addressOffset>0x4</addressOffset>
          <fields>
            <field>
              <name>RXDMAEN</name>
              <description>Rx buffer DMA enable</description>
              <bitRange>[0:0]</bitRange>
            </field>
            <field>
              <name>TXDMAEN</name>
              <description>Tx buffer DMA enable</description>
              <bitRange>[1:1]</bitRange>
            </field>
            <field>
              <name>SSOE</name>
              <description>SS Output Enable</description>
              <bitRange>[2:2]</bitRange>
            </field>
            <field>
              <name>CLRTXFIFO</name>
              <description>Clear FIFO</description>
              <bitRange>[4:4]</bitRange>
            </field>
            <field>
              <name>ERRIE</name>
              <description>Error Interrupt Enable</description>
              <bitRange>[5:5]</bitRange>
            </field>
            <field>
              <name>RXNEIE</name>
              <description>RX buffer Not Empty Interrupt Enable</description>
              <bitRange>[6:6]</bitRange>
            </field>
            <field>
              <name>TXEIE</name>
              <description>Tx buffer Empty Interrupt Enable</description>
              <bitRange>[7:7]</bitRange>
            </field>
            <field>
              <name>FRXTH</name>
              <bitRange>[12:12]</bitRange>
            </field>
            <field>
              <name>CLK_SEL</name>
              <bitRange>[14:14]</bitRange>
            </field>
            <field>
              <name>FRF</name>
              <bitRange>[15:15]</bitRange>
            </field>
          </fields>
        </register>
        <register>
          <name>SR</name>
          <addressOffset>0x8</addressOffset>
          <fields>
            <field>
              <name>RXNE</name>
              <description>Receive buffer Not Empty</description>
              <bitRange>[0:0]</bitRange>
              <access>read-only</access>
            </field>
            <field>
              <name>TXE</name>
              <description>Transmit buffer Empty</description>
              <bitRange>[1:1]</bitRange>
              <access>read-only</access>
            </field>
            <field>
              <name>CHSIDE</name>
              <description>Channel side</description>
              <bitRange>[2:2]</bitRange>
              <access>read-only</access>
            </field>
            <field>
              <name>UDR</name>
              <description>Underrun flag</description>
              <bitRange>[3:3]</bitRange>
              <access>read-only</access>
            </field>
            <field>
              <name>CRCERR</name>
              <description>CRC error flag</description>
              <bitRange>[4:4]</bitRange>
            </field>
            <field>
              <name>MODF</name>
              <description>Mode fault</description>
              <bitRange>[5:5]</bitRange>
            </field>
            <field>
              <name>OVR</name>
              <description>Overrun flag</description>
              <bitRange>[6:6]</bitRange>
              <access>read-only</access>
            </field>
            <field>
              <name>BSY</name>
              <description>Busy flag</description>
              <bitRange>[7:7]</bitRange>
              <access>read-only</access>
            </field>
            <field>
              <name>FRE</name>
              <bitRange>[8:8]</bitRange>
              <access>read-only</access>
            </field>
            <field>
              <name>FRLVL</name>
              <description>FIFO Reception Level</description>
              <bitRange>[10:9]</bitRange>
              <access>read-only</access>
            </field>
            <field>
              <name>FTLVL</name>
              <description>FIFO Transmission Level</description>
              <bitRange>[12:11]</bitRange>
              <access>read-only</access>
            </field>
          </fields>
        </register>
        <register>
          <name>DR</name>
          <addressOffset>0xC</addressOffset>
          <fields>
            <field>
              <name>DR</name>
              <description>Data Register</description>
              <bitRange>[15:0]</bitRange>
            </field>
          </fields>
        </register>
        <register>
          <name>CRCPR</name>
          <addressOffset>0x10</addressOffset>
          <fields>
            <field>
              <name>CRCPOLY</name>
              <description>CRC polynomial register</description>
              <bitRange>[15:0]</bitRange>
            </field>
          </fields>
        </register>
        <register>
          <name>RXCRCR</name>
          <addressOffset>0x14</addressOffset>
          <fields>
            <field>
              <name>RXCRC</name>
              <description>rcv crc reg</description>
              <bitRange>[15:0]</bitRange>
              <access>read-only</access>
            </field>
          </fields>
        </register>
        <register>
          <name>TXCRCR</name>
          <addressOffset>0x18</addressOffset>
          <fields>
            <field>
              <name>TXCRC</name>
              <description>tx crc reg</description>
              <bitRange>[15:0]</bitRange>
              <access>read-only</access>
            </field>
          </fields>
        </register>
        <register>
          <name>I2S_CFGR</name>
          <addressOffset>0x1C</addressOffset>
          <fields>
            <field>
              <name>CHLEN</name>
              <description>Channel length (number of bits per audio channel</description>
              <bitRange>[0:0]</bitRange>
            </field>
            <field>
              <name>DATLEN</name>
              <description>Data length to be transferred</description>
              <bitRange>[2:1]</bitRange>
            </field>
            <field>
              <name>CKPOL</name>
              <description>Steady state clock polarity</description>
              <bitRange>[3:3]</bitRange>
            </field>
            <field>
              <name>I2SSTD</name>
              <description>I2S standard selection</description>
              <bitRange>[5:4]</bitRange>
            </field>
            <field>
              <name>PCMSYNC</name>
              <description>PCM frame synchronization</description>
              <bitRange>[7:7]</bitRange>
            </field>
            <field>
              <name>I2SCFG</name>
              <description>I2S configuration mode</description>
              <bitRange>[9:8]</bitRange>
            </field>
            <field>
              <name>I2SE</name>
              <description>I2S enable</description>
              <bitRange>[10:10]</bitRange>
            </field>
            <field>
              <name>I2SMOD</name>
              <description>I2S mode selection</description>
              <bitRange>[11:11]</bitRange>
            </field>
          </fields>
        </register>
        <register>
          <name>I2SPR</name>
          <addressOffset>0x20</addressOffset>
          <fields>
            <field>
              <name>I2SDIV</name>
              <description>I2S linear prescaler</description>
              <bitRange>[7:0]</bitRange>
            </field>
            <field>
              <name>ODD</name>
              <description>Odd factor for the prescaler</description>
              <bitRange>[8:8]</bitRange>
            </field>
            <field>
              <name>MCKOE</name>
              <description>Master clock output enable</description>
              <bitRange>[9:9]</bitRange>
            </field>
          </fields>
        </register>
      </registers>
    </peripheral>
    <peripheral derivedFrom="SPI1">
      <name>SPI2</name>
      <baseAddress>0x40003800</baseAddress>
    </peripheral>
    <peripheral>
      <name>SYSCFG</name>
      <baseAddress>0x40010000</baseAddress>
      <addressBlock>
        <offset>0x0</offset>
        <size>0x50</size>
        <usage>registers</usage>
      </addressBlock>
      <registers>
        <register>
          <name>CFGR1</name>
          <addressOffset>0x0</addressOffset>
          <fields>
            <field>
              <name>MEM_MODE</name>
              <description>memory mapping mode</description>
              <bitRange>[1:0]</bitRange>
            </field>
            <field>
              <name>I2C1_FMP</name>
              <description>I2C1 Fast-mode Plus driving capability activation</description>
              <bitRange>[2:2]</bitRange>
            </field>
            <field>
              <name>I2C2_FMP</name>
              <description>I2C2 Fast-mode Plus driving capability activation</description>
              <bitRange>[3:3]</bitRange>
            </field>
            <field>
              <name>I2C1_FLTEN</name>
              <description>I2C1 Fast-mode Plus driving capability activation</description>
              <bitRange>[4:4]</bitRange>
            </field>
            <field>
              <name>I2C2_FLTEN</name>
              <description>I2C2 Fast-mode Plus driving capability activation</description>
              <bitRange>[5:5]</bitRange>
            </field>
          </fields>
        </register>
        <register>
          <name>CFGR2</name>
          <addressOffset>0x4</addressOffset>
          <fields>
            <field>
              <name>CLL</name>
              <description>core lockup enable</description>
              <bitRange>[0:0]</bitRange>
            </field>
            <field>
              <name>PVDL</name>
              <description>pvd lock enable</description>
              <bitRange>[2:2]</bitRange>
            </field>
          </fields>
        </register>
        <register>
          <name>CFGR3</name>
          <addressOffset>0x8</addressOffset>
          <fields>
            <field>
              <name>DMA1_MAP1</name>
              <description>DMA1 ch1 mapping</description>
              <bitRange>[6:0]</bitRange>
            </field>
            <field>
              <name>DMA1_MAP2</name>
              <description>DMA1 ch2 mapping</description>
              <bitRange>[14:8]</bitRange>
            </field>
            <field>
              <name>DMA1_MAP3</name>
              <description>DMA1 ch3 mapping</description>
              <bitRange>[22:16]</bitRange>
            </field>
            <field>
              <name>DMA1_MAP4</name>
              <description>DMA1 ch4 mapping</description>
              <bitRange>[30:24]</bitRange>
            </field>
          </fields>
        </register>
        <register>
          <name>CFGR4</name>
          <addressOffset>0xC</addressOffset>
          <fields>
            <field>
              <name>DMA1_MAP5</name>
              <description>DMA1 ch5 mapping</description>
              <bitRange>[6:0]</bitRange>
            </field>
            <field>
              <name>DMA1_MAP6</name>
              <description>DMA1 ch6 mapping</description>
              <bitRange>[14:8]</bitRange>
            </field>
            <field>
              <name>DMA1_MAP7</name>
              <description>DMA1 ch7 mapping</description>
              <bitRange>[22:16]</bitRange>
            </field>
            <field>
              <name>DMA1_MAP8</name>
              <description>DMA1 ch8 mapping</description>
              <bitRange>[30:24]</bitRange>
            </field>
          </fields>
        </register>
        <register>
          <name>EXTICR1</name>
          <addressOffset>0x14</addressOffset>
          <fields>
            <field>
              <name>EXTI0</name>
              <description>EXTI 0~3 configuration</description>
              <bitRange>[1:0]</bitRange>
            </field>
            <field>
              <name>EXTI1</name>
              <description>EXTI 0~3 configuration</description>
              <bitRange>[5:4]</bitRange>
            </field>
            <field>
              <name>EXTI2</name>
              <description>EXTI 0~3 configuration</description>
              <bitRange>[9:8]</bitRange>
            </field>
            <field>
              <name>EXTI3</name>
              <description>EXTI 0~3 configuration</description>
              <bitRange>[13:12]</bitRange>
            </field>
          </fields>
        </register>
        <register>
          <name>EXTICR2</name>
          <addressOffset>0x18</addressOffset>
          <fields>
            <field>
              <name>EXTI4</name>
              <description>EXTI 4~7 configuration</description>
              <bitRange>[1:0]</bitRange>
            </field>
            <field>
              <name>EXTI5</name>
              <description>EXTI 4~7 configuration</description>
              <bitRange>[5:4]</bitRange>
            </field>
            <field>
              <name>EXTI6</name>
              <description>EXTI 4~7 configuration</description>
              <bitRange>[9:8]</bitRange>
            </field>
            <field>
              <name>EXTI7</name>
              <description>EXTI 4~7 configuration</description>
              <bitRange>[13:12]</bitRange>
            </field>
          </fields>
        </register>
        <register>
          <name>EXTICR3</name>
          <addressOffset>0x1C</addressOffset>
          <fields>
            <field>
              <name>EXTI8</name>
              <description>EXTI 8~11 configuration</description>
              <bitRange>[1:0]</bitRange>
            </field>
            <field>
              <name>EXTI9</name>
              <description>EXTI 8~11 configuration</description>
              <bitRange>[5:4]</bitRange>
            </field>
            <field>
              <name>EXTI10</name>
              <description>EXTI 8~11 configuration</description>
              <bitRange>[9:8]</bitRange>
            </field>
            <field>
              <name>EXTI11</name>
              <description>EXTI 8~11 configuration</description>
              <bitRange>[13:12]</bitRange>
            </field>
          </fields>
        </register>
        <register>
          <name>EXTICR4</name>
          <addressOffset>0x20</addressOffset>
          <fields>
            <field>
              <name>EXTI12</name>
              <description>EXTI 12~15 configuration</description>
              <bitRange>[1:0]</bitRange>
            </field>
            <field>
              <name>EXTI13</name>
              <description>EXTI 12~15 configuration</description>
              <bitRange>[5:4]</bitRange>
            </field>
            <field>
              <name>EXTI14</name>
              <description>EXTI 12~15 configuration</description>
              <bitRange>[9:8]</bitRange>
            </field>
            <field>
              <name>EXTI15</name>
              <description>EXTI 12~15 configuration</description>
              <bitRange>[13:12]</bitRange>
            </field>
          </fields>
        </register>
        <register>
          <name>PA_ENS</name>
          <addressOffset>0x24</addressOffset>
          <fields>
            <field>
              <name>PA_ENS</name>
              <description>GPIOA noise filter enable</description>
              <bitRange>[15:0]</bitRange>
            </field>
          </fields>
        </register>
        <register>
          <name>PB_ENS</name>
          <addressOffset>0x28</addressOffset>
          <fields>
            <field>
              <name>PB_ENS</name>
              <description>GPIOB noise filter enable</description>
              <bitRange>[15:0]</bitRange>
            </field>
          </fields>
        </register>
        <register>
          <name>PC_ENS</name>
          <addressOffset>0x2C</addressOffset>
          <fields>
            <field>
              <name>PC_ENS</name>
              <description>GPIOC noise filter enable</description>
              <bitRange>[15:0]</bitRange>
            </field>
          </fields>
        </register>
        <register>
          <name>PD_ENS</name>
          <addressOffset>0x30</addressOffset>
          <fields>
            <field>
              <name>PD_ENS</name>
              <description>GPIOD noise filter enable</description>
              <bitRange>[11:0]</bitRange>
            </field>
          </fields>
        </register>
        <register>
          <name>COMP_ANA2ENR</name>
          <addressOffset>0x40</addressOffset>
          <fields>
            <field>
              <name>PA0_ENA2</name>
              <description>PA0 analog2 enable</description>
              <bitRange>[0:0]</bitRange>
            </field>
            <field>
              <name>PA1_ENA2</name>
              <description>PA1 analog2 enable</description>
              <bitRange>[1:1]</bitRange>
            </field>
            <field>
              <name>PA2_ENA2</name>
              <description>PA2 analog2 enable</description>
              <bitRange>[2:2]</bitRange>
            </field>
            <field>
              <name>PA3_ENA2</name>
              <description>PA3 analog2 enable</description>
              <bitRange>[3:3]</bitRange>
            </field>
            <field>
              <name>PA4_ENA2</name>
              <description>PA4 analog2 enable</description>
              <bitRange>[4:4]</bitRange>
            </field>
            <field>
              <name>PA5_ENA2</name>
              <description>PA5 analog2 enable</description>
              <bitRange>[5:5]</bitRange>
            </field>
            <field>
              <name>PA9_ENA2</name>
              <description>PA7 analog2 enable</description>
              <bitRange>[9:9]</bitRange>
            </field>
            <field>
              <name>PB1_ENA2</name>
              <description>PB1 analog2 enable</description>
              <bitRange>[17:17]</bitRange>
            </field>
          </fields>
        </register>
      </registers>
    </peripheral>
    <peripheral>
      <name>TIM1</name>
      <groupName>TIM</groupName>
      <baseAddress>0x40012C00</baseAddress>
      <addressBlock>
        <offset>0x0</offset>
        <size>0x3F0</size>
        <usage>registers</usage>
      </addressBlock>
      <registers>
        <register>
          <name>CR1</name>
          <addressOffset>0x0</addressOffset>
          <fields>
            <field>
              <name>CEN</name>
              <bitRange>[0:0]</bitRange>
            </field>
            <field>
              <name>UDIS</name>
              <bitRange>[1:1]</bitRange>
            </field>
            <field>
              <name>URS</name>
              <bitRange>[2:2]</bitRange>
            </field>
            <field>
              <name>OPM</name>
              <bitRange>[3:3]</bitRange>
            </field>
            <field>
              <name>DIR</name>
              <bitRange>[4:4]</bitRange>
            </field>
            <field>
              <name>CMS</name>
              <bitRange>[6:5]</bitRange>
            </field>
            <field>
              <name>ARPE</name>
              <bitRange>[7:7]</bitRange>
            </field>
            <field>
              <name>CKD</name>
              <bitRange>[9:8]</bitRange>
            </field>
          </fields>
        </register>
        <register>
          <name>CR2</name>
          <addressOffset>0x4</addressOffset>
          <fields>
            <field>
              <name>CCPC</name>
              <bitRange>[0:0]</bitRange>
            </field>
            <field>
              <name>CCUS</name>
              <bitRange>[2:2]</bitRange>
            </field>
            <field>
              <name>CCDS</name>
              <bitRange>[3:3]</bitRange>
            </field>
            <field>
              <name>MMS_L</name>
              <bitRange>[6:4]</bitRange>
            </field>
            <field>
              <name>TI1S</name>
              <bitRange>[7:7]</bitRange>
            </field>
            <field>
              <name>OIS1</name>
              <bitRange>[8:8]</bitRange>
            </field>
            <field>
              <name>OIS1N</name>
              <bitRange>[9:9]</bitRange>
            </field>
            <field>
              <name>OIS2</name>
              <bitRange>[10:10]</bitRange>
            </field>
            <field>
              <name>OIS2N</name>
              <bitRange>[11:11]</bitRange>
            </field>
            <field>
              <name>OIS3</name>
              <bitRange>[12:12]</bitRange>
            </field>
            <field>
              <name>OIS3N</name>
              <bitRange>[13:13]</bitRange>
            </field>
            <field>
              <name>OIS4</name>
              <bitRange>[14:14]</bitRange>
            </field>
            <field>
              <name>OIS5</name>
              <bitRange>[16:16]</bitRange>
            </field>
            <field>
              <name>OIS6</name>
              <bitRange>[18:18]</bitRange>
            </field>
            <field>
              <name>MMS_H</name>
              <bitRange>[25:25]</bitRange>
            </field>
          </fields>
        </register>
        <register>
          <name>SMCR</name>
          <addressOffset>0x8</addressOffset>
          <fields>
            <field>
              <name>SMS_L</name>
              <bitRange>[2:0]</bitRange>
            </field>
            <field>
              <name>OCCS</name>
              <bitRange>[3:3]</bitRange>
            </field>
            <field>
              <name>TS_L</name>
              <bitRange>[6:4]</bitRange>
            </field>
            <field>
              <name>MSM</name>
              <bitRange>[7:7]</bitRange>
            </field>
            <field>
              <name>ETF</name>
              <bitRange>[11:8]</bitRange>
            </field>
            <field>
              <name>ETPS</name>
              <bitRange>[13:12]</bitRange>
            </field>
            <field>
              <name>ECE</name>
              <bitRange>[14:14]</bitRange>
            </field>
            <field>
              <name>ETP</name>
              <bitRange>[15:15]</bitRange>
            </field>
            <field>
              <name>SMS_H</name>
              <bitRange>[16:16]</bitRange>
            </field>
            <field>
              <name>TS_H</name>
              <bitRange>[21:20]</bitRange>
            </field>
          </fields>
        </register>
        <register>
          <name>DIER</name>
          <addressOffset>0xC</addressOffset>
          <fields>
            <field>
              <name>UIE</name>
              <bitRange>[0:0]</bitRange>
            </field>
            <field>
              <name>CC1IE</name>
              <bitRange>[1:1]</bitRange>
            </field>
            <field>
              <name>CC2IE</name>
              <bitRange>[2:2]</bitRange>
            </field>
            <field>
              <name>CC3IE</name>
              <bitRange>[3:3]</bitRange>
            </field>
            <field>
              <name>CC4IE</name>
              <bitRange>[4:4]</bitRange>
            </field>
            <field>
              <name>COMIE</name>
              <bitRange>[5:5]</bitRange>
            </field>
            <field>
              <name>TIE</name>
              <bitRange>[6:6]</bitRange>
            </field>
            <field>
              <name>BIE</name>
              <bitRange>[7:7]</bitRange>
            </field>
            <field>
              <name>UDE</name>
              <bitRange>[8:8]</bitRange>
            </field>
            <field>
              <name>CC1DE</name>
              <bitRange>[9:9]</bitRange>
            </field>
            <field>
              <name>CC2DE</name>
              <bitRange>[10:10]</bitRange>
            </field>
            <field>
              <name>CC3DE</name>
              <bitRange>[11:11]</bitRange>
            </field>
            <field>
              <name>CC4DE</name>
              <bitRange>[12:12]</bitRange>
            </field>
            <field>
              <name>COMDE</name>
              <bitRange>[13:13]</bitRange>
            </field>
            <field>
              <name>TDE</name>
              <bitRange>[14:14]</bitRange>
            </field>
          </fields>
        </register>
        <register>
          <name>SR</name>
          <addressOffset>0x10</addressOffset>
          <fields>
            <field>
              <name>UIF</name>
              <bitRange>[0:0]</bitRange>
            </field>
            <field>
              <name>CC1IF</name>
              <bitRange>[1:1]</bitRange>
            </field>
            <field>
              <name>CC2IF</name>
              <bitRange>[2:2]</bitRange>
            </field>
            <field>
              <name>CC3IF</name>
              <bitRange>[3:3]</bitRange>
            </field>
            <field>
              <name>CC4IF</name>
              <bitRange>[4:4]</bitRange>
            </field>
            <field>
              <name>COMIF</name>
              <bitRange>[5:5]</bitRange>
            </field>
            <field>
              <name>TIF</name>
              <bitRange>[6:6]</bitRange>
            </field>
            <field>
              <name>BIF</name>
              <bitRange>[7:7]</bitRange>
            </field>
            <field>
              <name>B2IF</name>
              <bitRange>[8:8]</bitRange>
            </field>
            <field>
              <name>CC1OF</name>
              <bitRange>[9:9]</bitRange>
            </field>
            <field>
              <name>CC2OF</name>
              <bitRange>[10:10]</bitRange>
            </field>
            <field>
              <name>CC3OF</name>
              <bitRange>[11:11]</bitRange>
            </field>
            <field>
              <name>CC4OF</name>
              <bitRange>[12:12]</bitRange>
            </field>
            <field>
              <name>SBIF</name>
              <bitRange>[13:13]</bitRange>
            </field>
            <field>
              <name>CC5IF</name>
              <bitRange>[16:16]</bitRange>
            </field>
            <field>
              <name>CC6IF</name>
              <bitRange>[17:17]</bitRange>
            </field>
            <field>
              <name>IC1IR</name>
              <bitRange>[18:18]</bitRange>
            </field>
            <field>
              <name>IC2IR</name>
              <bitRange>[19:19]</bitRange>
            </field>
            <field>
              <name>IC3IR</name>
              <bitRange>[24:24]</bitRange>
            </field>
            <field>
              <name>IC4IR</name>
              <bitRange>[25:25]</bitRange>
            </field>
            <field>
              <name>IC1IF</name>
              <bitRange>[26:26]</bitRange>
            </field>
            <field>
              <name>IC2IF</name>
              <bitRange>[27:27]</bitRange>
            </field>
            <field>
              <name>IC3IF</name>
              <bitRange>[28:28]</bitRange>
            </field>
            <field>
              <name>IC4IF</name>
              <bitRange>[29:29]</bitRange>
            </field>
          </fields>
        </register>
        <register>
          <name>EGR</name>
          <addressOffset>0x14</addressOffset>
          <fields>
            <field>
              <name>UG</name>
              <bitRange>[0:0]</bitRange>
            </field>
            <field>
              <name>CC1G</name>
              <bitRange>[1:1]</bitRange>
            </field>
            <field>
              <name>CC2G</name>
              <bitRange>[2:2]</bitRange>
            </field>
            <field>
              <name>CC3G</name>
              <bitRange>[3:3]</bitRange>
            </field>
            <field>
              <name>CC4G</name>
              <bitRange>[4:4]</bitRange>
            </field>
            <field>
              <name>COMG</name>
              <bitRange>[5:5]</bitRange>
            </field>
            <field>
              <name>TG</name>
              <bitRange>[6:6]</bitRange>
            </field>
            <field>
              <name>BG</name>
              <bitRange>[7:7]</bitRange>
            </field>
          </fields>
        </register>
        <register>
          <name>CCMR1_OUTPUT</name>
          <addressOffset>0x18</addressOffset>
          <fields>
            <field>
              <name>CC1S</name>
              <bitRange>[1:0]</bitRange>
            </field>
            <field>
              <name>OC1FE</name>
              <bitRange>[2:2]</bitRange>
            </field>
            <field>
              <name>OC1PE</name>
              <bitRange>[3:3]</bitRange>
            </field>
            <field>
              <name>OC1M_L</name>
              <bitRange>[6:4]</bitRange>
            </field>
            <field>
              <name>OC1CE</name>
              <bitRange>[7:7]</bitRange>
            </field>
            <field>
              <name>CC2S</name>
              <bitRange>[9:8]</bitRange>
            </field>
            <field>
              <name>OC2FE</name>
              <bitRange>[10:10]</bitRange>
            </field>
            <field>
              <name>OC2PE</name>
              <bitRange>[11:11]</bitRange>
            </field>
            <field>
              <name>OC2M_L</name>
              <bitRange>[14:12]</bitRange>
            </field>
            <field>
              <name>OC2CE</name>
              <bitRange>[15:15]</bitRange>
            </field>
            <field>
              <name>OC1M_H</name>
              <bitRange>[16:16]</bitRange>
            </field>
            <field>
              <name>OC2M_H</name>
              <bitRange>[24:24]</bitRange>
            </field>
          </fields>
        </register>
        <register>
          <name>CCMR1_INPUT</name>
          <alternateRegister>CCMR1_OUTPUT</alternateRegister>
          <addressOffset>0x18</addressOffset>
          <fields>
            <field>
              <name>CC1S</name>
              <bitRange>[1:0]</bitRange>
            </field>
            <field>
              <name>IC1PSC</name>
              <bitRange>[3:2]</bitRange>
            </field>
            <field>
              <name>IC1F</name>
              <bitRange>[7:4]</bitRange>
            </field>
            <field>
              <name>CC2S</name>
              <bitRange>[9:8]</bitRange>
            </field>
            <field>
              <name>IC2PSC</name>
              <bitRange>[11:10]</bitRange>
            </field>
            <field>
              <name>IC2F</name>
              <bitRange>[15:12]</bitRange>
            </field>
          </fields>
        </register>
        <register>
          <name>CCMR2_OUTPUT</name>
          <addressOffset>0x1C</addressOffset>
          <fields>
            <field>
              <name>CC3S</name>
              <bitRange>[1:0]</bitRange>
            </field>
            <field>
              <name>OC3FE</name>
              <bitRange>[2:2]</bitRange>
            </field>
            <field>
              <name>OC3PE</name>
              <bitRange>[3:3]</bitRange>
            </field>
            <field>
              <name>OC3M_L</name>
              <bitRange>[6:4]</bitRange>
            </field>
            <field>
              <name>OC3CE</name>
              <bitRange>[7:7]</bitRange>
            </field>
            <field>
              <name>CC4S</name>
              <bitRange>[9:8]</bitRange>
            </field>
            <field>
              <name>OC4FE</name>
              <bitRange>[10:10]</bitRange>
            </field>
            <field>
              <name>OC4PE</name>
              <bitRange>[11:11]</bitRange>
            </field>
            <field>
              <name>OC4M_L</name>
              <bitRange>[14:12]</bitRange>
            </field>
            <field>
              <name>OC4CE</name>
              <bitRange>[15:15]</bitRange>
            </field>
            <field>
              <name>OC3M_H</name>
              <bitRange>[16:16]</bitRange>
            </field>
            <field>
              <name>OC4M_H</name>
              <bitRange>[24:24]</bitRange>
            </field>
          </fields>
        </register>
        <register>
          <name>CCMR2_INPUT</name>
          <alternateRegister>CCMR2_OUTPUT</alternateRegister>
          <addressOffset>0x1C</addressOffset>
          <fields>
            <field>
              <name>CC3S</name>
              <bitRange>[1:0]</bitRange>
            </field>
            <field>
              <name>IC3PSC</name>
              <bitRange>[3:2]</bitRange>
            </field>
            <field>
              <name>IC3F</name>
              <bitRange>[7:4]</bitRange>
            </field>
            <field>
              <name>CC4S</name>
              <bitRange>[9:8]</bitRange>
            </field>
            <field>
              <name>IC4PSC</name>
              <bitRange>[11:10]</bitRange>
            </field>
            <field>
              <name>IC4F</name>
              <bitRange>[15:12]</bitRange>
            </field>
          </fields>
        </register>
        <register>
          <name>CCER</name>
          <addressOffset>0x20</addressOffset>
          <fields>
            <field>
              <name>CC1E</name>
              <bitRange>[0:0]</bitRange>
            </field>
            <field>
              <name>CC1P</name>
              <bitRange>[1:1]</bitRange>
            </field>
            <field>
              <name>CC1NE</name>
              <bitRange>[2:2]</bitRange>
            </field>
            <field>
              <name>CC1NP</name>
              <bitRange>[3:3]</bitRange>
            </field>
            <field>
              <name>CC2E</name>
              <bitRange>[4:4]</bitRange>
            </field>
            <field>
              <name>CC2P</name>
              <bitRange>[5:5]</bitRange>
            </field>
            <field>
              <name>CC2NE</name>
              <bitRange>[6:6]</bitRange>
            </field>
            <field>
              <name>CC2NP</name>
              <bitRange>[7:7]</bitRange>
            </field>
            <field>
              <name>CC3E</name>
              <bitRange>[8:8]</bitRange>
            </field>
            <field>
              <name>CC3P</name>
              <bitRange>[9:9]</bitRange>
            </field>
            <field>
              <name>CC3NE</name>
              <bitRange>[10:10]</bitRange>
            </field>
            <field>
              <name>CC3NP</name>
              <bitRange>[11:11]</bitRange>
            </field>
            <field>
              <name>CC4E</name>
              <bitRange>[12:12]</bitRange>
            </field>
            <field>
              <name>CC4P</name>
              <bitRange>[13:13]</bitRange>
            </field>
            <field>
              <name>CC5E</name>
              <bitRange>[16:16]</bitRange>
            </field>
            <field>
              <name>CC5P</name>
              <bitRange>[17:17]</bitRange>
            </field>
            <field>
              <name>CC6E</name>
              <bitRange>[20:20]</bitRange>
            </field>
            <field>
              <name>CC6P</name>
              <bitRange>[21:21]</bitRange>
            </field>
          </fields>
        </register>
        <register>
          <name>CNT</name>
          <addressOffset>0x24</addressOffset>
          <fields>
            <field>
              <name>CNT</name>
              <bitRange>[15:0]</bitRange>
            </field>
          </fields>
        </register>
        <register>
          <name>PSC</name>
          <addressOffset>0x28</addressOffset>
          <fields>
            <field>
              <name>PSC</name>
              <bitRange>[15:0]</bitRange>
            </field>
          </fields>
        </register>
        <register>
          <name>ARR</name>
          <addressOffset>0x2C</addressOffset>
          <fields>
            <field>
              <name>ARR</name>
              <bitRange>[15:0]</bitRange>
            </field>
          </fields>
        </register>
        <register>
          <name>RCR</name>
          <addressOffset>0x30</addressOffset>
          <fields>
            <field>
              <name>REP</name>
              <bitRange>[15:0]</bitRange>
            </field>
          </fields>
        </register>
        <register>
          <name>CCR1</name>
          <addressOffset>0x34</addressOffset>
          <fields>
            <field>
              <name>CCR1</name>
              <bitRange>[15:0]</bitRange>
            </field>
            <field>
              <name>CCR1_H</name>
              <bitRange>[31:16]</bitRange>
            </field>
          </fields>
        </register>
        <register>
          <name>CCR2</name>
          <addressOffset>0x38</addressOffset>
          <fields>
            <field>
              <name>CCR2</name>
              <bitRange>[15:0]</bitRange>
            </field>
            <field>
              <name>CCR2_H</name>
              <bitRange>[31:16]</bitRange>
            </field>
          </fields>
        </register>
        <register>
          <name>CCR3</name>
          <addressOffset>0x3C</addressOffset>
          <fields>
            <field>
              <name>CCR3</name>
              <bitRange>[15:0]</bitRange>
            </field>
            <field>
              <name>CCR3_H</name>
              <bitRange>[31:16]</bitRange>
            </field>
          </fields>
        </register>
        <register>
          <name>CCR4</name>
          <addressOffset>0x40</addressOffset>
          <fields>
            <field>
              <name>CCR4</name>
              <bitRange>[15:0]</bitRange>
            </field>
          </fields>
        </register>
        <register>
          <name>BDTR</name>
          <addressOffset>0x44</addressOffset>
          <fields>
            <field>
              <name>DTG</name>
              <bitRange>[7:0]</bitRange>
            </field>
            <field>
              <name>LOCK</name>
              <bitRange>[9:8]</bitRange>
            </field>
            <field>
              <name>OSSI</name>
              <bitRange>[10:10]</bitRange>
            </field>
            <field>
              <name>OSSR</name>
              <bitRange>[11:11]</bitRange>
            </field>
            <field>
              <name>BKE</name>
              <bitRange>[12:12]</bitRange>
            </field>
            <field>
              <name>BKP</name>
              <bitRange>[13:13]</bitRange>
            </field>
            <field>
              <name>AOE</name>
              <bitRange>[14:14]</bitRange>
            </field>
            <field>
              <name>MOE</name>
              <bitRange>[15:15]</bitRange>
            </field>
          </fields>
        </register>
        <register>
          <name>CCR5</name>
          <addressOffset>0x48</addressOffset>
          <fields>
            <field>
              <name>CCR5</name>
              <bitRange>[15:0]</bitRange>
            </field>
          </fields>
        </register>
        <register>
          <name>CCR6</name>
          <addressOffset>0x4C</addressOffset>
          <fields>
            <field>
              <name>CCR6</name>
              <bitRange>[15:0]</bitRange>
            </field>
          </fields>
        </register>
        <register>
          <name>CCMR3_OUTPUT</name>
          <addressOffset>0x50</addressOffset>
          <fields>
            <field>
              <name>OC5FE</name>
              <bitRange>[2:2]</bitRange>
            </field>
            <field>
              <name>OC5PE</name>
              <bitRange>[3:3]</bitRange>
            </field>
            <field>
              <name>OC5M_L</name>
              <bitRange>[6:4]</bitRange>
            </field>
            <field>
              <name>OC5CE</name>
              <bitRange>[7:7]</bitRange>
            </field>
            <field>
              <name>OC6FE</name>
              <bitRange>[10:10]</bitRange>
            </field>
            <field>
              <name>OC6PE</name>
              <bitRange>[11:11]</bitRange>
            </field>
            <field>
              <name>OC6M_L</name>
              <bitRange>[14:12]</bitRange>
            </field>
            <field>
              <name>OC6CE</name>
              <bitRange>[15:15]</bitRange>
            </field>
            <field>
              <name>OC5M_H</name>
              <bitRange>[16:16]</bitRange>
            </field>
            <field>
              <name>OC6M_H</name>
              <bitRange>[24:24]</bitRange>
            </field>
          </fields>
        </register>
        <register>
          <name>TISEL</name>
          <addressOffset>0x5C</addressOffset>
          <fields>
            <field>
              <name>TI1SEL</name>
              <bitRange>[3:0]</bitRange>
            </field>
            <field>
              <name>TI2SEL</name>
              <bitRange>[11:8]</bitRange>
            </field>
            <field>
              <name>TI3SEL</name>
              <bitRange>[19:16]</bitRange>
            </field>
            <field>
              <name>TI4SEL</name>
              <bitRange>[27:24]</bitRange>
            </field>
          </fields>
        </register>
        <register>
          <name>AF1</name>
          <addressOffset>0x60</addressOffset>
          <fields>
            <field>
              <name>BKINE</name>
              <bitRange>[0:0]</bitRange>
            </field>
            <field>
              <name>BKCMP1E</name>
              <bitRange>[1:1]</bitRange>
            </field>
            <field>
              <name>BKCMP2E</name>
              <bitRange>[2:2]</bitRange>
            </field>
            <field>
              <name>BKINP</name>
              <bitRange>[9:9]</bitRange>
            </field>
            <field>
              <name>BKCMP1P</name>
              <bitRange>[10:10]</bitRange>
            </field>
            <field>
              <name>BKCMP2P</name>
              <bitRange>[11:11]</bitRange>
            </field>
            <field>
              <name>ETRSEL</name>
              <bitRange>[17:14]</bitRange>
            </field>
            <field>
              <name>INTR_SEL</name>
              <bitRange>[19:18]</bitRange>
            </field>
            <field>
              <name>PWM_PHS_EN</name>
              <bitRange>[20:20]</bitRange>
            </field>
          </fields>
        </register>
        <register>
          <name>AF2</name>
          <addressOffset>0x64</addressOffset>
          <fields>
            <field>
              <name>OCRSEL</name>
              <bitRange>[18:16]</bitRange>
            </field>
          </fields>
        </register>
        <register>
          <name>DCR</name>
          <addressOffset>0x3DC</addressOffset>
          <fields>
            <field>
              <name>DBA</name>
              <bitRange>[4:0]</bitRange>
            </field>
            <field>
              <name>DBL</name>
              <bitRange>[12:8]</bitRange>
            </field>
          </fields>
        </register>
        <register>
          <name>DMAR</name>
          <addressOffset>0x3E0</addressOffset>
          <fields>
            <field>
              <name>DMAB</name>
              <bitRange>[31:0]</bitRange>
            </field>
          </fields>
        </register>
      </registers>
    </peripheral>
    <peripheral>
      <name>TIM2</name>
      <groupName>TIM</groupName>
      <baseAddress>0x40000000</baseAddress>
      <addressBlock>
        <offset>0x0</offset>
        <size>0x3F0</size>
        <usage>registers</usage>
      </addressBlock>
      <registers>
        <register>
          <name>CR1</name>
          <addressOffset>0x0</addressOffset>
          <fields>
            <field>
              <name>CEN</name>
              <bitRange>[0:0]</bitRange>
            </field>
            <field>
              <name>UDIS</name>
              <bitRange>[1:1]</bitRange>
            </field>
            <field>
              <name>URS</name>
              <bitRange>[2:2]</bitRange>
            </field>
            <field>
              <name>OPM</name>
              <bitRange>[3:3]</bitRange>
            </field>
            <field>
              <name>DIR</name>
              <bitRange>[4:4]</bitRange>
            </field>
            <field>
              <name>CMS</name>
              <bitRange>[6:5]</bitRange>
            </field>
            <field>
              <name>ARPE</name>
              <bitRange>[7:7]</bitRange>
            </field>
            <field>
              <name>CKD</name>
              <bitRange>[9:8]</bitRange>
            </field>
          </fields>
        </register>
        <register>
          <name>CR2</name>
          <addressOffset>0x4</addressOffset>
          <fields>
            <field>
              <name>CCDS</name>
              <bitRange>[3:3]</bitRange>
            </field>
            <field>
              <name>MMS_L</name>
              <bitRange>[6:4]</bitRange>
            </field>
            <field>
              <name>TI1S</name>
              <bitRange>[7:7]</bitRange>
            </field>
            <field>
              <name>MMS_H</name>
              <bitRange>[25:25]</bitRange>
            </field>
          </fields>
        </register>
        <register>
          <name>SMCR</name>
          <addressOffset>0x8</addressOffset>
          <fields>
            <field>
              <name>SMS</name>
              <bitRange>[2:0]</bitRange>
            </field>
            <field>
              <name>OCCS</name>
              <bitRange>[3:3]</bitRange>
            </field>
            <field>
              <name>TS_L</name>
              <bitRange>[6:4]</bitRange>
            </field>
            <field>
              <name>MSM</name>
              <bitRange>[7:7]</bitRange>
            </field>
            <field>
              <name>ETF</name>
              <bitRange>[11:8]</bitRange>
            </field>
            <field>
              <name>ETPS</name>
              <bitRange>[13:12]</bitRange>
            </field>
            <field>
              <name>ECE</name>
              <bitRange>[14:14]</bitRange>
            </field>
            <field>
              <name>ETP</name>
              <bitRange>[15:15]</bitRange>
            </field>
            <field>
              <name>TS_H</name>
              <bitRange>[21:20]</bitRange>
            </field>
          </fields>
        </register>
        <register>
          <name>DIER</name>
          <addressOffset>0xC</addressOffset>
          <fields>
            <field>
              <name>UIE</name>
              <bitRange>[0:0]</bitRange>
            </field>
            <field>
              <name>CC1IE</name>
              <bitRange>[1:1]</bitRange>
            </field>
            <field>
              <name>CC2IE</name>
              <bitRange>[2:2]</bitRange>
            </field>
            <field>
              <name>CC3IE</name>
              <bitRange>[3:3]</bitRange>
            </field>
            <field>
              <name>CC4IE</name>
              <bitRange>[4:4]</bitRange>
            </field>
            <field>
              <name>TIE</name>
              <bitRange>[6:6]</bitRange>
            </field>
            <field>
              <name>UDE</name>
              <bitRange>[8:8]</bitRange>
            </field>
            <field>
              <name>CC1DE</name>
              <bitRange>[9:9]</bitRange>
            </field>
            <field>
              <name>CC2DE</name>
              <bitRange>[10:10]</bitRange>
            </field>
            <field>
              <name>CC3DE</name>
              <bitRange>[11:11]</bitRange>
            </field>
            <field>
              <name>CC4DE</name>
              <bitRange>[12:12]</bitRange>
            </field>
            <field>
              <name>TDE</name>
              <bitRange>[14:14]</bitRange>
            </field>
          </fields>
        </register>
        <register>
          <name>SR</name>
          <addressOffset>0x10</addressOffset>
          <fields>
            <field>
              <name>UIF</name>
              <bitRange>[0:0]</bitRange>
            </field>
            <field>
              <name>CC1IF</name>
              <bitRange>[1:1]</bitRange>
            </field>
            <field>
              <name>CC2IF</name>
              <bitRange>[2:2]</bitRange>
            </field>
            <field>
              <name>CC3IF</name>
              <bitRange>[3:3]</bitRange>
            </field>
            <field>
              <name>CC4IF</name>
              <bitRange>[4:4]</bitRange>
            </field>
            <field>
              <name>TIF</name>
              <bitRange>[6:6]</bitRange>
            </field>
            <field>
              <name>CC1OF</name>
              <bitRange>[9:9]</bitRange>
            </field>
            <field>
              <name>CC2OF</name>
              <bitRange>[10:10]</bitRange>
            </field>
            <field>
              <name>CC3OF</name>
              <bitRange>[11:11]</bitRange>
            </field>
            <field>
              <name>CC4OF</name>
              <bitRange>[12:12]</bitRange>
            </field>
            <field>
              <name>IC1IR</name>
              <bitRange>[18:18]</bitRange>
            </field>
            <field>
              <name>IC2IR</name>
              <bitRange>[19:19]</bitRange>
            </field>
            <field>
              <name>IC3IR</name>
              <bitRange>[24:24]</bitRange>
            </field>
            <field>
              <name>IC4IR</name>
              <bitRange>[25:25]</bitRange>
            </field>
            <field>
              <name>IC1IF</name>
              <bitRange>[26:26]</bitRange>
            </field>
            <field>
              <name>IC2IF</name>
              <bitRange>[27:27]</bitRange>
            </field>
            <field>
              <name>IC3IF</name>
              <bitRange>[28:28]</bitRange>
            </field>
            <field>
              <name>IC4IF</name>
              <bitRange>[29:29]</bitRange>
            </field>
          </fields>
        </register>
        <register>
          <name>EGR</name>
          <addressOffset>0x14</addressOffset>
          <fields>
            <field>
              <name>UG</name>
              <bitRange>[0:0]</bitRange>
            </field>
            <field>
              <name>CC1G</name>
              <bitRange>[1:1]</bitRange>
            </field>
            <field>
              <name>CC2G</name>
              <bitRange>[2:2]</bitRange>
            </field>
            <field>
              <name>CC3G</name>
              <bitRange>[3:3]</bitRange>
            </field>
            <field>
              <name>CC4G</name>
              <bitRange>[4:4]</bitRange>
            </field>
            <field>
              <name>TG</name>
              <bitRange>[6:6]</bitRange>
            </field>
          </fields>
        </register>
        <register>
          <name>CCMR1_OUTPUT</name>
          <addressOffset>0x18</addressOffset>
          <fields>
            <field>
              <name>CC1S</name>
              <bitRange>[1:0]</bitRange>
            </field>
            <field>
              <name>OC1FE</name>
              <bitRange>[2:2]</bitRange>
            </field>
            <field>
              <name>OC1PE</name>
              <bitRange>[3:3]</bitRange>
            </field>
            <field>
              <name>OC1M</name>
              <bitRange>[6:4]</bitRange>
            </field>
            <field>
              <name>OC1CE</name>
              <bitRange>[7:7]</bitRange>
            </field>
            <field>
              <name>CC2S</name>
              <bitRange>[9:8]</bitRange>
            </field>
            <field>
              <name>OC2FE</name>
              <bitRange>[10:10]</bitRange>
            </field>
            <field>
              <name>OC2PE</name>
              <bitRange>[11:11]</bitRange>
            </field>
            <field>
              <name>OC2M</name>
              <bitRange>[14:12]</bitRange>
            </field>
            <field>
              <name>OC2CE</name>
              <bitRange>[15:15]</bitRange>
            </field>
          </fields>
        </register>
        <register>
          <name>CCMR1_INPUT</name>
          <alternateRegister>CCMR1_OUTPUT</alternateRegister>
          <addressOffset>0x18</addressOffset>
          <fields>
            <field>
              <name>CC1S</name>
              <bitRange>[1:0]</bitRange>
            </field>
            <field>
              <name>IC1PSC</name>
              <bitRange>[3:2]</bitRange>
            </field>
            <field>
              <name>IC1F</name>
              <bitRange>[7:4]</bitRange>
            </field>
            <field>
              <name>CC2S</name>
              <bitRange>[9:8]</bitRange>
            </field>
            <field>
              <name>IC2PSC</name>
              <bitRange>[11:10]</bitRange>
            </field>
            <field>
              <name>IC2F</name>
              <bitRange>[15:12]</bitRange>
            </field>
          </fields>
        </register>
        <register>
          <name>CCMR2_OUTPUT</name>
          <addressOffset>0x1C</addressOffset>
          <fields>
            <field>
              <name>CC3S</name>
              <bitRange>[1:0]</bitRange>
            </field>
            <field>
              <name>OC3FE</name>
              <bitRange>[2:2]</bitRange>
            </field>
            <field>
              <name>OC3PE</name>
              <bitRange>[3:3]</bitRange>
            </field>
            <field>
              <name>OC3M</name>
              <bitRange>[6:4]</bitRange>
            </field>
            <field>
              <name>OC3CE</name>
              <bitRange>[7:7]</bitRange>
            </field>
            <field>
              <name>CC4S</name>
              <bitRange>[9:8]</bitRange>
            </field>
            <field>
              <name>OC4FE</name>
              <bitRange>[10:10]</bitRange>
            </field>
            <field>
              <name>OC4PE</name>
              <bitRange>[11:11]</bitRange>
            </field>
            <field>
              <name>OC4M</name>
              <bitRange>[14:12]</bitRange>
            </field>
            <field>
              <name>OC4CE</name>
              <bitRange>[15:15]</bitRange>
            </field>
          </fields>
        </register>
        <register>
          <name>CCMR2_INPUT</name>
          <alternateRegister>CCMR2_OUTPUT</alternateRegister>
          <addressOffset>0x1C</addressOffset>
          <fields>
            <field>
              <name>CC3S</name>
              <bitRange>[1:0]</bitRange>
            </field>
            <field>
              <name>IC3PSC</name>
              <bitRange>[3:2]</bitRange>
            </field>
            <field>
              <name>IC3F</name>
              <bitRange>[7:4]</bitRange>
            </field>
            <field>
              <name>CC4S</name>
              <bitRange>[9:8]</bitRange>
            </field>
            <field>
              <name>IC4PSC</name>
              <bitRange>[11:10]</bitRange>
            </field>
            <field>
              <name>IC4F</name>
              <bitRange>[15:12]</bitRange>
            </field>
          </fields>
        </register>
        <register>
          <name>CCER</name>
          <addressOffset>0x20</addressOffset>
          <fields>
            <field>
              <name>CC1E</name>
              <bitRange>[0:0]</bitRange>
            </field>
            <field>
              <name>CC1P</name>
              <bitRange>[1:1]</bitRange>
            </field>
            <field>
              <name>CC1NP</name>
              <bitRange>[3:3]</bitRange>
            </field>
            <field>
              <name>CC2E</name>
              <bitRange>[4:4]</bitRange>
            </field>
            <field>
              <name>CC2P</name>
              <bitRange>[5:5]</bitRange>
            </field>
            <field>
              <name>CC2NP</name>
              <bitRange>[7:7]</bitRange>
            </field>
            <field>
              <name>CC3E</name>
              <bitRange>[8:8]</bitRange>
            </field>
            <field>
              <name>CC3P</name>
              <bitRange>[9:9]</bitRange>
            </field>
            <field>
              <name>CC3NP</name>
              <bitRange>[11:11]</bitRange>
            </field>
            <field>
              <name>CC4E</name>
              <bitRange>[12:12]</bitRange>
            </field>
            <field>
              <name>CC4P</name>
              <bitRange>[13:13]</bitRange>
            </field>
            <field>
              <name>CC4NP</name>
              <bitRange>[15:15]</bitRange>
            </field>
          </fields>
        </register>
        <register>
          <name>CNT</name>
          <addressOffset>0x24</addressOffset>
          <fields>
            <field>
              <name>CNT</name>
              <bitRange>[31:0]</bitRange>
            </field>
          </fields>
        </register>
        <register>
          <name>PSC</name>
          <addressOffset>0x28</addressOffset>
          <fields>
            <field>
              <name>PSC</name>
              <bitRange>[15:0]</bitRange>
            </field>
          </fields>
        </register>
        <register>
          <name>ARR</name>
          <addressOffset>0x2C</addressOffset>
          <fields>
            <field>
              <name>ARR</name>
              <bitRange>[31:0]</bitRange>
            </field>
          </fields>
        </register>
        <register>
          <name>CCR1</name>
          <addressOffset>0x34</addressOffset>
          <fields>
            <field>
              <name>CCR1</name>
              <bitRange>[31:0]</bitRange>
            </field>
          </fields>
        </register>
        <register>
          <name>CCR2</name>
          <addressOffset>0x38</addressOffset>
          <fields>
            <field>
              <name>CCR2</name>
              <bitRange>[31:0]</bitRange>
            </field>
          </fields>
        </register>
        <register>
          <name>CCR3</name>
          <addressOffset>0x3C</addressOffset>
          <fields>
            <field>
              <name>CCR3</name>
              <bitRange>[31:0]</bitRange>
            </field>
          </fields>
        </register>
        <register>
          <name>CCR4</name>
          <addressOffset>0x40</addressOffset>
          <fields>
            <field>
              <name>CCR4</name>
              <bitRange>[31:0]</bitRange>
            </field>
          </fields>
        </register>
        <register>
          <name>TISEL</name>
          <addressOffset>0x5C</addressOffset>
          <fields>
            <field>
              <name>TI1SEL</name>
              <bitRange>[3:0]</bitRange>
            </field>
            <field>
              <name>TI2SEL</name>
              <bitRange>[11:8]</bitRange>
            </field>
            <field>
              <name>TI3SEL</name>
              <bitRange>[19:16]</bitRange>
            </field>
            <field>
              <name>TI4SEL</name>
              <bitRange>[27:24]</bitRange>
            </field>
          </fields>
        </register>
        <register>
          <name>AF1</name>
          <addressOffset>0x60</addressOffset>
          <fields>
            <field>
              <name>ETRSEL</name>
              <bitRange>[17:14]</bitRange>
            </field>
          </fields>
        </register>
        <register>
          <name>AF2</name>
          <addressOffset>0x64</addressOffset>
          <fields>
            <field>
              <name>OCRSEL</name>
              <bitRange>[18:16]</bitRange>
            </field>
          </fields>
        </register>
        <register>
          <name>DCR</name>
          <addressOffset>0x3DC</addressOffset>
          <fields>
            <field>
              <name>DBA</name>
              <bitRange>[4:0]</bitRange>
            </field>
            <field>
              <name>DBL</name>
              <bitRange>[12:8]</bitRange>
            </field>
          </fields>
        </register>
        <register>
          <name>DMAR</name>
          <addressOffset>0x3E0</addressOffset>
          <fields>
            <field>
              <name>DMAB</name>
              <bitRange>[31:0]</bitRange>
            </field>
          </fields>
        </register>
      </registers>
    </peripheral>
    <peripheral>
      <name>TIM3</name>
      <groupName>TIM</groupName>
      <baseAddress>0x40000400</baseAddress>
      <addressBlock>
        <offset>0x0</offset>
        <size>0x3F0</size>
        <usage>registers</usage>
      </addressBlock>
      <registers>
        <register>
          <name>CR1</name>
          <addressOffset>0x0</addressOffset>
          <fields>
            <field>
              <name>CEN</name>
              <bitRange>[0:0]</bitRange>
            </field>
            <field>
              <name>UDIS</name>
              <bitRange>[1:1]</bitRange>
            </field>
            <field>
              <name>URS</name>
              <bitRange>[2:2]</bitRange>
            </field>
            <field>
              <name>OPM</name>
              <bitRange>[3:3]</bitRange>
            </field>
            <field>
              <name>DIR</name>
              <bitRange>[4:4]</bitRange>
            </field>
            <field>
              <name>CMS</name>
              <bitRange>[6:5]</bitRange>
            </field>
            <field>
              <name>ARPE</name>
              <bitRange>[7:7]</bitRange>
            </field>
            <field>
              <name>CKD</name>
              <bitRange>[9:8]</bitRange>
            </field>
          </fields>
        </register>
        <register>
          <name>CR2</name>
          <addressOffset>0x4</addressOffset>
          <fields>
            <field>
              <name>CCDS</name>
              <bitRange>[3:3]</bitRange>
            </field>
            <field>
              <name>MMS_L</name>
              <bitRange>[6:4]</bitRange>
            </field>
            <field>
              <name>TI1S</name>
              <bitRange>[7:7]</bitRange>
            </field>
            <field>
              <name>MMS_H</name>
              <bitRange>[25:25]</bitRange>
            </field>
          </fields>
        </register>
        <register>
          <name>SMCR</name>
          <addressOffset>0x8</addressOffset>
          <fields>
            <field>
              <name>SMS</name>
              <bitRange>[2:0]</bitRange>
            </field>
            <field>
              <name>OCCS</name>
              <bitRange>[3:3]</bitRange>
            </field>
            <field>
              <name>TS_L</name>
              <bitRange>[6:4]</bitRange>
            </field>
            <field>
              <name>MSM</name>
              <bitRange>[7:7]</bitRange>
            </field>
            <field>
              <name>ETF</name>
              <bitRange>[11:8]</bitRange>
            </field>
            <field>
              <name>ETPS</name>
              <bitRange>[13:12]</bitRange>
            </field>
            <field>
              <name>ECE</name>
              <bitRange>[14:14]</bitRange>
            </field>
            <field>
              <name>ETP</name>
              <bitRange>[15:15]</bitRange>
            </field>
            <field>
              <name>TS_H</name>
              <bitRange>[21:20]</bitRange>
            </field>
          </fields>
        </register>
        <register>
          <name>DIER</name>
          <addressOffset>0xC</addressOffset>
          <fields>
            <field>
              <name>UIE</name>
              <bitRange>[0:0]</bitRange>
            </field>
            <field>
              <name>CC1IE</name>
              <bitRange>[1:1]</bitRange>
            </field>
            <field>
              <name>CC2IE</name>
              <bitRange>[2:2]</bitRange>
            </field>
            <field>
              <name>CC3IE</name>
              <bitRange>[3:3]</bitRange>
            </field>
            <field>
              <name>CC4IE</name>
              <bitRange>[4:4]</bitRange>
            </field>
            <field>
              <name>TIE</name>
              <bitRange>[6:6]</bitRange>
            </field>
            <field>
              <name>UDE</name>
              <bitRange>[8:8]</bitRange>
            </field>
            <field>
              <name>CC1DE</name>
              <bitRange>[9:9]</bitRange>
            </field>
            <field>
              <name>CC2DE</name>
              <bitRange>[10:10]</bitRange>
            </field>
            <field>
              <name>CC3DE</name>
              <bitRange>[11:11]</bitRange>
            </field>
            <field>
              <name>CC4DE</name>
              <bitRange>[12:12]</bitRange>
            </field>
            <field>
              <name>TDE</name>
              <bitRange>[14:14]</bitRange>
            </field>
          </fields>
        </register>
        <register>
          <name>SR</name>
          <addressOffset>0x10</addressOffset>
          <fields>
            <field>
              <name>UIF</name>
              <bitRange>[0:0]</bitRange>
            </field>
            <field>
              <name>CC1IF</name>
              <bitRange>[1:1]</bitRange>
            </field>
            <field>
              <name>CC2IF</name>
              <bitRange>[2:2]</bitRange>
            </field>
            <field>
              <name>CC3IF</name>
              <bitRange>[3:3]</bitRange>
            </field>
            <field>
              <name>CC4IF</name>
              <bitRange>[4:4]</bitRange>
            </field>
            <field>
              <name>TIF</name>
              <bitRange>[6:6]</bitRange>
            </field>
            <field>
              <name>CC1OF</name>
              <bitRange>[9:9]</bitRange>
            </field>
            <field>
              <name>CC2OF</name>
              <bitRange>[10:10]</bitRange>
            </field>
            <field>
              <name>CC3OF</name>
              <bitRange>[11:11]</bitRange>
            </field>
            <field>
              <name>CC4OF</name>
              <bitRange>[12:12]</bitRange>
            </field>
            <field>
              <name>IC1IR</name>
              <bitRange>[18:18]</bitRange>
            </field>
            <field>
              <name>IC2IR</name>
              <bitRange>[19:19]</bitRange>
            </field>
            <field>
              <name>IC3IR</name>
              <bitRange>[24:24]</bitRange>
            </field>
            <field>
              <name>IC4IR</name>
              <bitRange>[25:25]</bitRange>
            </field>
            <field>
              <name>IC1IF</name>
              <bitRange>[26:26]</bitRange>
            </field>
            <field>
              <name>IC2IF</name>
              <bitRange>[27:27]</bitRange>
            </field>
            <field>
              <name>IC3IF</name>
              <bitRange>[28:28]</bitRange>
            </field>
            <field>
              <name>IC4IF</name>
              <bitRange>[29:29]</bitRange>
            </field>
          </fields>
        </register>
        <register>
          <name>EGR</name>
          <addressOffset>0x14</addressOffset>
          <fields>
            <field>
              <name>UG</name>
              <bitRange>[0:0]</bitRange>
            </field>
            <field>
              <name>CC1G</name>
              <bitRange>[1:1]</bitRange>
            </field>
            <field>
              <name>CC2G</name>
              <bitRange>[2:2]</bitRange>
            </field>
            <field>
              <name>CC3G</name>
              <bitRange>[3:3]</bitRange>
            </field>
            <field>
              <name>CC4G</name>
              <bitRange>[4:4]</bitRange>
            </field>
            <field>
              <name>TG</name>
              <bitRange>[6:6]</bitRange>
            </field>
          </fields>
        </register>
        <register>
          <name>CCMR1_OUTPUT</name>
          <addressOffset>0x18</addressOffset>
          <fields>
            <field>
              <name>CC1S</name>
              <bitRange>[1:0]</bitRange>
            </field>
            <field>
              <name>OC1FE</name>
              <bitRange>[2:2]</bitRange>
            </field>
            <field>
              <name>OC1PE</name>
              <bitRange>[3:3]</bitRange>
            </field>
            <field>
              <name>OC1M</name>
              <bitRange>[6:4]</bitRange>
            </field>
            <field>
              <name>OC1CE</name>
              <bitRange>[7:7]</bitRange>
            </field>
            <field>
              <name>CC2S</name>
              <bitRange>[9:8]</bitRange>
            </field>
            <field>
              <name>OC2FE</name>
              <bitRange>[10:10]</bitRange>
            </field>
            <field>
              <name>OC2PE</name>
              <bitRange>[11:11]</bitRange>
            </field>
            <field>
              <name>OC2M</name>
              <bitRange>[14:12]</bitRange>
            </field>
            <field>
              <name>OC2CE</name>
              <bitRange>[15:15]</bitRange>
            </field>
          </fields>
        </register>
        <register>
          <name>CCMR1_INPUT</name>
          <alternateRegister>CCMR1_OUTPUT</alternateRegister>
          <addressOffset>0x18</addressOffset>
          <fields>
            <field>
              <name>CC1S</name>
              <bitRange>[1:0]</bitRange>
            </field>
            <field>
              <name>IC1PSC</name>
              <bitRange>[3:2]</bitRange>
            </field>
            <field>
              <name>IC1F</name>
              <bitRange>[7:4]</bitRange>
            </field>
            <field>
              <name>CC2S</name>
              <bitRange>[9:8]</bitRange>
            </field>
            <field>
              <name>IC2PSC</name>
              <bitRange>[11:10]</bitRange>
            </field>
            <field>
              <name>IC2F</name>
              <bitRange>[15:12]</bitRange>
            </field>
          </fields>
        </register>
        <register>
          <name>CCMR2_OUTPUT</name>
          <addressOffset>0x1C</addressOffset>
          <fields>
            <field>
              <name>CC3S</name>
              <bitRange>[1:0]</bitRange>
            </field>
            <field>
              <name>OC3FE</name>
              <bitRange>[2:2]</bitRange>
            </field>
            <field>
              <name>OC3PE</name>
              <bitRange>[3:3]</bitRange>
            </field>
            <field>
              <name>OC3M</name>
              <bitRange>[6:4]</bitRange>
            </field>
            <field>
              <name>OC3CE</name>
              <bitRange>[7:7]</bitRange>
            </field>
            <field>
              <name>CC4S</name>
              <bitRange>[9:8]</bitRange>
            </field>
            <field>
              <name>OC4FE</name>
              <bitRange>[10:10]</bitRange>
            </field>
            <field>
              <name>OC4PE</name>
              <bitRange>[11:11]</bitRange>
            </field>
            <field>
              <name>OC4M</name>
              <bitRange>[14:12]</bitRange>
            </field>
            <field>
              <name>OC4CE</name>
              <bitRange>[15:15]</bitRange>
            </field>
          </fields>
        </register>
        <register>
          <name>CCMR2_INPUT</name>
          <alternateRegister>CCMR2_OUTPUT</alternateRegister>
          <addressOffset>0x1C</addressOffset>
          <fields>
            <field>
              <name>CC3S</name>
              <bitRange>[1:0]</bitRange>
            </field>
            <field>
              <name>IC3PSC</name>
              <bitRange>[3:2]</bitRange>
            </field>
            <field>
              <name>IC3F</name>
              <bitRange>[7:4]</bitRange>
            </field>
            <field>
              <name>CC4S</name>
              <bitRange>[9:8]</bitRange>
            </field>
            <field>
              <name>IC4PSC</name>
              <bitRange>[11:10]</bitRange>
            </field>
            <field>
              <name>IC4F</name>
              <bitRange>[15:12]</bitRange>
            </field>
          </fields>
        </register>
        <register>
          <name>CCER</name>
          <addressOffset>0x20</addressOffset>
          <fields>
            <field>
              <name>CC1E</name>
              <bitRange>[0:0]</bitRange>
            </field>
            <field>
              <name>CC1P</name>
              <bitRange>[1:1]</bitRange>
            </field>
            <field>
              <name>CC1NP</name>
              <bitRange>[3:3]</bitRange>
            </field>
            <field>
              <name>CC2E</name>
              <bitRange>[4:4]</bitRange>
            </field>
            <field>
              <name>CC2P</name>
              <bitRange>[5:5]</bitRange>
            </field>
            <field>
              <name>CC2NP</name>
              <bitRange>[7:7]</bitRange>
            </field>
            <field>
              <name>CC3E</name>
              <bitRange>[8:8]</bitRange>
            </field>
            <field>
              <name>CC3P</name>
              <bitRange>[9:9]</bitRange>
            </field>
            <field>
              <name>CC3NP</name>
              <bitRange>[11:11]</bitRange>
            </field>
            <field>
              <name>CC4E</name>
              <bitRange>[12:12]</bitRange>
            </field>
            <field>
              <name>CC4P</name>
              <bitRange>[13:13]</bitRange>
            </field>
            <field>
              <name>CC4NP</name>
              <bitRange>[15:15]</bitRange>
            </field>
          </fields>
        </register>
        <register>
          <name>CNT</name>
          <addressOffset>0x24</addressOffset>
          <fields>
            <field>
              <name>CNT</name>
              <bitRange>[15:0]</bitRange>
            </field>
          </fields>
        </register>
        <register>
          <name>PSC</name>
          <addressOffset>0x28</addressOffset>
          <fields>
            <field>
              <name>PSC</name>
              <bitRange>[15:0]</bitRange>
            </field>
          </fields>
        </register>
        <register>
          <name>ARR</name>
          <addressOffset>0x2C</addressOffset>
          <fields>
            <field>
              <name>ARR</name>
              <bitRange>[15:0]</bitRange>
            </field>
          </fields>
        </register>
        <register>
          <name>CCR1</name>
          <addressOffset>0x34</addressOffset>
          <fields>
            <field>
              <name>CCR1</name>
              <bitRange>[15:0]</bitRange>
            </field>
          </fields>
        </register>
        <register>
          <name>CCR2</name>
          <addressOffset>0x38</addressOffset>
          <fields>
            <field>
              <name>CCR2</name>
              <bitRange>[15:0]</bitRange>
            </field>
          </fields>
        </register>
        <register>
          <name>CCR3</name>
          <addressOffset>0x3C</addressOffset>
          <fields>
            <field>
              <name>CCR3</name>
              <bitRange>[15:0]</bitRange>
            </field>
          </fields>
        </register>
        <register>
          <name>CCR4</name>
          <addressOffset>0x40</addressOffset>
          <fields>
            <field>
              <name>CCR4</name>
              <bitRange>[15:0]</bitRange>
            </field>
          </fields>
        </register>
        <register>
          <name>TISEL</name>
          <addressOffset>0x5C</addressOffset>
          <fields>
            <field>
              <name>TI1SEL</name>
              <bitRange>[3:0]</bitRange>
            </field>
            <field>
              <name>TI2SEL</name>
              <bitRange>[11:8]</bitRange>
            </field>
            <field>
              <name>TI3SEL</name>
              <bitRange>[19:16]</bitRange>
            </field>
            <field>
              <name>TI4SEL</name>
              <bitRange>[27:24]</bitRange>
            </field>
          </fields>
        </register>
        <register>
          <name>AF1</name>
          <addressOffset>0x60</addressOffset>
          <fields>
            <field>
              <name>ETRSEL</name>
              <bitRange>[17:14]</bitRange>
            </field>
          </fields>
        </register>
        <register>
          <name>AF2</name>
          <addressOffset>0x64</addressOffset>
          <fields>
            <field>
              <name>OCRSEL</name>
              <bitRange>[18:16]</bitRange>
            </field>
          </fields>
        </register>
        <register>
          <name>TIMXDCR</name>
          <addressOffset>0x3DC</addressOffset>
          <fields>
            <field>
              <name>DBA</name>
              <bitRange>[4:0]</bitRange>
            </field>
            <field>
              <name>DBL</name>
              <bitRange>[12:8]</bitRange>
            </field>
          </fields>
        </register>
        <register>
          <name>DMAR</name>
          <addressOffset>0x3E0</addressOffset>
          <fields>
            <field>
              <name>DMAB</name>
              <bitRange>[31:0]</bitRange>
            </field>
          </fields>
        </register>
      </registers>
    </peripheral>
    <peripheral derivedFrom="TIM3">
      <name>TIM4</name>
      <baseAddress>0x40000800</baseAddress>
    </peripheral>
    <peripheral>
      <name>TIM6</name>
      <groupName>TIM</groupName>
      <baseAddress>0x40001000</baseAddress>
      <addressBlock>
        <offset>0x0</offset>
        <size>0x30</size>
        <usage>registers</usage>
      </addressBlock>
      <registers>
        <register>
          <name>CR1</name>
          <addressOffset>0x0</addressOffset>
          <fields>
            <field>
              <name>CEN</name>
              <bitRange>[0:0]</bitRange>
            </field>
            <field>
              <name>UDIS</name>
              <bitRange>[1:1]</bitRange>
            </field>
            <field>
              <name>URS</name>
              <bitRange>[2:2]</bitRange>
            </field>
            <field>
              <name>OPM</name>
              <bitRange>[3:3]</bitRange>
            </field>
            <field>
              <name>ARPE</name>
              <bitRange>[7:7]</bitRange>
            </field>
          </fields>
        </register>
        <register>
          <name>DIER</name>
          <addressOffset>0xC</addressOffset>
          <fields>
            <field>
              <name>UIE</name>
              <bitRange>[0:0]</bitRange>
            </field>
            <field>
              <name>UDE</name>
              <bitRange>[8:8]</bitRange>
            </field>
          </fields>
        </register>
        <register>
          <name>SR</name>
          <addressOffset>0x10</addressOffset>
          <fields>
            <field>
              <name>UIF</name>
              <bitRange>[0:0]</bitRange>
            </field>
          </fields>
        </register>
        <register>
          <name>EGR</name>
          <addressOffset>0x14</addressOffset>
          <fields>
            <field>
              <name>UG</name>
              <bitRange>[0:0]</bitRange>
              <access>read-only</access>
            </field>
          </fields>
        </register>
        <register>
          <name>CNT</name>
          <addressOffset>0x24</addressOffset>
          <fields>
            <field>
              <name>CNT</name>
              <bitRange>[15:0]</bitRange>
            </field>
          </fields>
        </register>
        <register>
          <name>PSC</name>
          <addressOffset>0x28</addressOffset>
          <fields>
            <field>
              <name>PSC</name>
              <bitRange>[15:0]</bitRange>
            </field>
          </fields>
        </register>
        <register>
          <name>ARR</name>
          <addressOffset>0x2C</addressOffset>
          <fields>
            <field>
              <name>ARR</name>
              <bitRange>[15:0]</bitRange>
            </field>
          </fields>
        </register>
      </registers>
    </peripheral>
    <peripheral derivedFrom="TIM6">
      <name>TIM7</name>
      <baseAddress>0x40001400</baseAddress>
    </peripheral>
    <peripheral>
      <name>TIM15</name>
      <groupName>TIM</groupName>
      <baseAddress>0x40015800</baseAddress>
      <addressBlock>
        <offset>0x0</offset>
        <size>0x3F0</size>
        <usage>registers</usage>
      </addressBlock>
      <registers>
        <register>
          <name>CR1</name>
          <addressOffset>0x0</addressOffset>
          <fields>
            <field>
              <name>CEN</name>
              <bitRange>[0:0]</bitRange>
            </field>
            <field>
              <name>UDIS</name>
              <bitRange>[1:1]</bitRange>
            </field>
            <field>
              <name>URS</name>
              <bitRange>[2:2]</bitRange>
            </field>
            <field>
              <name>OPM</name>
              <bitRange>[3:3]</bitRange>
            </field>
            <field>
              <name>ARPE</name>
              <bitRange>[7:7]</bitRange>
            </field>
            <field>
              <name>CKD</name>
              <bitRange>[9:8]</bitRange>
            </field>
          </fields>
        </register>
        <register>
          <name>CR2</name>
          <addressOffset>0x4</addressOffset>
          <fields>
            <field>
              <name>CCPC</name>
              <bitRange>[0:0]</bitRange>
            </field>
            <field>
              <name>CCUS</name>
              <bitRange>[2:2]</bitRange>
            </field>
            <field>
              <name>CCDS</name>
              <bitRange>[3:3]</bitRange>
            </field>
            <field>
              <name>MMS</name>
              <bitRange>[6:4]</bitRange>
            </field>
            <field>
              <name>OIS1</name>
              <bitRange>[8:8]</bitRange>
            </field>
            <field>
              <name>OIS1N</name>
              <bitRange>[9:9]</bitRange>
            </field>
            <field>
              <name>OIS2</name>
              <bitRange>[10:10]</bitRange>
            </field>
          </fields>
        </register>
        <register>
          <name>SMCR</name>
          <addressOffset>0x8</addressOffset>
          <fields>
            <field>
              <name>SMS</name>
              <bitRange>[2:0]</bitRange>
            </field>
            <field>
              <name>TS_L</name>
              <bitRange>[6:5]</bitRange>
            </field>
            <field>
              <name>MSM</name>
              <bitRange>[7:7]</bitRange>
            </field>
            <field>
              <name>ETF</name>
              <bitRange>[11:8]</bitRange>
            </field>
            <field>
              <name>ETPS</name>
              <bitRange>[13:12]</bitRange>
            </field>
            <field>
              <name>ECE</name>
              <bitRange>[14:14]</bitRange>
            </field>
            <field>
              <name>ETP</name>
              <bitRange>[15:15]</bitRange>
            </field>
            <field>
              <name>TS_H</name>
              <bitRange>[21:20]</bitRange>
            </field>
          </fields>
        </register>
        <register>
          <name>DIER</name>
          <addressOffset>0xC</addressOffset>
          <fields>
            <field>
              <name>UIE</name>
              <bitRange>[0:0]</bitRange>
            </field>
            <field>
              <name>CC1IE</name>
              <bitRange>[1:1]</bitRange>
            </field>
            <field>
              <name>CC2IE</name>
              <bitRange>[2:2]</bitRange>
            </field>
            <field>
              <name>COMIE</name>
              <bitRange>[5:5]</bitRange>
            </field>
            <field>
              <name>TIE</name>
              <bitRange>[6:6]</bitRange>
            </field>
            <field>
              <name>BIE</name>
              <bitRange>[7:7]</bitRange>
            </field>
            <field>
              <name>UDE</name>
              <bitRange>[8:8]</bitRange>
            </field>
            <field>
              <name>CC1DE</name>
              <bitRange>[9:9]</bitRange>
            </field>
            <field>
              <name>COMDE</name>
              <bitRange>[13:13]</bitRange>
            </field>
            <field>
              <name>TDE</name>
              <bitRange>[14:14]</bitRange>
            </field>
          </fields>
        </register>
        <register>
          <name>SR</name>
          <addressOffset>0x10</addressOffset>
          <fields>
            <field>
              <name>UIF</name>
              <bitRange>[0:0]</bitRange>
            </field>
            <field>
              <name>CC1IF</name>
              <bitRange>[1:1]</bitRange>
            </field>
            <field>
              <name>CC2IF</name>
              <bitRange>[2:2]</bitRange>
            </field>
            <field>
              <name>COMIF</name>
              <bitRange>[5:5]</bitRange>
            </field>
            <field>
              <name>TIF</name>
              <bitRange>[6:6]</bitRange>
            </field>
            <field>
              <name>BIF</name>
              <bitRange>[7:7]</bitRange>
            </field>
            <field>
              <name>CC1OF</name>
              <bitRange>[9:9]</bitRange>
            </field>
            <field>
              <name>CC2OF</name>
              <bitRange>[10:10]</bitRange>
            </field>
            <field>
              <name>IC1IR</name>
              <bitRange>[16:16]</bitRange>
            </field>
            <field>
              <name>IC2IR</name>
              <bitRange>[17:17]</bitRange>
            </field>
            <field>
              <name>IC1IF</name>
              <bitRange>[20:20]</bitRange>
            </field>
            <field>
              <name>IC2IF</name>
              <bitRange>[21:21]</bitRange>
            </field>
          </fields>
        </register>
        <register>
          <name>EGR</name>
          <addressOffset>0x14</addressOffset>
          <fields>
            <field>
              <name>UG</name>
              <bitRange>[0:0]</bitRange>
            </field>
            <field>
              <name>CC1G</name>
              <bitRange>[1:1]</bitRange>
            </field>
            <field>
              <name>CC2G</name>
              <bitRange>[2:2]</bitRange>
            </field>
            <field>
              <name>COMG</name>
              <bitRange>[5:5]</bitRange>
            </field>
            <field>
              <name>TG</name>
              <bitRange>[6:6]</bitRange>
            </field>
            <field>
              <name>BG</name>
              <bitRange>[7:7]</bitRange>
            </field>
          </fields>
        </register>
        <register>
          <name>CCMR1_OUTPUT</name>
          <addressOffset>0x18</addressOffset>
          <fields>
            <field>
              <name>CC1S</name>
              <bitRange>[1:0]</bitRange>
            </field>
            <field>
              <name>OC1FE</name>
              <bitRange>[2:2]</bitRange>
            </field>
            <field>
              <name>OC1PE</name>
              <bitRange>[3:3]</bitRange>
            </field>
            <field>
              <name>OC1M</name>
              <bitRange>[6:4]</bitRange>
            </field>
            <field>
              <name>CC2S</name>
              <bitRange>[9:8]</bitRange>
            </field>
            <field>
              <name>OC2FE</name>
              <bitRange>[10:10]</bitRange>
            </field>
            <field>
              <name>OC2PE</name>
              <bitRange>[11:11]</bitRange>
            </field>
            <field>
              <name>OC2M</name>
              <bitRange>[14:12]</bitRange>
            </field>
          </fields>
        </register>
        <register>
          <name>CCMR1_INPUT</name>
          <alternateRegister>CCMR1_OUTPUT</alternateRegister>
          <addressOffset>0x18</addressOffset>
          <fields>
            <field>
              <name>CC1S</name>
              <bitRange>[1:0]</bitRange>
            </field>
            <field>
              <name>IC1PSC</name>
              <bitRange>[3:2]</bitRange>
            </field>
            <field>
              <name>IC1F</name>
              <bitRange>[7:4]</bitRange>
            </field>
            <field>
              <name>CC2S</name>
              <bitRange>[9:8]</bitRange>
            </field>
            <field>
              <name>IC2PSC</name>
              <bitRange>[11:10]</bitRange>
            </field>
            <field>
              <name>IC2F</name>
              <bitRange>[15:12]</bitRange>
            </field>
          </fields>
        </register>
        <register>
          <name>CCER</name>
          <addressOffset>0x20</addressOffset>
          <fields>
            <field>
              <name>CC1E</name>
              <bitRange>[0:0]</bitRange>
            </field>
            <field>
              <name>CC1P</name>
              <bitRange>[1:1]</bitRange>
            </field>
            <field>
              <name>CC1NE</name>
              <bitRange>[2:2]</bitRange>
            </field>
            <field>
              <name>CC1NP</name>
              <bitRange>[3:3]</bitRange>
            </field>
            <field>
              <name>CC2E</name>
              <bitRange>[4:4]</bitRange>
            </field>
            <field>
              <name>CC2P</name>
              <bitRange>[5:5]</bitRange>
            </field>
            <field>
              <name>CC2NP</name>
              <bitRange>[7:7]</bitRange>
            </field>
          </fields>
        </register>
        <register>
          <name>CNT</name>
          <addressOffset>0x24</addressOffset>
          <fields>
            <field>
              <name>CNT</name>
              <bitRange>[15:0]</bitRange>
            </field>
          </fields>
        </register>
        <register>
          <name>PSC</name>
          <addressOffset>0x28</addressOffset>
          <fields>
            <field>
              <name>PSC</name>
              <bitRange>[15:0]</bitRange>
            </field>
          </fields>
        </register>
        <register>
          <name>ARR</name>
          <addressOffset>0x2C</addressOffset>
          <fields>
            <field>
              <name>ARR</name>
              <bitRange>[15:0]</bitRange>
            </field>
          </fields>
        </register>
        <register>
          <name>RCR</name>
          <addressOffset>0x30</addressOffset>
          <fields>
            <field>
              <name>REP</name>
              <bitRange>[7:0]</bitRange>
            </field>
          </fields>
        </register>
        <register>
          <name>CCR1</name>
          <addressOffset>0x34</addressOffset>
          <fields>
            <field>
              <name>CCR1</name>
              <bitRange>[15:0]</bitRange>
            </field>
          </fields>
        </register>
        <register>
          <name>CCR2</name>
          <addressOffset>0x38</addressOffset>
          <fields>
            <field>
              <name>CCR2</name>
              <bitRange>[15:0]</bitRange>
            </field>
          </fields>
        </register>
        <register>
          <name>BDTR</name>
          <addressOffset>0x44</addressOffset>
          <fields>
            <field>
              <name>DTG</name>
              <bitRange>[7:0]</bitRange>
            </field>
            <field>
              <name>LOCK</name>
              <bitRange>[9:8]</bitRange>
            </field>
            <field>
              <name>OSSI</name>
              <bitRange>[10:10]</bitRange>
            </field>
            <field>
              <name>OSSR</name>
              <bitRange>[11:11]</bitRange>
            </field>
            <field>
              <name>BKE</name>
              <bitRange>[12:12]</bitRange>
            </field>
            <field>
              <name>BKP</name>
              <bitRange>[13:13]</bitRange>
            </field>
            <field>
              <name>AOE</name>
              <bitRange>[14:14]</bitRange>
            </field>
            <field>
              <name>MOE</name>
              <bitRange>[15:15]</bitRange>
            </field>
          </fields>
        </register>
        <register>
          <name>TISEL</name>
          <addressOffset>0x5C</addressOffset>
          <fields>
            <field>
              <name>TI1SEL</name>
              <bitRange>[3:0]</bitRange>
            </field>
            <field>
              <name>TI2SEL</name>
              <bitRange>[11:8]</bitRange>
            </field>
          </fields>
        </register>
        <register>
          <name>AF1</name>
          <addressOffset>0x60</addressOffset>
          <fields>
            <field>
              <name>BKINE</name>
              <bitRange>[0:0]</bitRange>
            </field>
            <field>
              <name>BKCMP1E</name>
              <bitRange>[1:1]</bitRange>
            </field>
            <field>
              <name>BKCMP2E</name>
              <bitRange>[2:2]</bitRange>
            </field>
            <field>
              <name>BKINP</name>
              <bitRange>[9:9]</bitRange>
            </field>
            <field>
              <name>BKCMP1P</name>
              <bitRange>[10:10]</bitRange>
            </field>
            <field>
              <name>BKCMP2P</name>
              <bitRange>[11:11]</bitRange>
            </field>
            <field>
              <name>ETRSEL</name>
              <bitRange>[17:14]</bitRange>
            </field>
          </fields>
        </register>
        <register>
          <name>TIMXDCR</name>
          <addressOffset>0x3DC</addressOffset>
          <fields>
            <field>
              <name>DBA</name>
              <bitRange>[4:0]</bitRange>
            </field>
            <field>
              <name>DBL</name>
              <bitRange>[12:8]</bitRange>
            </field>
          </fields>
        </register>
        <register>
          <name>DMAR</name>
          <addressOffset>0x3E0</addressOffset>
          <fields>
            <field>
              <name>DMAB</name>
              <bitRange>[31:0]</bitRange>
            </field>
          </fields>
        </register>
      </registers>
    </peripheral>
    <peripheral>
      <name>TIM16</name>
      <groupName>TIM</groupName>
      <baseAddress>0x40015C00</baseAddress>
      <addressBlock>
        <offset>0x0</offset>
        <size>0x3F0</size>
        <usage>registers</usage>
      </addressBlock>
      <registers>
        <register>
          <name>CR1</name>
          <addressOffset>0x0</addressOffset>
          <fields>
            <field>
              <name>CEN</name>
              <bitRange>[0:0]</bitRange>
            </field>
            <field>
              <name>UDIS</name>
              <bitRange>[1:1]</bitRange>
            </field>
            <field>
              <name>URS</name>
              <bitRange>[2:2]</bitRange>
            </field>
            <field>
              <name>OPM</name>
              <bitRange>[3:3]</bitRange>
            </field>
            <field>
              <name>ARPE</name>
              <bitRange>[7:7]</bitRange>
            </field>
            <field>
              <name>CKD</name>
              <bitRange>[9:8]</bitRange>
            </field>
          </fields>
        </register>
        <register>
          <name>CR2</name>
          <addressOffset>0x4</addressOffset>
          <fields>
            <field>
              <name>CCPC</name>
              <bitRange>[0:0]</bitRange>
            </field>
            <field>
              <name>CCDS</name>
              <bitRange>[3:3]</bitRange>
            </field>
            <field>
              <name>MMS</name>
              <bitRange>[6:4]</bitRange>
            </field>
            <field>
              <name>OIS1</name>
              <bitRange>[8:8]</bitRange>
            </field>
            <field>
              <name>OIS1N</name>
              <bitRange>[9:9]</bitRange>
            </field>
          </fields>
        </register>
        <register>
          <name>DIER</name>
          <addressOffset>0xC</addressOffset>
          <fields>
            <field>
              <name>UIE</name>
              <bitRange>[0:0]</bitRange>
            </field>
            <field>
              <name>CC1IE</name>
              <bitRange>[1:1]</bitRange>
            </field>
            <field>
              <name>COMIE</name>
              <bitRange>[5:5]</bitRange>
            </field>
            <field>
              <name>BIE</name>
              <bitRange>[7:7]</bitRange>
            </field>
            <field>
              <name>UDE</name>
              <bitRange>[8:8]</bitRange>
            </field>
            <field>
              <name>CC1DE</name>
              <bitRange>[9:9]</bitRange>
            </field>
          </fields>
        </register>
        <register>
          <name>SR</name>
          <addressOffset>0x10</addressOffset>
          <fields>
            <field>
              <name>UIF</name>
              <bitRange>[0:0]</bitRange>
            </field>
            <field>
              <name>CC1IF</name>
              <bitRange>[1:1]</bitRange>
            </field>
            <field>
              <name>COMIF</name>
              <bitRange>[5:5]</bitRange>
            </field>
            <field>
              <name>BIF</name>
              <bitRange>[7:7]</bitRange>
            </field>
            <field>
              <name>CC1OF</name>
              <bitRange>[9:9]</bitRange>
            </field>
            <field>
              <name>IC1IR</name>
              <bitRange>[16:16]</bitRange>
            </field>
            <field>
              <name>IC1IF</name>
              <bitRange>[20:20]</bitRange>
            </field>
          </fields>
        </register>
        <register>
          <name>EGR</name>
          <addressOffset>0x14</addressOffset>
          <fields>
            <field>
              <name>UG</name>
              <bitRange>[0:0]</bitRange>
            </field>
            <field>
              <name>CC1G</name>
              <bitRange>[1:1]</bitRange>
            </field>
            <field>
              <name>COMG</name>
              <bitRange>[5:5]</bitRange>
            </field>
            <field>
              <name>BG</name>
              <bitRange>[7:7]</bitRange>
            </field>
          </fields>
        </register>
        <register>
          <name>CCMR1_OUTPUT</name>
          <addressOffset>0x18</addressOffset>
          <fields>
            <field>
              <name>CC1S</name>
              <bitRange>[1:0]</bitRange>
            </field>
            <field>
              <name>OC1FE</name>
              <bitRange>[2:2]</bitRange>
            </field>
            <field>
              <name>OC1PE</name>
              <bitRange>[3:3]</bitRange>
            </field>
            <field>
              <name>OC1M</name>
              <bitRange>[6:4]</bitRange>
            </field>
          </fields>
        </register>
        <register>
          <name>CCMR1_INPUT</name>
          <alternateRegister>CCMR1_OUTPUT</alternateRegister>
          <addressOffset>0x18</addressOffset>
          <fields>
            <field>
              <name>CC1S</name>
              <bitRange>[1:0]</bitRange>
            </field>
            <field>
              <name>IC1PSC</name>
              <bitRange>[3:2]</bitRange>
            </field>
            <field>
              <name>IC1F</name>
              <bitRange>[7:4]</bitRange>
            </field>
          </fields>
        </register>
        <register>
          <name>CCER</name>
          <addressOffset>0x20</addressOffset>
          <fields>
            <field>
              <name>CC1E</name>
              <bitRange>[0:0]</bitRange>
            </field>
            <field>
              <name>CC1P</name>
              <bitRange>[1:1]</bitRange>
            </field>
            <field>
              <name>CC1NE</name>
              <bitRange>[2:2]</bitRange>
            </field>
            <field>
              <name>CC1NP</name>
              <bitRange>[3:3]</bitRange>
            </field>
          </fields>
        </register>
        <register>
          <name>CNT</name>
          <addressOffset>0x24</addressOffset>
          <fields>
            <field>
              <name>CNT</name>
              <bitRange>[15:0]</bitRange>
            </field>
          </fields>
        </register>
        <register>
          <name>PSC</name>
          <addressOffset>0x28</addressOffset>
          <fields>
            <field>
              <name>PSC</name>
              <bitRange>[15:0]</bitRange>
            </field>
          </fields>
        </register>
        <register>
          <name>ARR</name>
          <addressOffset>0x2C</addressOffset>
          <fields>
            <field>
              <name>ARR</name>
              <bitRange>[15:0]</bitRange>
            </field>
          </fields>
        </register>
        <register>
          <name>RCR</name>
          <addressOffset>0x30</addressOffset>
          <fields>
            <field>
              <name>REP</name>
              <bitRange>[7:0]</bitRange>
            </field>
          </fields>
        </register>
        <register>
          <name>CCR1</name>
          <addressOffset>0x34</addressOffset>
          <fields>
            <field>
              <name>CCR1</name>
              <bitRange>[15:0]</bitRange>
            </field>
          </fields>
        </register>
        <register>
          <name>BDTR</name>
          <addressOffset>0x44</addressOffset>
          <fields>
            <field>
              <name>DTG</name>
              <bitRange>[7:0]</bitRange>
            </field>
            <field>
              <name>LOCK</name>
              <bitRange>[9:8]</bitRange>
            </field>
            <field>
              <name>OSSI</name>
              <bitRange>[10:10]</bitRange>
            </field>
            <field>
              <name>OSSR</name>
              <bitRange>[11:11]</bitRange>
            </field>
            <field>
              <name>BKE</name>
              <bitRange>[12:12]</bitRange>
            </field>
            <field>
              <name>BKP</name>
              <bitRange>[13:13]</bitRange>
            </field>
            <field>
              <name>AOE</name>
              <bitRange>[14:14]</bitRange>
            </field>
            <field>
              <name>MOE</name>
              <bitRange>[15:15]</bitRange>
            </field>
          </fields>
        </register>
        <register>
          <name>TISEL</name>
          <addressOffset>0x5C</addressOffset>
          <fields>
            <field>
              <name>TI1SEL</name>
              <bitRange>[3:0]</bitRange>
            </field>
          </fields>
        </register>
        <register>
          <name>AF1</name>
          <addressOffset>0x60</addressOffset>
          <fields>
            <field>
              <name>BKINE</name>
              <bitRange>[0:0]</bitRange>
            </field>
            <field>
              <name>BKCMP1E</name>
              <bitRange>[1:1]</bitRange>
            </field>
            <field>
              <name>BKCMP2E</name>
              <bitRange>[2:2]</bitRange>
            </field>
            <field>
              <name>BKINP</name>
              <bitRange>[9:9]</bitRange>
            </field>
            <field>
              <name>BKCMP1P</name>
              <bitRange>[10:10]</bitRange>
            </field>
            <field>
              <name>BKCMP2P</name>
              <bitRange>[11:11]</bitRange>
            </field>
          </fields>
        </register>
        <register>
          <name>DCR</name>
          <addressOffset>0x3DC</addressOffset>
          <fields>
            <field>
              <name>DBA</name>
              <bitRange>[4:0]</bitRange>
            </field>
            <field>
              <name>DBL</name>
              <bitRange>[12:8]</bitRange>
            </field>
          </fields>
        </register>
        <register>
          <name>DMAR</name>
          <addressOffset>0x3E0</addressOffset>
          <fields>
            <field>
              <name>DMAB</name>
              <bitRange>[31:0]</bitRange>
            </field>
          </fields>
        </register>
      </registers>
    </peripheral>
    <peripheral derivedFrom="TIM16">
      <name>TIM17</name>
      <baseAddress>0x40016000</baseAddress>
    </peripheral>
    <peripheral>
      <name>UART1</name>
      <groupName>UART</groupName>
      <baseAddress>0x40004C00</baseAddress>
      <addressBlock>
        <offset>0x0</offset>
        <size>0x30</size>
        <usage>registers</usage>
      </addressBlock>
      <registers>
        <register>
          <name>DR</name>
          <addressOffset>0x0</addressOffset>
          <fields>
            <field>
              <name>DR</name>
              <description>Receive/send data register</description>
              <bitRange>[8:0]</bitRange>
            </field>
          </fields>
        </register>
        <register>
          <name>BRR</name>
          <addressOffset>0x4</addressOffset>
          <fields>
            <field>
              <name>BRR</name>
              <description>Baud rate register</description>
              <bitRange>[15:0]</bitRange>
            </field>
          </fields>
        </register>
        <register>
          <name>SR</name>
          <addressOffset>0x10</addressOffset>
          <fields>
            <field>
              <name>RXNE</name>
              <description>Receive register not empty</description>
              <bitRange>[0:0]</bitRange>
              <access>read-only</access>
            </field>
            <field>
              <name>ORE</name>
              <description>Overrun error bit</description>
              <bitRange>[1:1]</bitRange>
            </field>
            <field>
              <name>PE</name>
              <description>Parity Error bit</description>
              <bitRange>[2:2]</bitRange>
            </field>
            <field>
              <name>FE</name>
              <description>Framing Error bit</description>
              <bitRange>[3:3]</bitRange>
            </field>
            <field>
              <name>BRI</name>
              <description>Break Interrupt bit</description>
              <bitRange>[4:4]</bitRange>
            </field>
            <field>
              <name>TDRE</name>
              <description>Transmit Holding Register Empty bit</description>
              <bitRange>[5:5]</bitRange>
              <access>read-only</access>
            </field>
            <field>
              <name>TXE</name>
              <description>Transmitter Empty bit</description>
              <bitRange>[6:6]</bitRange>
              <access>read-only</access>
            </field>
            <field>
              <name>ADDR_RCVD</name>
              <description>Address Received Bit</description>
              <bitRange>[8:8]</bitRange>
            </field>
            <field>
              <name>BUSY</name>
              <description>UART Busy</description>
              <bitRange>[9:9]</bitRange>
              <access>read-only</access>
            </field>
            <field>
              <name>BUSY_ERR</name>
              <description>Busy Detect Error</description>
              <bitRange>[10:10]</bitRange>
            </field>
          </fields>
        </register>
        <register>
          <name>CR1</name>
          <addressOffset>0x14</addressOffset>
          <fields>
            <field>
              <name>M</name>
              <description>Data Length Select</description>
              <bitRange>[1:0]</bitRange>
            </field>
            <field>
              <name>STOP</name>
              <description>Number of stop bits</description>
              <bitRange>[2:2]</bitRange>
            </field>
            <field>
              <name>PCE</name>
              <description>Parity Enable</description>
              <bitRange>[3:3]</bitRange>
            </field>
            <field>
              <name>PS</name>
              <description>Even Parity Select</description>
              <bitRange>[4:4]</bitRange>
            </field>
            <field>
              <name>SP</name>
              <description>Stick Parity</description>
              <bitRange>[5:5]</bitRange>
            </field>
            <field>
              <name>SBK</name>
              <description>Send Break</description>
              <bitRange>[6:6]</bitRange>
            </field>
            <field>
              <name>SWAP</name>
              <description>TX/RX pin swap</description>
              <bitRange>[8:8]</bitRange>
            </field>
            <field>
              <name>MSBFIRST</name>
              <description>MSB first mode</description>
              <bitRange>[9:9]</bitRange>
            </field>
          </fields>
        </register>
        <register>
          <name>CR2</name>
          <addressOffset>0x18</addressOffset>
          <fields>
            <field>
              <name>RXNEIE</name>
              <description>Enable Received Data Available Interrupt</description>
              <bitRange>[0:0]</bitRange>
            </field>
            <field>
              <name>TDREIE</name>
              <description>Enable Transmit Holding Register Empty Interrupt</description>
              <bitRange>[1:1]</bitRange>
            </field>
            <field>
              <name>LSIE</name>
              <description>Enable Receiver Line Status Interrupt</description>
              <bitRange>[2:2]</bitRange>
            </field>
            <field>
              <name>BUSYERRIE</name>
              <description>Enable Busyerr state interruption</description>
              <bitRange>[3:3]</bitRange>
            </field>
          </fields>
        </register>
        <register>
          <name>CR3</name>
          <addressOffset>0x1C</addressOffset>
          <fields>
            <field>
              <name>M_E</name>
              <description>Extension for DLS</description>
              <bitRange>[0:0]</bitRange>
            </field>
            <field>
              <name>ADDR_MATCH</name>
              <description>Address Match Mode</description>
              <bitRange>[1:1]</bitRange>
            </field>
            <field>
              <name>SEND_ADDR</name>
              <description>Send address control bit</description>
              <bitRange>[2:2]</bitRange>
            </field>
            <field>
              <name>TX_MODE</name>
              <description>Transmit mode control bit</description>
              <bitRange>[3:3]</bitRange>
            </field>
            <field>
              <name>DMAR</name>
              <description>DMA receive enable</description>
              <bitRange>[4:4]</bitRange>
            </field>
            <field>
              <name>DMAT</name>
              <description>DMA transmit enable</description>
              <bitRange>[5:5]</bitRange>
            </field>
            <field>
              <name>DMA_SOFT_ACK</name>
              <description>DMA software ack</description>
              <bitRange>[6:6]</bitRange>
            </field>
          </fields>
        </register>
        <register>
          <name>RAR</name>
          <addressOffset>0x20</addressOffset>
          <fields>
            <field>
              <name>RAR</name>
              <description>Receive address matching register</description>
              <bitRange>[7:0]</bitRange>
            </field>
          </fields>
        </register>
        <register>
          <name>TAR</name>
          <addressOffset>0x24</addressOffset>
          <fields>
            <field>
              <name>TAR</name>
              <description>Transmit address matching register</description>
              <bitRange>[7:0]</bitRange>
            </field>
          </fields>
        </register>
        <register>
          <name>BRRF</name>
          <addressOffset>0x28</addressOffset>
          <fields>
            <field>
              <name>BRRF</name>
              <description>Baud rate fractional register</description>
              <bitRange>[3:0]</bitRange>
            </field>
          </fields>
        </register>
      </registers>
    </peripheral>
    <peripheral derivedFrom="UART1">
      <name>UART2</name>
      <baseAddress>0x40005000</baseAddress>
    </peripheral>
    <peripheral>
      <name>USART</name>
      <baseAddress>0x40013800</baseAddress>
      <addressBlock>
        <offset>0x0</offset>
        <size>0x20</size>
        <usage>registers</usage>
      </addressBlock>
      <registers>
        <register>
          <name>SR</name>
          <addressOffset>0x0</addressOffset>
          <fields>
            <field>
              <name>PE</name>
              <description>Parity error</description>
              <bitRange>[0:0]</bitRange>
              <access>read-only</access>
            </field>
            <field>
              <name>FE</name>
              <description>Framing error</description>
              <bitRange>[1:1]</bitRange>
              <access>read-only</access>
            </field>
            <field>
              <name>NE</name>
              <description>Noise error flag</description>
              <bitRange>[2:2]</bitRange>
              <access>read-only</access>
            </field>
            <field>
              <name>ORE</name>
              <description>overrun error</description>
              <bitRange>[3:3]</bitRange>
              <access>read-only</access>
            </field>
            <field>
              <name>IDLE</name>
              <description>idle</description>
              <bitRange>[4:4]</bitRange>
              <access>read-only</access>
            </field>
            <field>
              <name>RXNE_RXFNF</name>
              <description>Read data register not empty</description>
              <bitRange>[5:5]</bitRange>
              <access>read-only</access>
            </field>
            <field>
              <name>TC</name>
              <description>Transmission complete</description>
              <bitRange>[6:6]</bitRange>
              <access>read-only</access>
            </field>
            <field>
              <name>TXE_TXFNF</name>
              <description>Transmit data register empty</description>
              <bitRange>[7:7]</bitRange>
              <access>read-only</access>
            </field>
            <field>
              <name>LBD</name>
              <description>LIN break detection flag</description>
              <bitRange>[8:8]</bitRange>
            </field>
            <field>
              <name>CTS</name>
              <description>cts flag</description>
              <bitRange>[9:9]</bitRange>
            </field>
            <field>
              <name>ABRF</name>
              <description>auto baud rate flag</description>
              <bitRange>[10:10]</bitRange>
              <access>read-only</access>
            </field>
            <field>
              <name>ABRE</name>
              <description>auto baud rateerror</description>
              <bitRange>[11:11]</bitRange>
              <access>read-only</access>
            </field>
            <field>
              <name>ABRQ</name>
              <description>auto baud rate req</description>
              <bitRange>[12:12]</bitRange>
              <access>read-only</access>
            </field>
            <field>
              <name>TXFT</name>
              <description>txfifo threshold flag</description>
              <bitRange>[13:13]</bitRange>
              <access>read-only</access>
            </field>
            <field>
              <name>RXFT</name>
              <description>rxfifo threshoold flag</description>
              <bitRange>[14:14]</bitRange>
              <access>read-only</access>
            </field>
            <field>
              <name>RXFF</name>
              <description>rxfifo full</description>
              <bitRange>[15:15]</bitRange>
              <access>read-only</access>
            </field>
            <field>
              <name>TXFE</name>
              <description>txfifo empty</description>
              <bitRange>[16:16]</bitRange>
              <access>read-only</access>
            </field>
            <field>
              <name>EOBF</name>
              <description>end of block flag</description>
              <bitRange>[18:18]</bitRange>
            </field>
            <field>
              <name>RTOF</name>
              <description>rto flag</description>
              <bitRange>[19:19]</bitRange>
            </field>
          </fields>
        </register>
        <register>
          <name>DR</name>
          <addressOffset>0x4</addressOffset>
          <fields>
            <field>
              <name>TDR</name>
              <description>tdr</description>
              <bitRange>[8:0]</bitRange>
            </field>
          </fields>
        </register>
        <register>
          <name>BRR</name>
          <addressOffset>0x8</addressOffset>
          <fields>
            <field>
              <name>DIV_F</name>
              <description>DIV_Fraction</description>
              <bitRange>[3:0]</bitRange>
            </field>
            <field>
              <name>DIV_M</name>
              <description>DIV_Mantissa</description>
              <bitRange>[15:4]</bitRange>
            </field>
          </fields>
        </register>
        <register>
          <name>CR1</name>
          <addressOffset>0xC</addressOffset>
          <fields>
            <field>
              <name>SBK</name>
              <description>Send break</description>
              <bitRange>[0:0]</bitRange>
            </field>
            <field>
              <name>RWU</name>
              <description>Receiver wakeup</description>
              <bitRange>[1:1]</bitRange>
            </field>
            <field>
              <name>RE</name>
              <description>Receiver enable</description>
              <bitRange>[2:2]</bitRange>
            </field>
            <field>
              <name>TE</name>
              <description>Transmitter enable</description>
              <bitRange>[3:3]</bitRange>
            </field>
            <field>
              <name>IDLEIE</name>
              <description>IDLE interrupt enable</description>
              <bitRange>[4:4]</bitRange>
            </field>
            <field>
              <name>RXNEIE</name>
              <description>RXNE interrupt enable</description>
              <bitRange>[5:5]</bitRange>
            </field>
            <field>
              <name>TCIE</name>
              <description>send complete int enable</description>
              <bitRange>[6:6]</bitRange>
            </field>
            <field>
              <name>TXEIE</name>
              <description>txe</description>
              <bitRange>[7:7]</bitRange>
            </field>
            <field>
              <name>PEIE</name>
              <description>PE interrupt enable</description>
              <bitRange>[8:8]</bitRange>
            </field>
            <field>
              <name>PS</name>
              <description>Parity selection</description>
              <bitRange>[9:9]</bitRange>
            </field>
            <field>
              <name>PCE</name>
              <description>Parity control enable</description>
              <bitRange>[10:10]</bitRange>
            </field>
            <field>
              <name>WAKE</name>
              <description>Wakeup method</description>
              <bitRange>[11:11]</bitRange>
            </field>
            <field>
              <name>M0</name>
              <description>word length</description>
              <bitRange>[12:12]</bitRange>
            </field>
            <field>
              <name>UE</name>
              <description>uesart enable</description>
              <bitRange>[13:13]</bitRange>
            </field>
            <field>
              <name>M1</name>
              <description>word length</description>
              <bitRange>[14:14]</bitRange>
            </field>
            <field>
              <name>MSB</name>
              <description>msb</description>
              <bitRange>[15:15]</bitRange>
            </field>
            <field>
              <name>ADDM7</name>
              <description>addm7</description>
              <bitRange>[17:17]</bitRange>
            </field>
            <field>
              <name>SWAP</name>
              <description>swap</description>
              <bitRange>[18:18]</bitRange>
            </field>
            <field>
              <name>TXFTCFG</name>
              <description>txfifo threshoold cfg</description>
              <bitRange>[21:19]</bitRange>
            </field>
            <field>
              <name>RXFTCFG</name>
              <description>rxfifo threshoold cfg</description>
              <bitRange>[24:22]</bitRange>
            </field>
            <field>
              <name>RX_INV</name>
              <description>rxinv</description>
              <bitRange>[25:25]</bitRange>
            </field>
            <field>
              <name>TX_INV</name>
              <description>txinv</description>
              <bitRange>[26:26]</bitRange>
            </field>
            <field>
              <name>DATAINV</name>
              <description>datainv</description>
              <bitRange>[27:27]</bitRange>
            </field>
            <field>
              <name>RXFRQ</name>
              <description>receive data flush request</description>
              <bitRange>[29:29]</bitRange>
            </field>
            <field>
              <name>TXFRQ</name>
              <description>Transmit data flush request</description>
              <bitRange>[30:30]</bitRange>
            </field>
            <field>
              <name>FIFOEN</name>
              <description>fifo en</description>
              <bitRange>[31:31]</bitRange>
            </field>
          </fields>
        </register>
        <register>
          <name>CR2</name>
          <addressOffset>0x10</addressOffset>
          <fields>
            <field>
              <name>LBDL</name>
              <description>LIN break detection length</description>
              <bitRange>[5:5]</bitRange>
            </field>
            <field>
              <name>LBDIE</name>
              <description>lin break enable</description>
              <bitRange>[6:6]</bitRange>
            </field>
            <field>
              <name>LBCL</name>
              <description>lbcl</description>
              <bitRange>[8:8]</bitRange>
            </field>
            <field>
              <name>CPHA</name>
              <description>cpha</description>
              <bitRange>[9:9]</bitRange>
            </field>
            <field>
              <name>CPOL</name>
              <description>cpol</description>
              <bitRange>[10:10]</bitRange>
            </field>
            <field>
              <name>CLKEN</name>
              <description>clk en</description>
              <bitRange>[11:11]</bitRange>
            </field>
            <field>
              <name>STOP</name>
              <description>stop bit</description>
              <bitRange>[13:12]</bitRange>
            </field>
            <field>
              <name>LINEN</name>
              <description>lin enable</description>
              <bitRange>[14:14]</bitRange>
            </field>
            <field>
              <name>ADD</name>
              <description>address</description>
              <bitRange>[22:15]</bitRange>
            </field>
            <field>
              <name>DEM</name>
              <description>dem</description>
              <bitRange>[23:23]</bitRange>
            </field>
            <field>
              <name>DEP</name>
              <description>dep</description>
              <bitRange>[24:24]</bitRange>
            </field>
            <field>
              <name>RTOEN</name>
              <description>Receiver timeout enable</description>
              <bitRange>[25:25]</bitRange>
            </field>
          </fields>
        </register>
        <register>
          <name>CR3</name>
          <addressOffset>0x14</addressOffset>
          <fields>
            <field>
              <name>EIE</name>
              <description>error int enable</description>
              <bitRange>[0:0]</bitRange>
            </field>
            <field>
              <name>IREN</name>
              <description>iren enable</description>
              <bitRange>[1:1]</bitRange>
            </field>
            <field>
              <name>IRLP</name>
              <description>idra lowpower</description>
              <bitRange>[2:2]</bitRange>
            </field>
            <field>
              <name>HDSEL</name>
              <description>hdsel</description>
              <bitRange>[3:3]</bitRange>
            </field>
            <field>
              <name>NACK</name>
              <description>scen nack enable</description>
              <bitRange>[4:4]</bitRange>
            </field>
            <field>
              <name>SCEN</name>
              <description>scen enable</description>
              <bitRange>[5:5]</bitRange>
            </field>
            <field>
              <name>DMAR</name>
              <description>dma rx enable</description>
              <bitRange>[6:6]</bitRange>
            </field>
            <field>
              <name>DMAT</name>
              <description>dma tx enable</description>
              <bitRange>[7:7]</bitRange>
            </field>
            <field>
              <name>RTSE</name>
              <description>rts enable</description>
              <bitRange>[8:8]</bitRange>
            </field>
            <field>
              <name>CTSE</name>
              <description>cts enable</description>
              <bitRange>[9:9]</bitRange>
            </field>
            <field>
              <name>CTSIE</name>
              <description>cts int enable</description>
              <bitRange>[10:10]</bitRange>
            </field>
            <field>
              <name>OVER8</name>
              <description>oversampling</description>
              <bitRange>[11:11]</bitRange>
            </field>
            <field>
              <name>ABREN</name>
              <description>autobaud enable</description>
              <bitRange>[12:12]</bitRange>
            </field>
            <field>
              <name>ABRMOD</name>
              <description>auto baud mod</description>
              <bitRange>[14:13]</bitRange>
            </field>
            <field>
              <name>RXFFIE</name>
              <description>rxff int enable</description>
              <bitRange>[15:15]</bitRange>
            </field>
            <field>
              <name>TXFEIE</name>
              <description>txfe int enable</description>
              <bitRange>[16:16]</bitRange>
            </field>
            <field>
              <name>RXFTIE</name>
              <description>rxft int enable</description>
              <bitRange>[17:17]</bitRange>
            </field>
            <field>
              <name>TXFTIE</name>
              <description>txft int enable</description>
              <bitRange>[18:18]</bitRange>
            </field>
            <field>
              <name>DEDT</name>
              <description>dedt int enable</description>
              <bitRange>[23:19]</bitRange>
            </field>
            <field>
              <name>DEAT</name>
              <description>deat int enable</description>
              <bitRange>[28:24]</bitRange>
            </field>
            <field>
              <name>RTOIE</name>
              <description>rto int enable</description>
              <bitRange>[29:29]</bitRange>
            </field>
            <field>
              <name>EOBIE</name>
              <description>eob int enable</description>
              <bitRange>[30:30]</bitRange>
            </field>
          </fields>
        </register>
        <register>
          <name>GTPR</name>
          <addressOffset>0x18</addressOffset>
          <fields>
            <field>
              <name>PSC</name>
              <description>Prescaler value</description>
              <bitRange>[7:0]</bitRange>
            </field>
            <field>
              <name>GT</name>
              <description>Guard time value</description>
              <bitRange>[15:8]</bitRange>
            </field>
          </fields>
        </register>
        <register>
          <name>RTOR</name>
          <addressOffset>0x1C</addressOffset>
          <fields>
            <field>
              <name>RTO</name>
              <description>receive timeout</description>
              <bitRange>[23:0]</bitRange>
            </field>
            <field>
              <name>BLEN</name>
              <description>blocken length</description>
              <bitRange>[31:24]</bitRange>
            </field>
          </fields>
        </register>
      </registers>
    </peripheral>
    <peripheral>
      <name>WWDG</name>
      <baseAddress>0x40002C00</baseAddress>
      <addressBlock>
        <offset>0x0</offset>
        <size>0x10</size>
        <usage>registers</usage>
      </addressBlock>
      <interrupt>
        <name>WWDG</name>
        <description>Window WatchDog global Interrupt</description>
        <value>0</value>
      </interrupt>
      <registers>
        <register>
          <name>WWDR_CR</name>
          <addressOffset>0x0</addressOffset>
          <fields>
            <field>
              <name>T</name>
              <description>wwdg counter</description>
              <bitRange>[6:0]</bitRange>
            </field>
            <field>
              <name>WDGA</name>
              <description>WWDG Activation</description>
              <bitRange>[7:7]</bitRange>
            </field>
          </fields>
        </register>
        <register>
          <name>CFR</name>
          <addressOffset>0x4</addressOffset>
          <fields>
            <field>
              <name>W</name>
              <description>window value</description>
              <bitRange>[6:0]</bitRange>
            </field>
            <field>
              <name>WDGTB</name>
              <description>time base</description>
              <bitRange>[8:7]</bitRange>
            </field>
            <field>
              <name>EWI</name>
              <description>Early wakeup interrupt</description>
              <bitRange>[9:9]</bitRange>
            </field>
          </fields>
        </register>
        <register>
          <name>SR</name>
          <addressOffset>0x8</addressOffset>
          <size>16</size>
          <fields>
            <field>
              <name>EWIF</name>
              <description>Early wakeup interrupt flag</description>
              <bitRange>[0:0]</bitRange>
            </field>
          </fields>
        </register>
      </registers>
    </peripheral>
  </peripherals>
</device>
